VERSION 5.7 ;
  NOWIREEXTENSIONATPIN ON ;
  DIVIDERCHAR "/" ;
  BUSBITCHARS "[]" ;
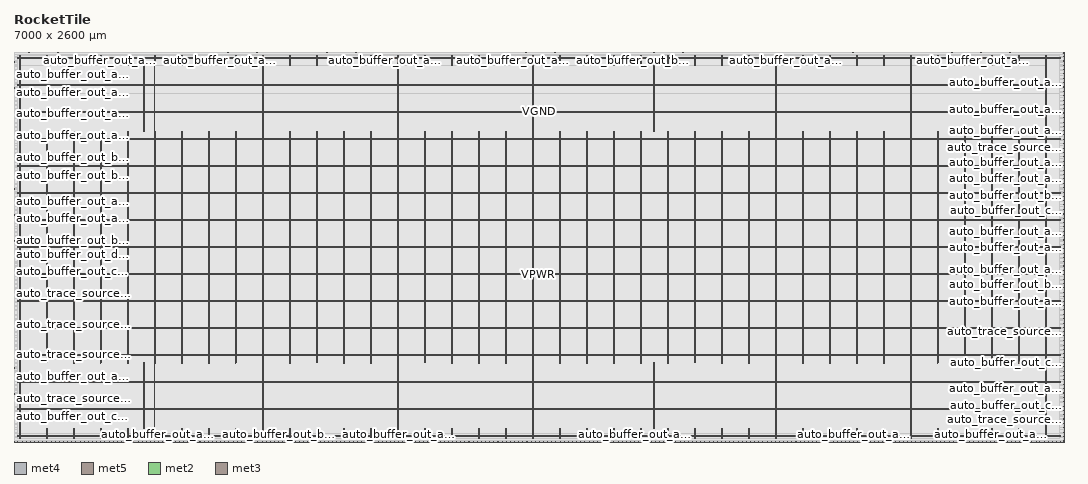
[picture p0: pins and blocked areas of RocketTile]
MACRO RocketTile
  CLASS BLOCK ;
  FOREIGN RocketTile ;
  ORIGIN 0.000 0.000 ;
  SIZE 7000.000 BY 2600.000 ;
  PIN VGND
    DIRECTION INOUT ;
    USE GROUND ;
    PORT
      LAYER met4 ;
        RECT 39.060 21.520 40.660 2578.800 ;
    END
    PORT
      LAYER met4 ;
        RECT 219.060 21.520 220.660 90.020 ;
    END
    PORT
      LAYER met4 ;
        RECT 219.060 527.140 220.660 2072.400 ;
    END
    PORT
      LAYER met4 ;
        RECT 219.060 2509.520 220.660 2578.800 ;
    END
    PORT
      LAYER met4 ;
        RECT 399.060 21.520 400.660 90.020 ;
    END
    PORT
      LAYER met4 ;
        RECT 399.060 526.520 400.660 2073.020 ;
    END
    PORT
      LAYER met4 ;
        RECT 399.060 2509.520 400.660 2578.800 ;
    END
    PORT
      LAYER met4 ;
        RECT 579.060 21.520 580.660 89.400 ;
    END
    PORT
      LAYER met4 ;
        RECT 579.060 527.140 580.660 2072.400 ;
    END
    PORT
      LAYER met4 ;
        RECT 579.060 2510.140 580.660 2578.800 ;
    END
    PORT
      LAYER met4 ;
        RECT 759.060 21.520 760.660 90.020 ;
    END
    PORT
      LAYER met4 ;
        RECT 759.060 526.520 760.660 2073.020 ;
    END
    PORT
      LAYER met4 ;
        RECT 759.060 2509.520 760.660 2578.800 ;
    END
    PORT
      LAYER met4 ;
        RECT 939.060 21.520 940.660 90.020 ;
    END
    PORT
      LAYER met4 ;
        RECT 939.060 526.520 940.660 2073.020 ;
    END
    PORT
      LAYER met4 ;
        RECT 939.060 2509.520 940.660 2578.800 ;
    END
    PORT
      LAYER met4 ;
        RECT 1119.060 21.520 1120.660 90.020 ;
    END
    PORT
      LAYER met4 ;
        RECT 1119.060 526.520 1120.660 2073.020 ;
    END
    PORT
      LAYER met4 ;
        RECT 1119.060 2509.520 1120.660 2578.800 ;
    END
    PORT
      LAYER met4 ;
        RECT 1299.060 21.520 1300.660 90.020 ;
    END
    PORT
      LAYER met4 ;
        RECT 1299.060 526.520 1300.660 2073.020 ;
    END
    PORT
      LAYER met4 ;
        RECT 1299.060 2509.520 1300.660 2578.800 ;
    END
    PORT
      LAYER met4 ;
        RECT 1479.060 21.520 1480.660 89.400 ;
    END
    PORT
      LAYER met4 ;
        RECT 1479.060 527.140 1480.660 2072.400 ;
    END
    PORT
      LAYER met4 ;
        RECT 1479.060 2510.140 1480.660 2578.800 ;
    END
    PORT
      LAYER met4 ;
        RECT 1659.060 21.520 1660.660 2578.800 ;
    END
    PORT
      LAYER met4 ;
        RECT 1839.060 21.520 1840.660 90.020 ;
    END
    PORT
      LAYER met4 ;
        RECT 1839.060 526.520 1840.660 2073.020 ;
    END
    PORT
      LAYER met4 ;
        RECT 1839.060 2509.520 1840.660 2578.800 ;
    END
    PORT
      LAYER met4 ;
        RECT 2019.060 21.520 2020.660 90.020 ;
    END
    PORT
      LAYER met4 ;
        RECT 2019.060 527.140 2020.660 2072.400 ;
    END
    PORT
      LAYER met4 ;
        RECT 2019.060 2509.520 2020.660 2578.800 ;
    END
    PORT
      LAYER met4 ;
        RECT 2199.060 21.520 2200.660 90.020 ;
    END
    PORT
      LAYER met4 ;
        RECT 2199.060 526.520 2200.660 2073.020 ;
    END
    PORT
      LAYER met4 ;
        RECT 2199.060 2509.520 2200.660 2578.800 ;
    END
    PORT
      LAYER met4 ;
        RECT 2379.060 21.520 2380.660 90.020 ;
    END
    PORT
      LAYER met4 ;
        RECT 2379.060 526.520 2380.660 2073.020 ;
    END
    PORT
      LAYER met4 ;
        RECT 2379.060 2509.520 2380.660 2578.800 ;
    END
    PORT
      LAYER met4 ;
        RECT 2559.060 21.520 2560.660 2578.800 ;
    END
    PORT
      LAYER met4 ;
        RECT 2739.060 21.520 2740.660 90.020 ;
    END
    PORT
      LAYER met4 ;
        RECT 2739.060 527.140 2740.660 2072.400 ;
    END
    PORT
      LAYER met4 ;
        RECT 2739.060 2509.520 2740.660 2578.800 ;
    END
    PORT
      LAYER met4 ;
        RECT 2919.060 21.520 2920.660 90.020 ;
    END
    PORT
      LAYER met4 ;
        RECT 2919.060 526.520 2920.660 2073.020 ;
    END
    PORT
      LAYER met4 ;
        RECT 2919.060 2509.520 2920.660 2578.800 ;
    END
    PORT
      LAYER met4 ;
        RECT 3099.060 21.520 3100.660 90.020 ;
    END
    PORT
      LAYER met4 ;
        RECT 3099.060 526.520 3100.660 2073.020 ;
    END
    PORT
      LAYER met4 ;
        RECT 3099.060 2509.520 3100.660 2578.800 ;
    END
    PORT
      LAYER met4 ;
        RECT 3279.060 21.520 3280.660 90.020 ;
    END
    PORT
      LAYER met4 ;
        RECT 3279.060 526.520 3280.660 2073.020 ;
    END
    PORT
      LAYER met4 ;
        RECT 3279.060 2509.520 3280.660 2578.800 ;
    END
    PORT
      LAYER met4 ;
        RECT 3459.060 21.520 3460.660 2578.800 ;
    END
    PORT
      LAYER met4 ;
        RECT 3639.060 21.520 3640.660 90.020 ;
    END
    PORT
      LAYER met4 ;
        RECT 3639.060 526.520 3640.660 2073.020 ;
    END
    PORT
      LAYER met4 ;
        RECT 3639.060 2509.520 3640.660 2578.800 ;
    END
    PORT
      LAYER met4 ;
        RECT 3819.060 21.520 3820.660 89.400 ;
    END
    PORT
      LAYER met4 ;
        RECT 3819.060 526.520 3820.660 2073.020 ;
    END
    PORT
      LAYER met4 ;
        RECT 3819.060 2510.140 3820.660 2578.800 ;
    END
    PORT
      LAYER met4 ;
        RECT 3999.060 21.520 4000.660 90.020 ;
    END
    PORT
      LAYER met4 ;
        RECT 3999.060 526.520 4000.660 2073.020 ;
    END
    PORT
      LAYER met4 ;
        RECT 3999.060 2509.520 4000.660 2578.800 ;
    END
    PORT
      LAYER met4 ;
        RECT 4179.060 21.520 4180.660 90.020 ;
    END
    PORT
      LAYER met4 ;
        RECT 4179.060 526.520 4180.660 2073.020 ;
    END
    PORT
      LAYER met4 ;
        RECT 4179.060 2509.520 4180.660 2578.800 ;
    END
    PORT
      LAYER met4 ;
        RECT 4359.060 21.520 4360.660 90.020 ;
    END
    PORT
      LAYER met4 ;
        RECT 4359.060 526.520 4360.660 2073.020 ;
    END
    PORT
      LAYER met4 ;
        RECT 4359.060 2509.520 4360.660 2578.800 ;
    END
    PORT
      LAYER met4 ;
        RECT 4539.060 21.520 4540.660 90.020 ;
    END
    PORT
      LAYER met4 ;
        RECT 4539.060 527.140 4540.660 2072.400 ;
    END
    PORT
      LAYER met4 ;
        RECT 4539.060 2509.520 4540.660 2578.800 ;
    END
    PORT
      LAYER met4 ;
        RECT 4719.060 21.520 4720.660 90.020 ;
    END
    PORT
      LAYER met4 ;
        RECT 4719.060 526.520 4720.660 2073.020 ;
    END
    PORT
      LAYER met4 ;
        RECT 4719.060 2509.520 4720.660 2578.800 ;
    END
    PORT
      LAYER met4 ;
        RECT 4899.060 21.520 4900.660 90.020 ;
    END
    PORT
      LAYER met4 ;
        RECT 4899.060 526.520 4900.660 2073.020 ;
    END
    PORT
      LAYER met4 ;
        RECT 4899.060 2509.520 4900.660 2578.800 ;
    END
    PORT
      LAYER met4 ;
        RECT 5079.060 21.520 5080.660 2578.800 ;
    END
    PORT
      LAYER met4 ;
        RECT 5259.060 21.520 5260.660 90.020 ;
    END
    PORT
      LAYER met4 ;
        RECT 5259.060 526.520 5260.660 2073.020 ;
    END
    PORT
      LAYER met4 ;
        RECT 5259.060 2509.520 5260.660 2578.800 ;
    END
    PORT
      LAYER met4 ;
        RECT 5439.060 21.520 5440.660 90.020 ;
    END
    PORT
      LAYER met4 ;
        RECT 5439.060 526.520 5440.660 2073.020 ;
    END
    PORT
      LAYER met4 ;
        RECT 5439.060 2509.520 5440.660 2578.800 ;
    END
    PORT
      LAYER met4 ;
        RECT 5619.060 21.520 5620.660 90.020 ;
    END
    PORT
      LAYER met4 ;
        RECT 5619.060 526.520 5620.660 2073.020 ;
    END
    PORT
      LAYER met4 ;
        RECT 5619.060 2509.520 5620.660 2578.800 ;
    END
    PORT
      LAYER met4 ;
        RECT 5799.060 21.520 5800.660 89.400 ;
    END
    PORT
      LAYER met4 ;
        RECT 5799.060 526.520 5800.660 2073.020 ;
    END
    PORT
      LAYER met4 ;
        RECT 5799.060 2510.140 5800.660 2578.800 ;
    END
    PORT
      LAYER met4 ;
        RECT 5979.060 21.520 5980.660 2578.800 ;
    END
    PORT
      LAYER met4 ;
        RECT 6159.060 21.520 6160.660 90.020 ;
    END
    PORT
      LAYER met4 ;
        RECT 6159.060 527.140 6160.660 2072.400 ;
    END
    PORT
      LAYER met4 ;
        RECT 6159.060 2509.520 6160.660 2578.800 ;
    END
    PORT
      LAYER met4 ;
        RECT 6339.060 21.520 6340.660 90.020 ;
    END
    PORT
      LAYER met4 ;
        RECT 6339.060 527.140 6340.660 2072.400 ;
    END
    PORT
      LAYER met4 ;
        RECT 6339.060 2509.520 6340.660 2578.800 ;
    END
    PORT
      LAYER met4 ;
        RECT 6519.060 21.520 6520.660 90.020 ;
    END
    PORT
      LAYER met4 ;
        RECT 6519.060 526.520 6520.660 2073.020 ;
    END
    PORT
      LAYER met4 ;
        RECT 6519.060 2509.520 6520.660 2578.800 ;
    END
    PORT
      LAYER met4 ;
        RECT 6699.060 21.520 6700.660 90.020 ;
    END
    PORT
      LAYER met4 ;
        RECT 6699.060 526.520 6700.660 2073.020 ;
    END
    PORT
      LAYER met4 ;
        RECT 6699.060 2509.520 6700.660 2578.800 ;
    END
    PORT
      LAYER met4 ;
        RECT 6879.060 21.520 6880.660 2578.800 ;
    END
    PORT
      LAYER met5 ;
        RECT 20.000 40.910 6979.820 42.510 ;
    END
    PORT
      LAYER met5 ;
        RECT 20.000 220.910 6979.820 222.510 ;
    END
    PORT
      LAYER met5 ;
        RECT 20.000 400.910 6979.820 402.510 ;
    END
    PORT
      LAYER met5 ;
        RECT 20.000 580.910 6979.820 582.510 ;
    END
    PORT
      LAYER met5 ;
        RECT 20.000 760.910 6979.820 762.510 ;
    END
    PORT
      LAYER met5 ;
        RECT 20.000 940.910 6979.820 942.510 ;
    END
    PORT
      LAYER met5 ;
        RECT 20.000 1120.910 6979.820 1122.510 ;
    END
    PORT
      LAYER met5 ;
        RECT 20.000 1300.910 6979.820 1302.510 ;
    END
    PORT
      LAYER met5 ;
        RECT 20.000 1480.910 6979.820 1482.510 ;
    END
    PORT
      LAYER met5 ;
        RECT 20.000 1660.910 6979.820 1662.510 ;
    END
    PORT
      LAYER met5 ;
        RECT 20.000 1840.910 6979.820 1842.510 ;
    END
    PORT
      LAYER met5 ;
        RECT 20.000 2020.910 6979.820 2022.510 ;
    END
    PORT
      LAYER met5 ;
        RECT 20.000 2200.910 6979.820 2202.510 ;
    END
    PORT
      LAYER met5 ;
        RECT 20.000 2380.910 6979.820 2382.510 ;
    END
    PORT
      LAYER met5 ;
        RECT 20.000 2560.910 6979.820 2562.510 ;
    END
    PORT
      LAYER met4 ;
        RECT 865.380 86.800 866.980 527.920 ;
    END
    PORT
      LAYER met4 ;
        RECT 4267.540 2069.680 4269.140 2513.520 ;
    END
    PORT
      LAYER met4 ;
        RECT 865.380 2072.400 866.980 2513.520 ;
    END
    PORT
      LAYER met4 ;
        RECT 4267.540 86.800 4269.140 530.640 ;
    END
  END VGND
  PIN VPWR
    DIRECTION INOUT ;
    USE POWER ;
    PORT
      LAYER met4 ;
        RECT 35.760 21.520 37.360 2578.800 ;
    END
    PORT
      LAYER met4 ;
        RECT 215.760 21.520 217.360 90.020 ;
    END
    PORT
      LAYER met4 ;
        RECT 215.760 527.140 217.360 2072.400 ;
    END
    PORT
      LAYER met4 ;
        RECT 215.760 2509.520 217.360 2578.800 ;
    END
    PORT
      LAYER met4 ;
        RECT 395.760 21.520 397.360 90.020 ;
    END
    PORT
      LAYER met4 ;
        RECT 395.760 527.140 397.360 2072.400 ;
    END
    PORT
      LAYER met4 ;
        RECT 395.760 2509.520 397.360 2578.800 ;
    END
    PORT
      LAYER met4 ;
        RECT 575.760 21.520 577.360 90.020 ;
    END
    PORT
      LAYER met4 ;
        RECT 575.760 526.520 577.360 2073.020 ;
    END
    PORT
      LAYER met4 ;
        RECT 575.760 2509.520 577.360 2578.800 ;
    END
    PORT
      LAYER met4 ;
        RECT 755.760 21.520 757.360 90.020 ;
    END
    PORT
      LAYER met4 ;
        RECT 755.760 526.520 757.360 2073.020 ;
    END
    PORT
      LAYER met4 ;
        RECT 755.760 2509.520 757.360 2578.800 ;
    END
    PORT
      LAYER met4 ;
        RECT 935.760 21.520 937.360 2578.800 ;
    END
    PORT
      LAYER met4 ;
        RECT 1115.760 21.520 1117.360 89.400 ;
    END
    PORT
      LAYER met4 ;
        RECT 1115.760 527.140 1117.360 2072.400 ;
    END
    PORT
      LAYER met4 ;
        RECT 1115.760 2510.140 1117.360 2578.800 ;
    END
    PORT
      LAYER met4 ;
        RECT 1295.760 21.520 1297.360 90.020 ;
    END
    PORT
      LAYER met4 ;
        RECT 1295.760 526.520 1297.360 2073.020 ;
    END
    PORT
      LAYER met4 ;
        RECT 1295.760 2509.520 1297.360 2578.800 ;
    END
    PORT
      LAYER met4 ;
        RECT 1475.760 21.520 1477.360 90.020 ;
    END
    PORT
      LAYER met4 ;
        RECT 1475.760 526.520 1477.360 2073.020 ;
    END
    PORT
      LAYER met4 ;
        RECT 1475.760 2509.520 1477.360 2578.800 ;
    END
    PORT
      LAYER met4 ;
        RECT 1655.760 21.520 1657.360 2578.800 ;
    END
    PORT
      LAYER met4 ;
        RECT 1835.760 21.520 1837.360 90.020 ;
    END
    PORT
      LAYER met4 ;
        RECT 1835.760 526.520 1837.360 2073.020 ;
    END
    PORT
      LAYER met4 ;
        RECT 1835.760 2509.520 1837.360 2578.800 ;
    END
    PORT
      LAYER met4 ;
        RECT 2015.760 21.520 2017.360 89.400 ;
    END
    PORT
      LAYER met4 ;
        RECT 2015.760 527.140 2017.360 2072.400 ;
    END
    PORT
      LAYER met4 ;
        RECT 2015.760 2510.140 2017.360 2578.800 ;
    END
    PORT
      LAYER met4 ;
        RECT 2195.760 21.520 2197.360 90.020 ;
    END
    PORT
      LAYER met4 ;
        RECT 2195.760 526.520 2197.360 2073.020 ;
    END
    PORT
      LAYER met4 ;
        RECT 2195.760 2509.520 2197.360 2578.800 ;
    END
    PORT
      LAYER met4 ;
        RECT 2375.760 21.520 2377.360 90.020 ;
    END
    PORT
      LAYER met4 ;
        RECT 2375.760 526.520 2377.360 2073.020 ;
    END
    PORT
      LAYER met4 ;
        RECT 2375.760 2509.520 2377.360 2578.800 ;
    END
    PORT
      LAYER met4 ;
        RECT 2555.760 21.520 2557.360 2578.800 ;
    END
    PORT
      LAYER met4 ;
        RECT 2735.760 21.520 2737.360 90.020 ;
    END
    PORT
      LAYER met4 ;
        RECT 2735.760 527.140 2737.360 2072.400 ;
    END
    PORT
      LAYER met4 ;
        RECT 2735.760 2509.520 2737.360 2578.800 ;
    END
    PORT
      LAYER met4 ;
        RECT 2915.760 21.520 2917.360 89.400 ;
    END
    PORT
      LAYER met4 ;
        RECT 2915.760 527.140 2917.360 2072.400 ;
    END
    PORT
      LAYER met4 ;
        RECT 2915.760 2510.140 2917.360 2578.800 ;
    END
    PORT
      LAYER met4 ;
        RECT 3095.760 21.520 3097.360 90.020 ;
    END
    PORT
      LAYER met4 ;
        RECT 3095.760 526.520 3097.360 2073.020 ;
    END
    PORT
      LAYER met4 ;
        RECT 3095.760 2509.520 3097.360 2578.800 ;
    END
    PORT
      LAYER met4 ;
        RECT 3275.760 21.520 3277.360 90.020 ;
    END
    PORT
      LAYER met4 ;
        RECT 3275.760 526.520 3277.360 2073.020 ;
    END
    PORT
      LAYER met4 ;
        RECT 3275.760 2509.520 3277.360 2578.800 ;
    END
    PORT
      LAYER met4 ;
        RECT 3455.760 21.520 3457.360 2578.800 ;
    END
    PORT
      LAYER met4 ;
        RECT 3635.760 21.520 3637.360 90.020 ;
    END
    PORT
      LAYER met4 ;
        RECT 3635.760 526.520 3637.360 2073.020 ;
    END
    PORT
      LAYER met4 ;
        RECT 3635.760 2509.520 3637.360 2578.800 ;
    END
    PORT
      LAYER met4 ;
        RECT 3815.760 21.520 3817.360 90.020 ;
    END
    PORT
      LAYER met4 ;
        RECT 3815.760 527.140 3817.360 2072.400 ;
    END
    PORT
      LAYER met4 ;
        RECT 3815.760 2509.520 3817.360 2578.800 ;
    END
    PORT
      LAYER met4 ;
        RECT 3995.760 21.520 3997.360 90.020 ;
    END
    PORT
      LAYER met4 ;
        RECT 3995.760 526.520 3997.360 2073.020 ;
    END
    PORT
      LAYER met4 ;
        RECT 3995.760 2509.520 3997.360 2578.800 ;
    END
    PORT
      LAYER met4 ;
        RECT 4175.760 21.520 4177.360 90.020 ;
    END
    PORT
      LAYER met4 ;
        RECT 4175.760 526.520 4177.360 2073.020 ;
    END
    PORT
      LAYER met4 ;
        RECT 4175.760 2509.520 4177.360 2578.800 ;
    END
    PORT
      LAYER met4 ;
        RECT 4355.760 21.520 4357.360 90.020 ;
    END
    PORT
      LAYER met4 ;
        RECT 4355.760 526.520 4357.360 2073.020 ;
    END
    PORT
      LAYER met4 ;
        RECT 4355.760 2509.520 4357.360 2578.800 ;
    END
    PORT
      LAYER met4 ;
        RECT 4535.760 21.520 4537.360 90.020 ;
    END
    PORT
      LAYER met4 ;
        RECT 4535.760 527.140 4537.360 2072.400 ;
    END
    PORT
      LAYER met4 ;
        RECT 4535.760 2509.520 4537.360 2578.800 ;
    END
    PORT
      LAYER met4 ;
        RECT 4715.760 21.520 4717.360 89.400 ;
    END
    PORT
      LAYER met4 ;
        RECT 4715.760 527.140 4717.360 2072.400 ;
    END
    PORT
      LAYER met4 ;
        RECT 4715.760 2510.140 4717.360 2578.800 ;
    END
    PORT
      LAYER met4 ;
        RECT 4895.760 21.520 4897.360 90.020 ;
    END
    PORT
      LAYER met4 ;
        RECT 4895.760 526.520 4897.360 2073.020 ;
    END
    PORT
      LAYER met4 ;
        RECT 4895.760 2509.520 4897.360 2578.800 ;
    END
    PORT
      LAYER met4 ;
        RECT 5075.760 21.520 5077.360 2578.800 ;
    END
    PORT
      LAYER met4 ;
        RECT 5255.760 21.520 5257.360 90.020 ;
    END
    PORT
      LAYER met4 ;
        RECT 5255.760 526.520 5257.360 2073.020 ;
    END
    PORT
      LAYER met4 ;
        RECT 5255.760 2509.520 5257.360 2578.800 ;
    END
    PORT
      LAYER met4 ;
        RECT 5435.760 21.520 5437.360 90.020 ;
    END
    PORT
      LAYER met4 ;
        RECT 5435.760 526.520 5437.360 2073.020 ;
    END
    PORT
      LAYER met4 ;
        RECT 5435.760 2509.520 5437.360 2578.800 ;
    END
    PORT
      LAYER met4 ;
        RECT 5615.760 21.520 5617.360 89.400 ;
    END
    PORT
      LAYER met4 ;
        RECT 5615.760 527.140 5617.360 2072.400 ;
    END
    PORT
      LAYER met4 ;
        RECT 5615.760 2510.140 5617.360 2578.800 ;
    END
    PORT
      LAYER met4 ;
        RECT 5795.760 21.520 5797.360 90.020 ;
    END
    PORT
      LAYER met4 ;
        RECT 5795.760 526.520 5797.360 2073.020 ;
    END
    PORT
      LAYER met4 ;
        RECT 5795.760 2509.520 5797.360 2578.800 ;
    END
    PORT
      LAYER met4 ;
        RECT 5975.760 21.520 5977.360 2578.800 ;
    END
    PORT
      LAYER met4 ;
        RECT 6155.760 21.520 6157.360 90.020 ;
    END
    PORT
      LAYER met4 ;
        RECT 6155.760 526.520 6157.360 2073.020 ;
    END
    PORT
      LAYER met4 ;
        RECT 6155.760 2509.520 6157.360 2578.800 ;
    END
    PORT
      LAYER met4 ;
        RECT 6335.760 21.520 6337.360 90.020 ;
    END
    PORT
      LAYER met4 ;
        RECT 6335.760 527.140 6337.360 2072.400 ;
    END
    PORT
      LAYER met4 ;
        RECT 6335.760 2509.520 6337.360 2578.800 ;
    END
    PORT
      LAYER met4 ;
        RECT 6515.760 21.520 6517.360 89.400 ;
    END
    PORT
      LAYER met4 ;
        RECT 6515.760 527.140 6517.360 2072.400 ;
    END
    PORT
      LAYER met4 ;
        RECT 6515.760 2510.140 6517.360 2578.800 ;
    END
    PORT
      LAYER met4 ;
        RECT 6695.760 21.520 6697.360 90.020 ;
    END
    PORT
      LAYER met4 ;
        RECT 6695.760 526.520 6697.360 2073.020 ;
    END
    PORT
      LAYER met4 ;
        RECT 6695.760 2509.520 6697.360 2578.800 ;
    END
    PORT
      LAYER met4 ;
        RECT 6875.760 21.520 6877.360 2578.800 ;
    END
    PORT
      LAYER met5 ;
        RECT 20.000 37.610 6979.820 39.210 ;
    END
    PORT
      LAYER met5 ;
        RECT 20.000 217.610 6979.820 219.210 ;
    END
    PORT
      LAYER met5 ;
        RECT 20.000 397.610 6979.820 399.210 ;
    END
    PORT
      LAYER met5 ;
        RECT 20.000 577.610 6979.820 579.210 ;
    END
    PORT
      LAYER met5 ;
        RECT 20.000 757.610 6979.820 759.210 ;
    END
    PORT
      LAYER met5 ;
        RECT 20.000 937.610 6979.820 939.210 ;
    END
    PORT
      LAYER met5 ;
        RECT 20.000 1117.610 6979.820 1119.210 ;
    END
    PORT
      LAYER met5 ;
        RECT 20.000 1297.610 6979.820 1299.210 ;
    END
    PORT
      LAYER met5 ;
        RECT 20.000 1477.610 6979.820 1479.210 ;
    END
    PORT
      LAYER met5 ;
        RECT 20.000 1657.610 6979.820 1659.210 ;
    END
    PORT
      LAYER met5 ;
        RECT 20.000 1837.610 6979.820 1839.210 ;
    END
    PORT
      LAYER met5 ;
        RECT 20.000 2017.610 6979.820 2019.210 ;
    END
    PORT
      LAYER met5 ;
        RECT 20.000 2197.610 6979.820 2199.210 ;
    END
    PORT
      LAYER met5 ;
        RECT 20.000 2377.610 6979.820 2379.210 ;
    END
    PORT
      LAYER met5 ;
        RECT 20.000 2557.610 6979.820 2559.210 ;
    END
    PORT
      LAYER met4 ;
        RECT 4263.860 2069.680 4265.460 2513.520 ;
    END
    PORT
      LAYER met4 ;
        RECT 4263.860 86.800 4265.460 530.640 ;
    END
  END VPWR
  PIN auto_buffer_out_a_bits_address[0]
    DIRECTION OUTPUT TRISTATE ;
    USE SIGNAL ;
    ANTENNADIFFAREA 0.340600 ;
    PORT
      LAYER met2 ;
        RECT 570.030 2596.000 570.310 2600.000 ;
    END
  END auto_buffer_out_a_bits_address[0]
  PIN auto_buffer_out_a_bits_address[10]
    DIRECTION OUTPUT TRISTATE ;
    USE SIGNAL ;
    ANTENNADIFFAREA 0.340600 ;
    PORT
      LAYER met3 ;
        RECT 0.000 1601.440 4.000 1602.040 ;
    END
  END auto_buffer_out_a_bits_address[10]
  PIN auto_buffer_out_a_bits_address[11]
    DIRECTION OUTPUT TRISTATE ;
    USE SIGNAL ;
    ANTENNADIFFAREA 0.340600 ;
    PORT
      LAYER met2 ;
        RECT 2473.050 2596.000 2473.330 2600.000 ;
    END
  END auto_buffer_out_a_bits_address[11]
  PIN auto_buffer_out_a_bits_address[12]
    DIRECTION OUTPUT TRISTATE ;
    USE SIGNAL ;
    ANTENNADIFFAREA 0.340600 ;
    PORT
      LAYER met3 ;
        RECT 6996.000 414.840 7000.000 415.440 ;
    END
  END auto_buffer_out_a_bits_address[12]
  PIN auto_buffer_out_a_bits_address[13]
    DIRECTION OUTPUT TRISTATE ;
    USE SIGNAL ;
    ANTENNADIFFAREA 0.340600 ;
    PORT
      LAYER met2 ;
        RECT 5847.610 0.000 5847.890 4.000 ;
    END
  END auto_buffer_out_a_bits_address[13]
  PIN auto_buffer_out_a_bits_address[14]
    DIRECTION OUTPUT TRISTATE ;
    USE SIGNAL ;
    ANTENNADIFFAREA 0.340600 ;
    PORT
      LAYER met2 ;
        RECT 2086.650 2596.000 2086.930 2600.000 ;
    END
  END auto_buffer_out_a_bits_address[14]
  PIN auto_buffer_out_a_bits_address[15]
    DIRECTION OUTPUT TRISTATE ;
    USE SIGNAL ;
    ANTENNADIFFAREA 0.340600 ;
    PORT
      LAYER met2 ;
        RECT 4137.790 0.000 4138.070 4.000 ;
    END
  END auto_buffer_out_a_bits_address[15]
  PIN auto_buffer_out_a_bits_address[16]
    DIRECTION OUTPUT TRISTATE ;
    USE SIGNAL ;
    ANTENNADIFFAREA 0.340600 ;
    PORT
      LAYER met3 ;
        RECT 0.000 608.640 4.000 609.240 ;
    END
  END auto_buffer_out_a_bits_address[16]
  PIN auto_buffer_out_a_bits_address[17]
    DIRECTION OUTPUT TRISTATE ;
    USE SIGNAL ;
    ANTENNADIFFAREA 0.340600 ;
    PORT
      LAYER met2 ;
        RECT 962.870 0.000 963.150 4.000 ;
    END
  END auto_buffer_out_a_bits_address[17]
  PIN auto_buffer_out_a_bits_address[18]
    DIRECTION OUTPUT TRISTATE ;
    USE SIGNAL ;
    ANTENNADIFFAREA 0.340600 ;
    PORT
      LAYER met3 ;
        RECT 6996.000 2397.040 7000.000 2397.640 ;
    END
  END auto_buffer_out_a_bits_address[18]
  PIN auto_buffer_out_a_bits_address[19]
    DIRECTION OUTPUT TRISTATE ;
    USE SIGNAL ;
    ANTENNADIFFAREA 0.340600 ;
    PORT
      LAYER met2 ;
        RECT 6391.790 2596.000 6392.070 2600.000 ;
    END
  END auto_buffer_out_a_bits_address[19]
  PIN auto_buffer_out_a_bits_address[1]
    DIRECTION OUTPUT TRISTATE ;
    USE SIGNAL ;
    ANTENNADIFFAREA 0.340600 ;
    PORT
      LAYER met2 ;
        RECT 1342.830 2596.000 1343.110 2600.000 ;
    END
  END auto_buffer_out_a_bits_address[1]
  PIN auto_buffer_out_a_bits_address[20]
    DIRECTION OUTPUT TRISTATE ;
    USE SIGNAL ;
    ANTENNADIFFAREA 0.340600 ;
    PORT
      LAYER met2 ;
        RECT 3329.570 2596.000 3329.850 2600.000 ;
    END
  END auto_buffer_out_a_bits_address[20]
  PIN auto_buffer_out_a_bits_address[21]
    DIRECTION OUTPUT TRISTATE ;
    USE SIGNAL ;
    ANTENNADIFFAREA 0.340600 ;
    PORT
      LAYER met2 ;
        RECT 1812.950 2596.000 1813.230 2600.000 ;
    END
  END auto_buffer_out_a_bits_address[21]
  PIN auto_buffer_out_a_bits_address[22]
    DIRECTION OUTPUT TRISTATE ;
    USE SIGNAL ;
    ANTENNADIFFAREA 0.340600 ;
    PORT
      LAYER met3 ;
        RECT 6996.000 357.040 7000.000 357.640 ;
    END
  END auto_buffer_out_a_bits_address[22]
  PIN auto_buffer_out_a_bits_address[23]
    DIRECTION OUTPUT TRISTATE ;
    USE SIGNAL ;
    ANTENNADIFFAREA 0.340600 ;
    PORT
      LAYER met3 ;
        RECT 6996.000 938.440 7000.000 939.040 ;
    END
  END auto_buffer_out_a_bits_address[23]
  PIN auto_buffer_out_a_bits_address[24]
    DIRECTION OUTPUT TRISTATE ;
    USE SIGNAL ;
    ANTENNADIFFAREA 0.340600 ;
    PORT
      LAYER met2 ;
        RECT 1957.850 0.000 1958.130 4.000 ;
    END
  END auto_buffer_out_a_bits_address[24]
  PIN auto_buffer_out_a_bits_address[25]
    DIRECTION OUTPUT TRISTATE ;
    USE SIGNAL ;
    ANTENNADIFFAREA 0.340600 ;
    PORT
      LAYER met2 ;
        RECT 6510.930 0.000 6511.210 4.000 ;
    END
  END auto_buffer_out_a_bits_address[25]
  PIN auto_buffer_out_a_bits_address[26]
    DIRECTION OUTPUT TRISTATE ;
    USE SIGNAL ;
    ANTENNADIFFAREA 0.340600 ;
    PORT
      LAYER met2 ;
        RECT 4855.850 0.000 4856.130 4.000 ;
    END
  END auto_buffer_out_a_bits_address[26]
  PIN auto_buffer_out_a_bits_address[27]
    DIRECTION OUTPUT TRISTATE ;
    USE SIGNAL ;
    ANTENNADIFFAREA 0.340600 ;
    PORT
      LAYER met2 ;
        RECT 2756.410 0.000 2756.690 4.000 ;
    END
  END auto_buffer_out_a_bits_address[27]
  PIN auto_buffer_out_a_bits_address[28]
    DIRECTION OUTPUT TRISTATE ;
    USE SIGNAL ;
    ANTENNADIFFAREA 0.340600 ;
    PORT
      LAYER met2 ;
        RECT 5986.070 0.000 5986.350 4.000 ;
    END
  END auto_buffer_out_a_bits_address[28]
  PIN auto_buffer_out_a_bits_address[29]
    DIRECTION OUTPUT TRISTATE ;
    USE SIGNAL ;
    ANTENNADIFFAREA 0.340600 ;
    PORT
      LAYER met2 ;
        RECT 3751.390 0.000 3751.670 4.000 ;
    END
  END auto_buffer_out_a_bits_address[29]
  PIN auto_buffer_out_a_bits_address[2]
    DIRECTION OUTPUT TRISTATE ;
    USE SIGNAL ;
    ANTENNADIFFAREA 0.340600 ;
    PORT
      LAYER met2 ;
        RECT 1065.910 2596.000 1066.190 2600.000 ;
    END
  END auto_buffer_out_a_bits_address[2]
  PIN auto_buffer_out_a_bits_address[30]
    DIRECTION OUTPUT TRISTATE ;
    USE SIGNAL ;
    ANTENNADIFFAREA 0.340600 ;
    PORT
      LAYER met2 ;
        RECT 2141.390 2596.000 2141.670 2600.000 ;
    END
  END auto_buffer_out_a_bits_address[30]
  PIN auto_buffer_out_a_bits_address[31]
    DIRECTION OUTPUT TRISTATE ;
    USE SIGNAL ;
    ANTENNADIFFAREA 0.340600 ;
    PORT
      LAYER met2 ;
        RECT 5841.170 2596.000 5841.450 2600.000 ;
    END
  END auto_buffer_out_a_bits_address[31]
  PIN auto_buffer_out_a_bits_address[3]
    DIRECTION OUTPUT TRISTATE ;
    USE SIGNAL ;
    ANTENNADIFFAREA 0.340600 ;
    PORT
      LAYER met3 ;
        RECT 6996.000 1870.040 7000.000 1870.640 ;
    END
  END auto_buffer_out_a_bits_address[3]
  PIN auto_buffer_out_a_bits_address[4]
    DIRECTION OUTPUT TRISTATE ;
    USE SIGNAL ;
    ANTENNADIFFAREA 0.340600 ;
    PORT
      LAYER met2 ;
        RECT 1709.910 0.000 1710.190 4.000 ;
    END
  END auto_buffer_out_a_bits_address[4]
  PIN auto_buffer_out_a_bits_address[5]
    DIRECTION OUTPUT TRISTATE ;
    USE SIGNAL ;
    ANTENNADIFFAREA 0.340600 ;
    PORT
      LAYER met3 ;
        RECT 0.000 1543.640 4.000 1544.240 ;
    END
  END auto_buffer_out_a_bits_address[5]
  PIN auto_buffer_out_a_bits_address[6]
    DIRECTION OUTPUT TRISTATE ;
    USE SIGNAL ;
    ANTENNADIFFAREA 0.340600 ;
    PORT
      LAYER met2 ;
        RECT 1922.430 2596.000 1922.710 2600.000 ;
    END
  END auto_buffer_out_a_bits_address[6]
  PIN auto_buffer_out_a_bits_address[7]
    DIRECTION OUTPUT TRISTATE ;
    USE SIGNAL ;
    ANTENNADIFFAREA 0.340600 ;
    PORT
      LAYER met2 ;
        RECT 1294.530 0.000 1294.810 4.000 ;
    END
  END auto_buffer_out_a_bits_address[7]
  PIN auto_buffer_out_a_bits_address[8]
    DIRECTION OUTPUT TRISTATE ;
    USE SIGNAL ;
    ANTENNADIFFAREA 0.340600 ;
    PORT
      LAYER met3 ;
        RECT 0.000 958.840 4.000 959.440 ;
    END
  END auto_buffer_out_a_bits_address[8]
  PIN auto_buffer_out_a_bits_address[9]
    DIRECTION OUTPUT TRISTATE ;
    USE SIGNAL ;
    ANTENNADIFFAREA 0.340600 ;
    PORT
      LAYER met2 ;
        RECT 3606.490 2596.000 3606.770 2600.000 ;
    END
  END auto_buffer_out_a_bits_address[9]
  PIN auto_buffer_out_a_bits_data[0]
    DIRECTION OUTPUT TRISTATE ;
    USE SIGNAL ;
    ANTENNADIFFAREA 0.340600 ;
    PORT
      LAYER met3 ;
        RECT 6996.000 707.240 7000.000 707.840 ;
    END
  END auto_buffer_out_a_bits_data[0]
  PIN auto_buffer_out_a_bits_data[10]
    DIRECTION OUTPUT TRISTATE ;
    USE SIGNAL ;
    ANTENNADIFFAREA 0.340600 ;
    PORT
      LAYER met2 ;
        RECT 1783.970 2596.000 1784.250 2600.000 ;
    END
  END auto_buffer_out_a_bits_data[10]
  PIN auto_buffer_out_a_bits_data[11]
    DIRECTION OUTPUT TRISTATE ;
    USE SIGNAL ;
    ANTENNADIFFAREA 0.340600 ;
    PORT
      LAYER met2 ;
        RECT 6234.010 0.000 6234.290 4.000 ;
    END
  END auto_buffer_out_a_bits_data[11]
  PIN auto_buffer_out_a_bits_data[12]
    DIRECTION OUTPUT TRISTATE ;
    USE SIGNAL ;
    ANTENNADIFFAREA 0.340600 ;
    PORT
      LAYER met3 ;
        RECT 0.000 2502.440 4.000 2503.040 ;
    END
  END auto_buffer_out_a_bits_data[12]
  PIN auto_buffer_out_a_bits_data[13]
    DIRECTION OUTPUT TRISTATE ;
    USE SIGNAL ;
    ANTENNADIFFAREA 0.340600 ;
    PORT
      LAYER met2 ;
        RECT 3419.730 0.000 3420.010 4.000 ;
    END
  END auto_buffer_out_a_bits_data[13]
  PIN auto_buffer_out_a_bits_data[14]
    DIRECTION OUTPUT TRISTATE ;
    USE SIGNAL ;
    ANTENNADIFFAREA 0.340600 ;
    PORT
      LAYER met3 ;
        RECT 0.000 931.640 4.000 932.240 ;
    END
  END auto_buffer_out_a_bits_data[14]
  PIN auto_buffer_out_a_bits_data[15]
    DIRECTION OUTPUT TRISTATE ;
    USE SIGNAL ;
    ANTENNADIFFAREA 0.340600 ;
    PORT
      LAYER met3 ;
        RECT 0.000 1162.840 4.000 1163.440 ;
    END
  END auto_buffer_out_a_bits_data[15]
  PIN auto_buffer_out_a_bits_data[16]
    DIRECTION OUTPUT TRISTATE ;
    USE SIGNAL ;
    ANTENNADIFFAREA 0.340600 ;
    PORT
      LAYER met2 ;
        RECT 2176.810 0.000 2177.090 4.000 ;
    END
  END auto_buffer_out_a_bits_data[16]
  PIN auto_buffer_out_a_bits_data[17]
    DIRECTION OUTPUT TRISTATE ;
    USE SIGNAL ;
    ANTENNADIFFAREA 0.340600 ;
    PORT
      LAYER met2 ;
        RECT 4797.890 0.000 4798.170 4.000 ;
    END
  END auto_buffer_out_a_bits_data[17]
  PIN auto_buffer_out_a_bits_data[18]
    DIRECTION OUTPUT TRISTATE ;
    USE SIGNAL ;
    ANTENNADIFFAREA 0.340600 ;
    PORT
      LAYER met3 ;
        RECT 0.000 435.240 4.000 435.840 ;
    END
  END auto_buffer_out_a_bits_data[18]
  PIN auto_buffer_out_a_bits_data[19]
    DIRECTION OUTPUT TRISTATE ;
    USE SIGNAL ;
    ANTENNADIFFAREA 0.340600 ;
    PORT
      LAYER met2 ;
        RECT 5957.090 0.000 5957.370 4.000 ;
    END
  END auto_buffer_out_a_bits_data[19]
  PIN auto_buffer_out_a_bits_data[1]
    DIRECTION OUTPUT TRISTATE ;
    USE SIGNAL ;
    ANTENNADIFFAREA 0.340600 ;
    PORT
      LAYER met3 ;
        RECT 6996.000 1404.240 7000.000 1404.840 ;
    END
  END auto_buffer_out_a_bits_data[1]
  PIN auto_buffer_out_a_bits_data[20]
    DIRECTION OUTPUT TRISTATE ;
    USE SIGNAL ;
    ANTENNADIFFAREA 0.340600 ;
    PORT
      LAYER met2 ;
        RECT 1233.350 2596.000 1233.630 2600.000 ;
    END
  END auto_buffer_out_a_bits_data[20]
  PIN auto_buffer_out_a_bits_data[21]
    DIRECTION OUTPUT TRISTATE ;
    USE SIGNAL ;
    ANTENNADIFFAREA 0.340600 ;
    PORT
      LAYER met2 ;
        RECT 5812.190 2596.000 5812.470 2600.000 ;
    END
  END auto_buffer_out_a_bits_data[21]
  PIN auto_buffer_out_a_bits_data[22]
    DIRECTION OUTPUT TRISTATE ;
    USE SIGNAL ;
    ANTENNADIFFAREA 0.340600 ;
    PORT
      LAYER met3 ;
        RECT 6996.000 2074.040 7000.000 2074.640 ;
    END
  END auto_buffer_out_a_bits_data[22]
  PIN auto_buffer_out_a_bits_data[23]
    DIRECTION OUTPUT TRISTATE ;
    USE SIGNAL ;
    ANTENNADIFFAREA 0.340600 ;
    PORT
      LAYER met3 ;
        RECT 6996.000 2539.840 7000.000 2540.440 ;
    END
  END auto_buffer_out_a_bits_data[23]
  PIN auto_buffer_out_a_bits_data[24]
    DIRECTION OUTPUT TRISTATE ;
    USE SIGNAL ;
    ANTENNADIFFAREA 0.340600 ;
    PORT
      LAYER met2 ;
        RECT 576.470 0.000 576.750 4.000 ;
    END
  END auto_buffer_out_a_bits_data[24]
  PIN auto_buffer_out_a_bits_data[25]
    DIRECTION OUTPUT TRISTATE ;
    USE SIGNAL ;
    ANTENNADIFFAREA 0.340600 ;
    PORT
      LAYER met3 ;
        RECT 0.000 2329.040 4.000 2329.640 ;
    END
  END auto_buffer_out_a_bits_data[25]
  PIN auto_buffer_out_a_bits_data[26]
    DIRECTION OUTPUT TRISTATE ;
    USE SIGNAL ;
    ANTENNADIFFAREA 0.340600 ;
    PORT
      LAYER met2 ;
        RECT 4356.750 0.000 4357.030 4.000 ;
    END
  END auto_buffer_out_a_bits_data[26]
  PIN auto_buffer_out_a_bits_data[27]
    DIRECTION OUTPUT TRISTATE ;
    USE SIGNAL ;
    ANTENNADIFFAREA 0.340600 ;
    PORT
      LAYER met2 ;
        RECT 3583.950 0.000 3584.230 4.000 ;
    END
  END auto_buffer_out_a_bits_data[27]
  PIN auto_buffer_out_a_bits_data[28]
    DIRECTION OUTPUT TRISTATE ;
    USE SIGNAL ;
    ANTENNADIFFAREA 0.340600 ;
    PORT
      LAYER met2 ;
        RECT 5148.870 2596.000 5149.150 2600.000 ;
    END
  END auto_buffer_out_a_bits_data[28]
  PIN auto_buffer_out_a_bits_data[29]
    DIRECTION OUTPUT TRISTATE ;
    USE SIGNAL ;
    ANTENNADIFFAREA 0.340600 ;
    PORT
      LAYER met2 ;
        RECT 6758.870 0.000 6759.150 4.000 ;
    END
  END auto_buffer_out_a_bits_data[29]
  PIN auto_buffer_out_a_bits_data[2]
    DIRECTION OUTPUT TRISTATE ;
    USE SIGNAL ;
    ANTENNADIFFAREA 0.340600 ;
    PORT
      LAYER met2 ;
        RECT 3142.810 0.000 3143.090 4.000 ;
    END
  END auto_buffer_out_a_bits_data[2]
  PIN auto_buffer_out_a_bits_data[30]
    DIRECTION OUTPUT TRISTATE ;
    USE SIGNAL ;
    ANTENNADIFFAREA 0.340600 ;
    PORT
      LAYER met2 ;
        RECT 4295.570 2596.000 4295.850 2600.000 ;
    END
  END auto_buffer_out_a_bits_data[30]
  PIN auto_buffer_out_a_bits_data[31]
    DIRECTION OUTPUT TRISTATE ;
    USE SIGNAL ;
    ANTENNADIFFAREA 0.340600 ;
    PORT
      LAYER met2 ;
        RECT 660.190 0.000 660.470 4.000 ;
    END
  END auto_buffer_out_a_bits_data[31]
  PIN auto_buffer_out_a_bits_data[32]
    DIRECTION OUTPUT TRISTATE ;
    USE SIGNAL ;
    ANTENNADIFFAREA 0.340600 ;
    PORT
      LAYER met2 ;
        RECT 5599.670 0.000 5599.950 4.000 ;
    END
  END auto_buffer_out_a_bits_data[32]
  PIN auto_buffer_out_a_bits_data[33]
    DIRECTION OUTPUT TRISTATE ;
    USE SIGNAL ;
    ANTENNADIFFAREA 0.340600 ;
    PORT
      LAYER met2 ;
        RECT 5377.490 0.000 5377.770 4.000 ;
    END
  END auto_buffer_out_a_bits_data[33]
  PIN auto_buffer_out_a_bits_data[34]
    DIRECTION OUTPUT TRISTATE ;
    USE SIGNAL ;
    ANTENNADIFFAREA 0.340600 ;
    PORT
      LAYER met2 ;
        RECT 6205.030 0.000 6205.310 4.000 ;
    END
  END auto_buffer_out_a_bits_data[34]
  PIN auto_buffer_out_a_bits_data[35]
    DIRECTION OUTPUT TRISTATE ;
    USE SIGNAL ;
    ANTENNADIFFAREA 0.340600 ;
    PORT
      LAYER met3 ;
        RECT 6996.000 2220.240 7000.000 2220.840 ;
    END
  END auto_buffer_out_a_bits_data[35]
  PIN auto_buffer_out_a_bits_data[36]
    DIRECTION OUTPUT TRISTATE ;
    USE SIGNAL ;
    ANTENNADIFFAREA 0.340600 ;
    PORT
      LAYER met3 ;
        RECT 6996.000 442.040 7000.000 442.640 ;
    END
  END auto_buffer_out_a_bits_data[36]
  PIN auto_buffer_out_a_bits_data[37]
    DIRECTION OUTPUT TRISTATE ;
    USE SIGNAL ;
    ANTENNADIFFAREA 0.340600 ;
    PORT
      LAYER met2 ;
        RECT 3081.630 2596.000 3081.910 2600.000 ;
    END
  END auto_buffer_out_a_bits_data[37]
  PIN auto_buffer_out_a_bits_data[38]
    DIRECTION OUTPUT TRISTATE ;
    USE SIGNAL ;
    ANTENNADIFFAREA 0.340600 ;
    PORT
      LAYER met2 ;
        RECT 5818.630 0.000 5818.910 4.000 ;
    END
  END auto_buffer_out_a_bits_data[38]
  PIN auto_buffer_out_a_bits_data[39]
    DIRECTION OUTPUT TRISTATE ;
    USE SIGNAL ;
    ANTENNADIFFAREA 0.340600 ;
    PORT
      LAYER met2 ;
        RECT 1149.630 2596.000 1149.910 2600.000 ;
    END
  END auto_buffer_out_a_bits_data[39]
  PIN auto_buffer_out_a_bits_data[3]
    DIRECTION OUTPUT TRISTATE ;
    USE SIGNAL ;
    ANTENNADIFFAREA 0.340600 ;
    PORT
      LAYER met3 ;
        RECT 6996.000 1519.840 7000.000 1520.440 ;
    END
  END auto_buffer_out_a_bits_data[3]
  PIN auto_buffer_out_a_bits_data[40]
    DIRECTION OUTPUT TRISTATE ;
    USE SIGNAL ;
    ANTENNADIFFAREA 0.340600 ;
    PORT
      LAYER met3 ;
        RECT 0.000 1717.040 4.000 1717.640 ;
    END
  END auto_buffer_out_a_bits_data[40]
  PIN auto_buffer_out_a_bits_data[41]
    DIRECTION OUTPUT TRISTATE ;
    USE SIGNAL ;
    ANTENNADIFFAREA 0.340600 ;
    PORT
      LAYER met2 ;
        RECT 293.110 2596.000 293.390 2600.000 ;
    END
  END auto_buffer_out_a_bits_data[41]
  PIN auto_buffer_out_a_bits_data[42]
    DIRECTION OUTPUT TRISTATE ;
    USE SIGNAL ;
    ANTENNADIFFAREA 0.340600 ;
    PORT
      LAYER met3 ;
        RECT 6996.000 561.040 7000.000 561.640 ;
    END
  END auto_buffer_out_a_bits_data[42]
  PIN auto_buffer_out_a_bits_data[43]
    DIRECTION OUTPUT TRISTATE ;
    USE SIGNAL ;
    ANTENNADIFFAREA 0.340600 ;
    PORT
      LAYER met3 ;
        RECT 6996.000 1754.440 7000.000 1755.040 ;
    END
  END auto_buffer_out_a_bits_data[43]
  PIN auto_buffer_out_a_bits_data[44]
    DIRECTION OUTPUT TRISTATE ;
    USE SIGNAL ;
    ANTENNADIFFAREA 0.340600 ;
    PORT
      LAYER met3 ;
        RECT 6996.000 2162.440 7000.000 2163.040 ;
    END
  END auto_buffer_out_a_bits_data[44]
  PIN auto_buffer_out_a_bits_data[45]
    DIRECTION OUTPUT TRISTATE ;
    USE SIGNAL ;
    ANTENNADIFFAREA 0.340600 ;
    PORT
      LAYER met2 ;
        RECT 4569.270 2596.000 4569.550 2600.000 ;
    END
  END auto_buffer_out_a_bits_data[45]
  PIN auto_buffer_out_a_bits_data[46]
    DIRECTION OUTPUT TRISTATE ;
    USE SIGNAL ;
    ANTENNADIFFAREA 0.340600 ;
    PORT
      LAYER met3 ;
        RECT 6996.000 1346.440 7000.000 1347.040 ;
    END
  END auto_buffer_out_a_bits_data[46]
  PIN auto_buffer_out_a_bits_data[47]
    DIRECTION OUTPUT TRISTATE ;
    USE SIGNAL ;
    ANTENNADIFFAREA 0.340600 ;
    PORT
      LAYER met2 ;
        RECT 1046.590 0.000 1046.870 4.000 ;
    END
  END auto_buffer_out_a_bits_data[47]
  PIN auto_buffer_out_a_bits_data[48]
    DIRECTION OUTPUT TRISTATE ;
    USE SIGNAL ;
    ANTENNADIFFAREA 0.340600 ;
    PORT
      LAYER met2 ;
        RECT 2563.210 0.000 2563.490 4.000 ;
    END
  END auto_buffer_out_a_bits_data[48]
  PIN auto_buffer_out_a_bits_data[49]
    DIRECTION OUTPUT TRISTATE ;
    USE SIGNAL ;
    ANTENNADIFFAREA 0.340600 ;
    PORT
      LAYER met2 ;
        RECT 74.150 2596.000 74.430 2600.000 ;
    END
  END auto_buffer_out_a_bits_data[49]
  PIN auto_buffer_out_a_bits_data[4]
    DIRECTION OUTPUT TRISTATE ;
    USE SIGNAL ;
    ANTENNADIFFAREA 0.340600 ;
    PORT
      LAYER met2 ;
        RECT 4791.450 2596.000 4791.730 2600.000 ;
    END
  END auto_buffer_out_a_bits_data[4]
  PIN auto_buffer_out_a_bits_data[50]
    DIRECTION OUTPUT TRISTATE ;
    USE SIGNAL ;
    ANTENNADIFFAREA 0.340600 ;
    PORT
      LAYER met2 ;
        RECT 3136.370 2596.000 3136.650 2600.000 ;
    END
  END auto_buffer_out_a_bits_data[50]
  PIN auto_buffer_out_a_bits_data[51]
    DIRECTION OUTPUT TRISTATE ;
    USE SIGNAL ;
    ANTENNADIFFAREA 0.340600 ;
    PORT
      LAYER met2 ;
        RECT 273.790 0.000 274.070 4.000 ;
    END
  END auto_buffer_out_a_bits_data[51]
  PIN auto_buffer_out_a_bits_data[52]
    DIRECTION OUTPUT TRISTATE ;
    USE SIGNAL ;
    ANTENNADIFFAREA 0.340600 ;
    PORT
      LAYER met2 ;
        RECT 3493.790 2596.000 3494.070 2600.000 ;
    END
  END auto_buffer_out_a_bits_data[52]
  PIN auto_buffer_out_a_bits_data[53]
    DIRECTION OUTPUT TRISTATE ;
    USE SIGNAL ;
    ANTENNADIFFAREA 0.340600 ;
    PORT
      LAYER met2 ;
        RECT 6308.070 2596.000 6308.350 2600.000 ;
    END
  END auto_buffer_out_a_bits_data[53]
  PIN auto_buffer_out_a_bits_data[54]
    DIRECTION OUTPUT TRISTATE ;
    USE SIGNAL ;
    ANTENNADIFFAREA 0.340600 ;
    PORT
      LAYER met2 ;
        RECT 3835.110 0.000 3835.390 4.000 ;
    END
  END auto_buffer_out_a_bits_data[54]
  PIN auto_buffer_out_a_bits_data[55]
    DIRECTION OUTPUT TRISTATE ;
    USE SIGNAL ;
    ANTENNADIFFAREA 0.340600 ;
    PORT
      LAYER met2 ;
        RECT 4578.930 0.000 4579.210 4.000 ;
    END
  END auto_buffer_out_a_bits_data[55]
  PIN auto_buffer_out_a_bits_data[56]
    DIRECTION OUTPUT TRISTATE ;
    USE SIGNAL ;
    ANTENNADIFFAREA 0.340600 ;
    PORT
      LAYER met2 ;
        RECT 1214.030 0.000 1214.310 4.000 ;
    END
  END auto_buffer_out_a_bits_data[56]
  PIN auto_buffer_out_a_bits_data[57]
    DIRECTION OUTPUT TRISTATE ;
    USE SIGNAL ;
    ANTENNADIFFAREA 0.340600 ;
    PORT
      LAYER met2 ;
        RECT 2254.090 2596.000 2254.370 2600.000 ;
    END
  END auto_buffer_out_a_bits_data[57]
  PIN auto_buffer_out_a_bits_data[58]
    DIRECTION OUTPUT TRISTATE ;
    USE SIGNAL ;
    ANTENNADIFFAREA 0.340600 ;
    PORT
      LAYER met2 ;
        RECT 4276.250 0.000 4276.530 4.000 ;
    END
  END auto_buffer_out_a_bits_data[58]
  PIN auto_buffer_out_a_bits_data[59]
    DIRECTION OUTPUT TRISTATE ;
    USE SIGNAL ;
    ANTENNADIFFAREA 0.340600 ;
    PORT
      LAYER met3 ;
        RECT 0.000 2359.640 4.000 2360.240 ;
    END
  END auto_buffer_out_a_bits_data[59]
  PIN auto_buffer_out_a_bits_data[5]
    DIRECTION OUTPUT TRISTATE ;
    USE SIGNAL ;
    ANTENNADIFFAREA 0.340600 ;
    PORT
      LAYER met2 ;
        RECT 1371.810 2596.000 1372.090 2600.000 ;
    END
  END auto_buffer_out_a_bits_data[5]
  PIN auto_buffer_out_a_bits_data[60]
    DIRECTION OUTPUT TRISTATE ;
    USE SIGNAL ;
    ANTENNADIFFAREA 0.340600 ;
    PORT
      LAYER met2 ;
        RECT 5406.470 0.000 5406.750 4.000 ;
    END
  END auto_buffer_out_a_bits_data[60]
  PIN auto_buffer_out_a_bits_data[61]
    DIRECTION OUTPUT TRISTATE ;
    USE SIGNAL ;
    ANTENNADIFFAREA 0.340600 ;
    PORT
      LAYER met2 ;
        RECT 5544.930 0.000 5545.210 4.000 ;
    END
  END auto_buffer_out_a_bits_data[61]
  PIN auto_buffer_out_a_bits_data[62]
    DIRECTION OUTPUT TRISTATE ;
    USE SIGNAL ;
    ANTENNADIFFAREA 0.340600 ;
    PORT
      LAYER met3 ;
        RECT 0.000 2386.840 4.000 2387.440 ;
    END
  END auto_buffer_out_a_bits_data[62]
  PIN auto_buffer_out_a_bits_data[63]
    DIRECTION OUTPUT TRISTATE ;
    USE SIGNAL ;
    ANTENNADIFFAREA 0.340600 ;
    PORT
      LAYER met2 ;
        RECT 521.730 0.000 522.010 4.000 ;
    END
  END auto_buffer_out_a_bits_data[63]
  PIN auto_buffer_out_a_bits_data[6]
    DIRECTION OUTPUT TRISTATE ;
    USE SIGNAL ;
    ANTENNADIFFAREA 0.340600 ;
    PORT
      LAYER met3 ;
        RECT 6996.000 2278.040 7000.000 2278.640 ;
    END
  END auto_buffer_out_a_bits_data[6]
  PIN auto_buffer_out_a_bits_data[7]
    DIRECTION OUTPUT TRISTATE ;
    USE SIGNAL ;
    ANTENNADIFFAREA 0.340600 ;
    PORT
      LAYER met3 ;
        RECT 6996.000 1812.240 7000.000 1812.840 ;
    END
  END auto_buffer_out_a_bits_data[7]
  PIN auto_buffer_out_a_bits_data[8]
    DIRECTION OUTPUT TRISTATE ;
    USE SIGNAL ;
    ANTENNADIFFAREA 0.340600 ;
    PORT
      LAYER met2 ;
        RECT 6143.850 2596.000 6144.130 2600.000 ;
    END
  END auto_buffer_out_a_bits_data[8]
  PIN auto_buffer_out_a_bits_data[9]
    DIRECTION OUTPUT TRISTATE ;
    USE SIGNAL ;
    ANTENNADIFFAREA 0.340600 ;
    PORT
      LAYER met2 ;
        RECT 1452.310 2596.000 1452.590 2600.000 ;
    END
  END auto_buffer_out_a_bits_data[9]
  PIN auto_buffer_out_a_bits_mask[0]
    DIRECTION OUTPUT TRISTATE ;
    USE SIGNAL ;
    ANTENNADIFFAREA 0.340600 ;
    PORT
      LAYER met2 ;
        RECT 5242.250 0.000 5242.530 4.000 ;
    END
  END auto_buffer_out_a_bits_mask[0]
  PIN auto_buffer_out_a_bits_mask[1]
    DIRECTION OUTPUT TRISTATE ;
    USE SIGNAL ;
    ANTENNADIFFAREA 0.340600 ;
    PORT
      LAYER met2 ;
        RECT 5757.450 2596.000 5757.730 2600.000 ;
    END
  END auto_buffer_out_a_bits_mask[1]
  PIN auto_buffer_out_a_bits_mask[2]
    DIRECTION OUTPUT TRISTATE ;
    USE SIGNAL ;
    ANTENNADIFFAREA 0.340600 ;
    PORT
      LAYER met2 ;
        RECT 6916.650 2596.000 6916.930 2600.000 ;
    END
  END auto_buffer_out_a_bits_mask[2]
  PIN auto_buffer_out_a_bits_mask[3]
    DIRECTION OUTPUT TRISTATE ;
    USE SIGNAL ;
    ANTENNADIFFAREA 0.340600 ;
    PORT
      LAYER met2 ;
        RECT 3915.610 0.000 3915.890 4.000 ;
    END
  END auto_buffer_out_a_bits_mask[3]
  PIN auto_buffer_out_a_bits_mask[4]
    DIRECTION OUTPUT TRISTATE ;
    USE SIGNAL ;
    ANTENNADIFFAREA 0.340600 ;
    PORT
      LAYER met2 ;
        RECT 5515.950 0.000 5516.230 4.000 ;
    END
  END auto_buffer_out_a_bits_mask[4]
  PIN auto_buffer_out_a_bits_mask[5]
    DIRECTION OUTPUT TRISTATE ;
    USE SIGNAL ;
    ANTENNADIFFAREA 0.340600 ;
    PORT
      LAYER met3 ;
        RECT 6996.000 1462.040 7000.000 1462.640 ;
    END
  END auto_buffer_out_a_bits_mask[5]
  PIN auto_buffer_out_a_bits_mask[6]
    DIRECTION OUTPUT TRISTATE ;
    USE SIGNAL ;
    ANTENNADIFFAREA 0.340600 ;
    PORT
      LAYER met3 ;
        RECT 6996.000 1200.240 7000.000 1200.840 ;
    END
  END auto_buffer_out_a_bits_mask[6]
  PIN auto_buffer_out_a_bits_mask[7]
    DIRECTION OUTPUT TRISTATE ;
    USE SIGNAL ;
    ANTENNADIFFAREA 0.340600 ;
    PORT
      LAYER met3 ;
        RECT 0.000 2240.640 4.000 2241.240 ;
    END
  END auto_buffer_out_a_bits_mask[7]
  PIN auto_buffer_out_a_bits_opcode[0]
    DIRECTION OUTPUT TRISTATE ;
    USE SIGNAL ;
    ANTENNADIFFAREA 0.340600 ;
    PORT
      LAYER met2 ;
        RECT 5206.830 2596.000 5207.110 2600.000 ;
    END
  END auto_buffer_out_a_bits_opcode[0]
  PIN auto_buffer_out_a_bits_opcode[1]
    DIRECTION OUTPUT TRISTATE ;
    USE SIGNAL ;
    ANTENNADIFFAREA 0.340600 ;
    PORT
      LAYER met2 ;
        RECT 5618.990 2596.000 5619.270 2600.000 ;
    END
  END auto_buffer_out_a_bits_opcode[1]
  PIN auto_buffer_out_a_bits_opcode[2]
    DIRECTION OUTPUT TRISTATE ;
    USE SIGNAL ;
    ANTENNADIFFAREA 0.340600 ;
    PORT
      LAYER met2 ;
        RECT 2537.450 0.000 2537.730 4.000 ;
    END
  END auto_buffer_out_a_bits_opcode[2]
  PIN auto_buffer_out_a_bits_param[0]
    DIRECTION OUTPUT TRISTATE ;
    USE SIGNAL ;
    ANTENNADIFFAREA 0.340600 ;
    PORT
      LAYER met3 ;
        RECT 0.000 2094.440 4.000 2095.040 ;
    END
  END auto_buffer_out_a_bits_param[0]
  PIN auto_buffer_out_a_bits_param[1]
    DIRECTION OUTPUT TRISTATE ;
    USE SIGNAL ;
    ANTENNADIFFAREA 0.340600 ;
    PORT
      LAYER met2 ;
        RECT 3558.190 0.000 3558.470 4.000 ;
    END
  END auto_buffer_out_a_bits_param[1]
  PIN auto_buffer_out_a_bits_param[2]
    DIRECTION OUTPUT TRISTATE ;
    USE SIGNAL ;
    ANTENNADIFFAREA 0.340600 ;
    PORT
      LAYER met2 ;
        RECT 853.390 0.000 853.670 4.000 ;
    END
  END auto_buffer_out_a_bits_param[2]
  PIN auto_buffer_out_a_bits_size[0]
    DIRECTION OUTPUT TRISTATE ;
    USE SIGNAL ;
    ANTENNADIFFAREA 0.340600 ;
    PORT
      LAYER met2 ;
        RECT 872.710 2596.000 872.990 2600.000 ;
    END
  END auto_buffer_out_a_bits_size[0]
  PIN auto_buffer_out_a_bits_size[1]
    DIRECTION OUTPUT TRISTATE ;
    USE SIGNAL ;
    ANTENNADIFFAREA 0.340600 ;
    PORT
      LAYER met2 ;
        RECT 2006.150 2596.000 2006.430 2600.000 ;
    END
  END auto_buffer_out_a_bits_size[1]
  PIN auto_buffer_out_a_bits_size[2]
    DIRECTION OUTPUT TRISTATE ;
    USE SIGNAL ;
    ANTENNADIFFAREA 0.340600 ;
    PORT
      LAYER met2 ;
        RECT 466.990 0.000 467.270 4.000 ;
    END
  END auto_buffer_out_a_bits_size[2]
  PIN auto_buffer_out_a_bits_size[3]
    DIRECTION OUTPUT TRISTATE ;
    USE SIGNAL ;
    PORT
      LAYER met2 ;
        RECT 5177.850 2596.000 5178.130 2600.000 ;
    END
  END auto_buffer_out_a_bits_size[3]
  PIN auto_buffer_out_a_bits_source[0]
    DIRECTION OUTPUT TRISTATE ;
    USE SIGNAL ;
    ANTENNADIFFAREA 0.340600 ;
    PORT
      LAYER met3 ;
        RECT 0.000 639.240 4.000 639.840 ;
    END
  END auto_buffer_out_a_bits_source[0]
  PIN auto_buffer_out_a_bits_source[1]
    DIRECTION OUTPUT TRISTATE ;
    USE SIGNAL ;
    ANTENNADIFFAREA 0.340600 ;
    PORT
      LAYER met2 ;
        RECT 2334.590 2596.000 2334.870 2600.000 ;
    END
  END auto_buffer_out_a_bits_source[1]
  PIN auto_buffer_out_a_ready
    DIRECTION INPUT ;
    USE SIGNAL ;
    ANTENNAGATEAREA 0.990000 ;
    PORT
      LAYER met2 ;
        RECT 3770.710 2596.000 3770.990 2600.000 ;
    END
  END auto_buffer_out_a_ready
  PIN auto_buffer_out_a_valid
    DIRECTION OUTPUT TRISTATE ;
    USE SIGNAL ;
    ANTENNADIFFAREA 0.340600 ;
    PORT
      LAYER met2 ;
        RECT 5763.890 0.000 5764.170 4.000 ;
    END
  END auto_buffer_out_a_valid
  PIN auto_buffer_out_b_bits_address[0]
    DIRECTION INPUT ;
    USE SIGNAL ;
    ANTENNAGATEAREA 0.990000 ;
    PORT
      LAYER met2 ;
        RECT 3026.890 2596.000 3027.170 2600.000 ;
    END
  END auto_buffer_out_b_bits_address[0]
  PIN auto_buffer_out_b_bits_address[10]
    DIRECTION INPUT ;
    USE SIGNAL ;
    ANTENNAGATEAREA 0.990000 ;
    PORT
      LAYER met2 ;
        RECT 3548.530 2596.000 3548.810 2600.000 ;
    END
  END auto_buffer_out_b_bits_address[10]
  PIN auto_buffer_out_b_bits_address[11]
    DIRECTION INPUT ;
    USE SIGNAL ;
    ANTENNAGATEAREA 0.990000 ;
    PORT
      LAYER met2 ;
        RECT 6253.330 2596.000 6253.610 2600.000 ;
    END
  END auto_buffer_out_b_bits_address[11]
  PIN auto_buffer_out_b_bits_address[12]
    DIRECTION INPUT ;
    USE SIGNAL ;
    ANTENNAGATEAREA 0.990000 ;
    PORT
      LAYER met2 ;
        RECT 128.890 2596.000 129.170 2600.000 ;
    END
  END auto_buffer_out_b_bits_address[12]
  PIN auto_buffer_out_b_bits_address[13]
    DIRECTION INPUT ;
    USE SIGNAL ;
    ANTENNAGATEAREA 0.990000 ;
    PORT
      LAYER met2 ;
        RECT 5673.730 2596.000 5674.010 2600.000 ;
    END
  END auto_buffer_out_b_bits_address[13]
  PIN auto_buffer_out_b_bits_address[14]
    DIRECTION INPUT ;
    USE SIGNAL ;
    ANTENNAGATEAREA 0.990000 ;
    PORT
      LAYER met2 ;
        RECT 1313.850 2596.000 1314.130 2600.000 ;
    END
  END auto_buffer_out_b_bits_address[14]
  PIN auto_buffer_out_b_bits_address[15]
    DIRECTION INPUT ;
    USE SIGNAL ;
    ANTENNAGATEAREA 0.990000 ;
    PORT
      LAYER met2 ;
        RECT 1011.170 2596.000 1011.450 2600.000 ;
    END
  END auto_buffer_out_b_bits_address[15]
  PIN auto_buffer_out_b_bits_address[16]
    DIRECTION INPUT ;
    USE SIGNAL ;
    ANTENNAGATEAREA 0.990000 ;
    PORT
      LAYER met3 ;
        RECT 0.000 465.840 4.000 466.440 ;
    END
  END auto_buffer_out_b_bits_address[16]
  PIN auto_buffer_out_b_bits_address[17]
    DIRECTION INPUT ;
    USE SIGNAL ;
    ANTENNAGATEAREA 0.990000 ;
    PORT
      LAYER met2 ;
        RECT 164.310 0.000 164.590 4.000 ;
    END
  END auto_buffer_out_b_bits_address[17]
  PIN auto_buffer_out_b_bits_address[18]
    DIRECTION INPUT ;
    USE SIGNAL ;
    ANTENNAGATEAREA 0.990000 ;
    PORT
      LAYER met3 ;
        RECT 6996.000 1958.440 7000.000 1959.040 ;
    END
  END auto_buffer_out_b_bits_address[18]
  PIN auto_buffer_out_b_bits_address[19]
    DIRECTION INPUT ;
    USE SIGNAL ;
    ANTENNAGATEAREA 0.990000 ;
    PORT
      LAYER met2 ;
        RECT 1404.010 0.000 1404.290 4.000 ;
    END
  END auto_buffer_out_b_bits_address[19]
  PIN auto_buffer_out_b_bits_address[1]
    DIRECTION INPUT ;
    USE SIGNAL ;
    ANTENNAGATEAREA 0.990000 ;
    PORT
      LAYER met2 ;
        RECT 322.090 2596.000 322.370 2600.000 ;
    END
  END auto_buffer_out_b_bits_address[1]
  PIN auto_buffer_out_b_bits_address[20]
    DIRECTION INPUT ;
    USE SIGNAL ;
    ANTENNAGATEAREA 0.990000 ;
    PORT
      LAYER met3 ;
        RECT 0.000 1951.640 4.000 1952.240 ;
    END
  END auto_buffer_out_b_bits_address[20]
  PIN auto_buffer_out_b_bits_address[21]
    DIRECTION INPUT ;
    USE SIGNAL ;
    ANTENNAGATEAREA 0.990000 ;
    PORT
      LAYER met2 ;
        RECT 2344.250 0.000 2344.530 4.000 ;
    END
  END auto_buffer_out_b_bits_address[21]
  PIN auto_buffer_out_b_bits_address[22]
    DIRECTION INPUT ;
    USE SIGNAL ;
    ANTENNAGATEAREA 0.990000 ;
    PORT
      LAYER met2 ;
        RECT 763.230 2596.000 763.510 2600.000 ;
    END
  END auto_buffer_out_b_bits_address[22]
  PIN auto_buffer_out_b_bits_address[23]
    DIRECTION INPUT ;
    USE SIGNAL ;
    ANTENNAGATEAREA 0.990000 ;
    PORT
      LAYER met2 ;
        RECT 3191.110 2596.000 3191.390 2600.000 ;
    END
  END auto_buffer_out_b_bits_address[23]
  PIN auto_buffer_out_b_bits_address[24]
    DIRECTION INPUT ;
    USE SIGNAL ;
    ANTENNAGATEAREA 0.990000 ;
    PORT
      LAYER met2 ;
        RECT 4018.650 2596.000 4018.930 2600.000 ;
    END
  END auto_buffer_out_b_bits_address[24]
  PIN auto_buffer_out_b_bits_address[25]
    DIRECTION INPUT ;
    USE SIGNAL ;
    ANTENNAGATEAREA 0.990000 ;
    PORT
      LAYER met2 ;
        RECT 1874.130 0.000 1874.410 4.000 ;
    END
  END auto_buffer_out_b_bits_address[25]
  PIN auto_buffer_out_b_bits_address[26]
    DIRECTION INPUT ;
    USE SIGNAL ;
    ANTENNAGATEAREA 0.990000 ;
    PORT
      LAYER met2 ;
        RECT 3107.390 2596.000 3107.670 2600.000 ;
    END
  END auto_buffer_out_b_bits_address[26]
  PIN auto_buffer_out_b_bits_address[27]
    DIRECTION INPUT ;
    USE SIGNAL ;
    ANTENNAGATEAREA 0.990000 ;
    PORT
      LAYER met3 ;
        RECT 6996.000 2424.240 7000.000 2424.840 ;
    END
  END auto_buffer_out_b_bits_address[27]
  PIN auto_buffer_out_b_bits_address[28]
    DIRECTION INPUT ;
    USE SIGNAL ;
    ANTENNAGATEAREA 0.990000 ;
    PORT
      LAYER met3 ;
        RECT 6996.000 676.640 7000.000 677.240 ;
    END
  END auto_buffer_out_b_bits_address[28]
  PIN auto_buffer_out_b_bits_address[29]
    DIRECTION INPUT ;
    USE SIGNAL ;
    ANTENNAGATEAREA 0.990000 ;
    PORT
      LAYER met2 ;
        RECT 2778.950 2596.000 2779.230 2600.000 ;
    END
  END auto_buffer_out_b_bits_address[29]
  PIN auto_buffer_out_b_bits_address[2]
    DIRECTION INPUT ;
    USE SIGNAL ;
    ANTENNAGATEAREA 0.426000 ;
    PORT
      LAYER met2 ;
        RECT 6784.630 0.000 6784.910 4.000 ;
    END
  END auto_buffer_out_b_bits_address[2]
  PIN auto_buffer_out_b_bits_address[30]
    DIRECTION INPUT ;
    USE SIGNAL ;
    ANTENNAGATEAREA 0.990000 ;
    PORT
      LAYER met2 ;
        RECT 3390.750 0.000 3391.030 4.000 ;
    END
  END auto_buffer_out_b_bits_address[30]
  PIN auto_buffer_out_b_bits_address[31]
    DIRECTION INPUT ;
    USE SIGNAL ;
    ANTENNAGATEAREA 0.990000 ;
    PORT
      LAYER met2 ;
        RECT 6398.230 0.000 6398.510 4.000 ;
    END
  END auto_buffer_out_b_bits_address[31]
  PIN auto_buffer_out_b_bits_address[3]
    DIRECTION INPUT ;
    USE SIGNAL ;
    ANTENNAGATEAREA 0.990000 ;
    PORT
      LAYER met3 ;
        RECT 6996.000 996.240 7000.000 996.840 ;
    END
  END auto_buffer_out_b_bits_address[3]
  PIN auto_buffer_out_b_bits_address[4]
    DIRECTION INPUT ;
    USE SIGNAL ;
    ANTENNAGATEAREA 0.990000 ;
    PORT
      LAYER met2 ;
        RECT 6584.990 2596.000 6585.270 2600.000 ;
    END
  END auto_buffer_out_b_bits_address[4]
  PIN auto_buffer_out_b_bits_address[5]
    DIRECTION INPUT ;
    USE SIGNAL ;
    ANTENNAGATEAREA 0.990000 ;
    PORT
      LAYER met2 ;
        RECT 1120.650 2596.000 1120.930 2600.000 ;
    END
  END auto_buffer_out_b_bits_address[5]
  PIN auto_buffer_out_b_bits_address[6]
    DIRECTION INPUT ;
    USE SIGNAL ;
    ANTENNAGATEAREA 0.990000 ;
    PORT
      LAYER met3 ;
        RECT 6996.000 1900.640 7000.000 1901.240 ;
    END
  END auto_buffer_out_b_bits_address[6]
  PIN auto_buffer_out_b_bits_address[7]
    DIRECTION INPUT ;
    USE SIGNAL ;
    ANTENNAGATEAREA 0.990000 ;
    PORT
      LAYER met2 ;
        RECT 6337.050 2596.000 6337.330 2600.000 ;
    END
  END auto_buffer_out_b_bits_address[7]
  PIN auto_buffer_out_b_bits_address[8]
    DIRECTION INPUT ;
    USE SIGNAL ;
    ANTENNAGATEAREA 0.990000 ;
    PORT
      LAYER met3 ;
        RECT 6996.000 1084.640 7000.000 1085.240 ;
    END
  END auto_buffer_out_b_bits_address[8]
  PIN auto_buffer_out_b_bits_address[9]
    DIRECTION INPUT ;
    USE SIGNAL ;
    ANTENNAGATEAREA 0.990000 ;
    PORT
      LAYER met2 ;
        RECT 6694.470 2596.000 6694.750 2600.000 ;
    END
  END auto_buffer_out_b_bits_address[9]
  PIN auto_buffer_out_b_bits_corrupt
    DIRECTION INPUT ;
    USE SIGNAL ;
    PORT
      LAYER met2 ;
        RECT 1178.610 2596.000 1178.890 2600.000 ;
    END
  END auto_buffer_out_b_bits_corrupt
  PIN auto_buffer_out_b_bits_data[0]
    DIRECTION INPUT ;
    USE SIGNAL ;
    PORT
      LAYER met2 ;
        RECT 2585.750 2596.000 2586.030 2600.000 ;
    END
  END auto_buffer_out_b_bits_data[0]
  PIN auto_buffer_out_b_bits_data[10]
    DIRECTION INPUT ;
    USE SIGNAL ;
    PORT
      LAYER met2 ;
        RECT 5728.470 2596.000 5728.750 2600.000 ;
    END
  END auto_buffer_out_b_bits_data[10]
  PIN auto_buffer_out_b_bits_data[11]
    DIRECTION INPUT ;
    USE SIGNAL ;
    PORT
      LAYER met2 ;
        RECT 5068.370 2596.000 5068.650 2600.000 ;
    END
  END auto_buffer_out_b_bits_data[11]
  PIN auto_buffer_out_b_bits_data[12]
    DIRECTION INPUT ;
    USE SIGNAL ;
    PORT
      LAYER met3 ;
        RECT 6996.000 880.640 7000.000 881.240 ;
    END
  END auto_buffer_out_b_bits_data[12]
  PIN auto_buffer_out_b_bits_data[13]
    DIRECTION INPUT ;
    USE SIGNAL ;
    PORT
      LAYER met2 ;
        RECT 3171.790 0.000 3172.070 4.000 ;
    END
  END auto_buffer_out_b_bits_data[13]
  PIN auto_buffer_out_b_bits_data[14]
    DIRECTION INPUT ;
    USE SIGNAL ;
    PORT
      LAYER met3 ;
        RECT 0.000 2533.040 4.000 2533.640 ;
    END
  END auto_buffer_out_b_bits_data[14]
  PIN auto_buffer_out_b_bits_data[15]
    DIRECTION INPUT ;
    USE SIGNAL ;
    PORT
      LAYER met2 ;
        RECT 2225.110 2596.000 2225.390 2600.000 ;
    END
  END auto_buffer_out_b_bits_data[15]
  PIN auto_buffer_out_b_bits_data[16]
    DIRECTION INPUT ;
    USE SIGNAL ;
    PORT
      LAYER met2 ;
        RECT 1268.770 0.000 1269.050 4.000 ;
    END
  END auto_buffer_out_b_bits_data[16]
  PIN auto_buffer_out_b_bits_data[17]
    DIRECTION INPUT ;
    USE SIGNAL ;
    PORT
      LAYER met2 ;
        RECT 6977.830 0.000 6978.110 4.000 ;
    END
  END auto_buffer_out_b_bits_data[17]
  PIN auto_buffer_out_b_bits_data[18]
    DIRECTION INPUT ;
    USE SIGNAL ;
    PORT
      LAYER met3 ;
        RECT 0.000 1890.440 4.000 1891.040 ;
    END
  END auto_buffer_out_b_bits_data[18]
  PIN auto_buffer_out_b_bits_data[19]
    DIRECTION INPUT ;
    USE SIGNAL ;
    PORT
      LAYER met2 ;
        RECT 4128.130 2596.000 4128.410 2600.000 ;
    END
  END auto_buffer_out_b_bits_data[19]
  PIN auto_buffer_out_b_bits_data[1]
    DIRECTION INPUT ;
    USE SIGNAL ;
    PORT
      LAYER met2 ;
        RECT 5921.670 2596.000 5921.950 2600.000 ;
    END
  END auto_buffer_out_b_bits_data[1]
  PIN auto_buffer_out_b_bits_data[20]
    DIRECTION INPUT ;
    USE SIGNAL ;
    PORT
      LAYER met3 ;
        RECT 6996.000 1666.040 7000.000 1666.640 ;
    END
  END auto_buffer_out_b_bits_data[20]
  PIN auto_buffer_out_b_bits_data[21]
    DIRECTION INPUT ;
    USE SIGNAL ;
    PORT
      LAYER met2 ;
        RECT 3033.330 0.000 3033.610 4.000 ;
    END
  END auto_buffer_out_b_bits_data[21]
  PIN auto_buffer_out_b_bits_data[22]
    DIRECTION INPUT ;
    USE SIGNAL ;
    PORT
      LAYER met3 ;
        RECT 6996.000 588.240 7000.000 588.840 ;
    END
  END auto_buffer_out_b_bits_data[22]
  PIN auto_buffer_out_b_bits_data[23]
    DIRECTION INPUT ;
    USE SIGNAL ;
    PORT
      LAYER met2 ;
        RECT 3220.090 2596.000 3220.370 2600.000 ;
    END
  END auto_buffer_out_b_bits_data[23]
  PIN auto_buffer_out_b_bits_data[24]
    DIRECTION INPUT ;
    USE SIGNAL ;
    PORT
      LAYER met2 ;
        RECT 441.230 0.000 441.510 4.000 ;
    END
  END auto_buffer_out_b_bits_data[24]
  PIN auto_buffer_out_b_bits_data[25]
    DIRECTION INPUT ;
    USE SIGNAL ;
    PORT
      LAYER met2 ;
        RECT 302.770 0.000 303.050 4.000 ;
    END
  END auto_buffer_out_b_bits_data[25]
  PIN auto_buffer_out_b_bits_data[26]
    DIRECTION INPUT ;
    USE SIGNAL ;
    PORT
      LAYER met2 ;
        RECT 5625.430 0.000 5625.710 4.000 ;
    END
  END auto_buffer_out_b_bits_data[26]
  PIN auto_buffer_out_b_bits_data[27]
    DIRECTION INPUT ;
    USE SIGNAL ;
    PORT
      LAYER met2 ;
        RECT 1507.050 2596.000 1507.330 2600.000 ;
    END
  END auto_buffer_out_b_bits_data[27]
  PIN auto_buffer_out_b_bits_data[28]
    DIRECTION INPUT ;
    USE SIGNAL ;
    PORT
      LAYER met2 ;
        RECT 4376.070 2596.000 4376.350 2600.000 ;
    END
  END auto_buffer_out_b_bits_data[28]
  PIN auto_buffer_out_b_bits_data[29]
    DIRECTION INPUT ;
    USE SIGNAL ;
    PORT
      LAYER met3 ;
        RECT 0.000 2271.240 4.000 2271.840 ;
    END
  END auto_buffer_out_b_bits_data[29]
  PIN auto_buffer_out_b_bits_data[2]
    DIRECTION INPUT ;
    USE SIGNAL ;
    PORT
      LAYER met2 ;
        RECT 6813.610 0.000 6813.890 4.000 ;
    END
  END auto_buffer_out_b_bits_data[2]
  PIN auto_buffer_out_b_bits_data[30]
    DIRECTION INPUT ;
    USE SIGNAL ;
    PORT
      LAYER met2 ;
        RECT 1903.110 0.000 1903.390 4.000 ;
    END
  END auto_buffer_out_b_bits_data[30]
  PIN auto_buffer_out_b_bits_data[31]
    DIRECTION INPUT ;
    USE SIGNAL ;
    PORT
      LAYER met2 ;
        RECT 2675.910 0.000 2676.190 4.000 ;
    END
  END auto_buffer_out_b_bits_data[31]
  PIN auto_buffer_out_b_bits_data[32]
    DIRECTION INPUT ;
    USE SIGNAL ;
    PORT
      LAYER met2 ;
        RECT 6778.190 2596.000 6778.470 2600.000 ;
    END
  END auto_buffer_out_b_bits_data[32]
  PIN auto_buffer_out_b_bits_data[33]
    DIRECTION INPUT ;
    USE SIGNAL ;
    PORT
      LAYER met2 ;
        RECT 6060.130 2596.000 6060.410 2600.000 ;
    END
  END auto_buffer_out_b_bits_data[33]
  PIN auto_buffer_out_b_bits_data[34]
    DIRECTION INPUT ;
    USE SIGNAL ;
    PORT
      LAYER met2 ;
        RECT 2370.010 0.000 2370.290 4.000 ;
    END
  END auto_buffer_out_b_bits_data[34]
  PIN auto_buffer_out_b_bits_data[35]
    DIRECTION INPUT ;
    USE SIGNAL ;
    PORT
      LAYER met2 ;
        RECT 2060.890 2596.000 2061.170 2600.000 ;
    END
  END auto_buffer_out_b_bits_data[35]
  PIN auto_buffer_out_b_bits_data[36]
    DIRECTION INPUT ;
    USE SIGNAL ;
    PORT
      LAYER met2 ;
        RECT 4350.310 2596.000 4350.590 2600.000 ;
    END
  END auto_buffer_out_b_bits_data[36]
  PIN auto_buffer_out_b_bits_data[37]
    DIRECTION INPUT ;
    USE SIGNAL ;
    PORT
      LAYER met3 ;
        RECT 0.000 2590.840 4.000 2591.440 ;
    END
  END auto_buffer_out_b_bits_data[37]
  PIN auto_buffer_out_b_bits_data[38]
    DIRECTION INPUT ;
    USE SIGNAL ;
    PORT
      LAYER met2 ;
        RECT 937.110 0.000 937.390 4.000 ;
    END
  END auto_buffer_out_b_bits_data[38]
  PIN auto_buffer_out_b_bits_data[39]
    DIRECTION INPUT ;
    USE SIGNAL ;
    PORT
      LAYER met2 ;
        RECT 4984.650 2596.000 4984.930 2600.000 ;
    END
  END auto_buffer_out_b_bits_data[39]
  PIN auto_buffer_out_b_bits_data[3]
    DIRECTION INPUT ;
    USE SIGNAL ;
    PORT
      LAYER met2 ;
        RECT 1645.510 2596.000 1645.790 2600.000 ;
    END
  END auto_buffer_out_b_bits_data[3]
  PIN auto_buffer_out_b_bits_data[40]
    DIRECTION INPUT ;
    USE SIGNAL ;
    PORT
      LAYER met2 ;
        RECT 4211.850 2596.000 4212.130 2600.000 ;
    END
  END auto_buffer_out_b_bits_data[40]
  PIN auto_buffer_out_b_bits_data[41]
    DIRECTION INPUT ;
    USE SIGNAL ;
    PORT
      LAYER met2 ;
        RECT 6832.930 2596.000 6833.210 2600.000 ;
    END
  END auto_buffer_out_b_bits_data[41]
  PIN auto_buffer_out_b_bits_data[42]
    DIRECTION INPUT ;
    USE SIGNAL ;
    PORT
      LAYER met3 ;
        RECT 6996.000 2512.640 7000.000 2513.240 ;
    END
  END auto_buffer_out_b_bits_data[42]
  PIN auto_buffer_out_b_bits_data[43]
    DIRECTION INPUT ;
    USE SIGNAL ;
    PORT
      LAYER met2 ;
        RECT 5268.010 0.000 5268.290 4.000 ;
    END
  END auto_buffer_out_b_bits_data[43]
  PIN auto_buffer_out_b_bits_data[44]
    DIRECTION INPUT ;
    USE SIGNAL ;
    PORT
      LAYER met2 ;
        RECT 1754.990 2596.000 1755.270 2600.000 ;
    END
  END auto_buffer_out_b_bits_data[44]
  PIN auto_buffer_out_b_bits_data[45]
    DIRECTION INPUT ;
    USE SIGNAL ;
    PORT
      LAYER met2 ;
        RECT 3004.350 0.000 3004.630 4.000 ;
    END
  END auto_buffer_out_b_bits_data[45]
  PIN auto_buffer_out_b_bits_data[46]
    DIRECTION INPUT ;
    USE SIGNAL ;
    PORT
      LAYER met2 ;
        RECT 1729.230 2596.000 1729.510 2600.000 ;
    END
  END auto_buffer_out_b_bits_data[46]
  PIN auto_buffer_out_b_bits_data[47]
    DIRECTION INPUT ;
    USE SIGNAL ;
    PORT
      LAYER met3 ;
        RECT 0.000 1832.640 4.000 1833.240 ;
    END
  END auto_buffer_out_b_bits_data[47]
  PIN auto_buffer_out_b_bits_data[48]
    DIRECTION INPUT ;
    USE SIGNAL ;
    PORT
      LAYER met2 ;
        RECT 2289.510 0.000 2289.790 4.000 ;
    END
  END auto_buffer_out_b_bits_data[48]
  PIN auto_buffer_out_b_bits_data[49]
    DIRECTION INPUT ;
    USE SIGNAL ;
    PORT
      LAYER met2 ;
        RECT 1764.650 0.000 1764.930 4.000 ;
    END
  END auto_buffer_out_b_bits_data[49]
  PIN auto_buffer_out_b_bits_data[4]
    DIRECTION INPUT ;
    USE SIGNAL ;
    PORT
      LAYER met2 ;
        RECT 4991.090 0.000 4991.370 4.000 ;
    END
  END auto_buffer_out_b_bits_data[4]
  PIN auto_buffer_out_b_bits_data[50]
    DIRECTION INPUT ;
    USE SIGNAL ;
    PORT
      LAYER met2 ;
        RECT 4047.630 2596.000 4047.910 2600.000 ;
    END
  END auto_buffer_out_b_bits_data[50]
  PIN auto_buffer_out_b_bits_data[51]
    DIRECTION INPUT ;
    USE SIGNAL ;
    PORT
      LAYER met2 ;
        RECT 80.590 0.000 80.870 4.000 ;
    END
  END auto_buffer_out_b_bits_data[51]
  PIN auto_buffer_out_b_bits_data[52]
    DIRECTION INPUT ;
    USE SIGNAL ;
    PORT
      LAYER met3 ;
        RECT 0.000 1397.440 4.000 1398.040 ;
    END
  END auto_buffer_out_b_bits_data[52]
  PIN auto_buffer_out_b_bits_data[53]
    DIRECTION INPUT ;
    USE SIGNAL ;
    PORT
      LAYER met3 ;
        RECT 6996.000 1696.640 7000.000 1697.240 ;
    END
  END auto_buffer_out_b_bits_data[53]
  PIN auto_buffer_out_b_bits_data[54]
    DIRECTION INPUT ;
    USE SIGNAL ;
    PORT
      LAYER met3 ;
        RECT 0.000 1339.640 4.000 1340.240 ;
    END
  END auto_buffer_out_b_bits_data[54]
  PIN auto_buffer_out_b_bits_data[55]
    DIRECTION INPUT ;
    USE SIGNAL ;
    PORT
      LAYER met2 ;
        RECT 817.970 2596.000 818.250 2600.000 ;
    END
  END auto_buffer_out_b_bits_data[55]
  PIN auto_buffer_out_b_bits_data[56]
    DIRECTION INPUT ;
    USE SIGNAL ;
    PORT
      LAYER met3 ;
        RECT 6996.000 1288.640 7000.000 1289.240 ;
    END
  END auto_buffer_out_b_bits_data[56]
  PIN auto_buffer_out_b_bits_data[57]
    DIRECTION INPUT ;
    USE SIGNAL ;
    PORT
      LAYER met2 ;
        RECT 3413.290 2596.000 3413.570 2600.000 ;
    END
  END auto_buffer_out_b_bits_data[57]
  PIN auto_buffer_out_b_bits_data[58]
    DIRECTION INPUT ;
    USE SIGNAL ;
    PORT
      LAYER met2 ;
        RECT 2646.930 0.000 2647.210 4.000 ;
    END
  END auto_buffer_out_b_bits_data[58]
  PIN auto_buffer_out_b_bits_data[59]
    DIRECTION INPUT ;
    USE SIGNAL ;
    PORT
      LAYER met2 ;
        RECT 5322.750 0.000 5323.030 4.000 ;
    END
  END auto_buffer_out_b_bits_data[59]
  PIN auto_buffer_out_b_bits_data[5]
    DIRECTION INPUT ;
    USE SIGNAL ;
    PORT
      LAYER met2 ;
        RECT 2666.250 2596.000 2666.530 2600.000 ;
    END
  END auto_buffer_out_b_bits_data[5]
  PIN auto_buffer_out_b_bits_data[60]
    DIRECTION INPUT ;
    USE SIGNAL ;
    PORT
      LAYER met2 ;
        RECT 3661.230 2596.000 3661.510 2600.000 ;
    END
  END auto_buffer_out_b_bits_data[60]
  PIN auto_buffer_out_b_bits_data[61]
    DIRECTION INPUT ;
    USE SIGNAL ;
    PORT
      LAYER met3 ;
        RECT 0.000 2155.640 4.000 2156.240 ;
    END
  END auto_buffer_out_b_bits_data[61]
  PIN auto_buffer_out_b_bits_data[62]
    DIRECTION INPUT ;
    USE SIGNAL ;
    PORT
      LAYER met2 ;
        RECT 3825.450 2596.000 3825.730 2600.000 ;
    END
  END auto_buffer_out_b_bits_data[62]
  PIN auto_buffer_out_b_bits_data[63]
    DIRECTION INPUT ;
    USE SIGNAL ;
    PORT
      LAYER met2 ;
        RECT 3854.430 2596.000 3854.710 2600.000 ;
    END
  END auto_buffer_out_b_bits_data[63]
  PIN auto_buffer_out_b_bits_data[6]
    DIRECTION INPUT ;
    USE SIGNAL ;
    PORT
      LAYER met2 ;
        RECT 6997.150 2596.000 6997.430 2600.000 ;
    END
  END auto_buffer_out_b_bits_data[6]
  PIN auto_buffer_out_b_bits_data[7]
    DIRECTION INPUT ;
    USE SIGNAL ;
    PORT
      LAYER met2 ;
        RECT 3336.010 0.000 3336.290 4.000 ;
    END
  END auto_buffer_out_b_bits_data[7]
  PIN auto_buffer_out_b_bits_data[8]
    DIRECTION INPUT ;
    USE SIGNAL ;
    PORT
      LAYER met3 ;
        RECT 0.000 550.840 4.000 551.440 ;
    END
  END auto_buffer_out_b_bits_data[8]
  PIN auto_buffer_out_b_bits_data[9]
    DIRECTION INPUT ;
    USE SIGNAL ;
    PORT
      LAYER met2 ;
        RECT 3522.770 2596.000 3523.050 2600.000 ;
    END
  END auto_buffer_out_b_bits_data[9]
  PIN auto_buffer_out_b_bits_mask[0]
    DIRECTION INPUT ;
    USE SIGNAL ;
    PORT
      LAYER met2 ;
        RECT 1094.890 2596.000 1095.170 2600.000 ;
    END
  END auto_buffer_out_b_bits_mask[0]
  PIN auto_buffer_out_b_bits_mask[1]
    DIRECTION INPUT ;
    USE SIGNAL ;
    PORT
      LAYER met2 ;
        RECT 2115.630 2596.000 2115.910 2600.000 ;
    END
  END auto_buffer_out_b_bits_mask[1]
  PIN auto_buffer_out_b_bits_mask[2]
    DIRECTION INPUT ;
    USE SIGNAL ;
    PORT
      LAYER met2 ;
        RECT 1156.070 0.000 1156.350 4.000 ;
    END
  END auto_buffer_out_b_bits_mask[2]
  PIN auto_buffer_out_b_bits_mask[3]
    DIRECTION INPUT ;
    USE SIGNAL ;
    PORT
      LAYER met2 ;
        RECT 6861.910 2596.000 6862.190 2600.000 ;
    END
  END auto_buffer_out_b_bits_mask[3]
  PIN auto_buffer_out_b_bits_mask[4]
    DIRECTION INPUT ;
    USE SIGNAL ;
    PORT
      LAYER met2 ;
        RECT 5783.210 2596.000 5783.490 2600.000 ;
    END
  END auto_buffer_out_b_bits_mask[4]
  PIN auto_buffer_out_b_bits_mask[5]
    DIRECTION INPUT ;
    USE SIGNAL ;
    PORT
      LAYER met2 ;
        RECT 4054.070 0.000 4054.350 4.000 ;
    END
  END auto_buffer_out_b_bits_mask[5]
  PIN auto_buffer_out_b_bits_mask[6]
    DIRECTION INPUT ;
    USE SIGNAL ;
    PORT
      LAYER met3 ;
        RECT 6996.000 822.840 7000.000 823.440 ;
    END
  END auto_buffer_out_b_bits_mask[6]
  PIN auto_buffer_out_b_bits_mask[7]
    DIRECTION INPUT ;
    USE SIGNAL ;
    PORT
      LAYER met2 ;
        RECT 6427.210 0.000 6427.490 4.000 ;
    END
  END auto_buffer_out_b_bits_mask[7]
  PIN auto_buffer_out_b_bits_opcode[0]
    DIRECTION INPUT ;
    USE SIGNAL ;
    PORT
      LAYER met2 ;
        RECT 846.950 2596.000 847.230 2600.000 ;
    END
  END auto_buffer_out_b_bits_opcode[0]
  PIN auto_buffer_out_b_bits_opcode[1]
    DIRECTION INPUT ;
    USE SIGNAL ;
    PORT
      LAYER met2 ;
        RECT 1204.370 2596.000 1204.650 2600.000 ;
    END
  END auto_buffer_out_b_bits_opcode[1]
  PIN auto_buffer_out_b_bits_opcode[2]
    DIRECTION INPUT ;
    USE SIGNAL ;
    PORT
      LAYER met2 ;
        RECT 6749.210 2596.000 6749.490 2600.000 ;
    END
  END auto_buffer_out_b_bits_opcode[2]
  PIN auto_buffer_out_b_bits_param[0]
    DIRECTION INPUT ;
    USE SIGNAL ;
    ANTENNAGATEAREA 0.196500 ;
    PORT
      LAYER met2 ;
        RECT 2418.310 2596.000 2418.590 2600.000 ;
    END
  END auto_buffer_out_b_bits_param[0]
  PIN auto_buffer_out_b_bits_param[1]
    DIRECTION INPUT ;
    USE SIGNAL ;
    ANTENNAGATEAREA 0.990000 ;
    PORT
      LAYER met2 ;
        RECT 4186.090 2596.000 4186.370 2600.000 ;
    END
  END auto_buffer_out_b_bits_param[1]
  PIN auto_buffer_out_b_bits_size[0]
    DIRECTION INPUT ;
    USE SIGNAL ;
    ANTENNAGATEAREA 0.990000 ;
    PORT
      LAYER met2 ;
        RECT 3934.930 2596.000 3935.210 2600.000 ;
    END
  END auto_buffer_out_b_bits_size[0]
  PIN auto_buffer_out_b_bits_size[1]
    DIRECTION INPUT ;
    USE SIGNAL ;
    ANTENNAGATEAREA 0.990000 ;
    PORT
      LAYER met3 ;
        RECT 0.000 2036.640 4.000 2037.240 ;
    END
  END auto_buffer_out_b_bits_size[1]
  PIN auto_buffer_out_b_bits_size[2]
    DIRECTION INPUT ;
    USE SIGNAL ;
    ANTENNAGATEAREA 0.990000 ;
    PORT
      LAYER met2 ;
        RECT 708.490 2596.000 708.770 2600.000 ;
    END
  END auto_buffer_out_b_bits_size[2]
  PIN auto_buffer_out_b_bits_size[3]
    DIRECTION INPUT ;
    USE SIGNAL ;
    ANTENNAGATEAREA 0.990000 ;
    PORT
      LAYER met2 ;
        RECT 6897.330 0.000 6897.610 4.000 ;
    END
  END auto_buffer_out_b_bits_size[3]
  PIN auto_buffer_out_b_bits_source[0]
    DIRECTION INPUT ;
    USE SIGNAL ;
    ANTENNAGATEAREA 0.990000 ;
    PORT
      LAYER met2 ;
        RECT 4707.730 2596.000 4708.010 2600.000 ;
    END
  END auto_buffer_out_b_bits_source[0]
  PIN auto_buffer_out_b_bits_source[1]
    DIRECTION INPUT ;
    USE SIGNAL ;
    ANTENNAGATEAREA 0.990000 ;
    PORT
      LAYER met2 ;
        RECT 6262.990 0.000 6263.270 4.000 ;
    END
  END auto_buffer_out_b_bits_source[1]
  PIN auto_buffer_out_b_ready
    DIRECTION OUTPUT TRISTATE ;
    USE SIGNAL ;
    ANTENNADIFFAREA 0.340600 ;
    PORT
      LAYER met2 ;
        RECT 2279.850 2596.000 2280.130 2600.000 ;
    END
  END auto_buffer_out_b_ready
  PIN auto_buffer_out_b_valid
    DIRECTION INPUT ;
    USE SIGNAL ;
    ANTENNAGATEAREA 0.990000 ;
    PORT
      LAYER met3 ;
        RECT 0.000 1455.240 4.000 1455.840 ;
    END
  END auto_buffer_out_b_valid
  PIN auto_buffer_out_c_bits_address[0]
    DIRECTION OUTPUT TRISTATE ;
    USE SIGNAL ;
    ANTENNADIFFAREA 0.340600 ;
    PORT
      LAYER met2 ;
        RECT 5480.530 2596.000 5480.810 2600.000 ;
    END
  END auto_buffer_out_c_bits_address[0]
  PIN auto_buffer_out_c_bits_address[10]
    DIRECTION OUTPUT TRISTATE ;
    USE SIGNAL ;
    ANTENNADIFFAREA 0.340600 ;
    PORT
      LAYER met2 ;
        RECT 1735.670 0.000 1735.950 4.000 ;
    END
  END auto_buffer_out_c_bits_address[10]
  PIN auto_buffer_out_c_bits_address[11]
    DIRECTION OUTPUT TRISTATE ;
    USE SIGNAL ;
    ANTENNADIFFAREA 0.340600 ;
    PORT
      LAYER met2 ;
        RECT 4543.510 2596.000 4543.790 2600.000 ;
    END
  END auto_buffer_out_c_bits_address[11]
  PIN auto_buffer_out_c_bits_address[12]
    DIRECTION OUTPUT TRISTATE ;
    USE SIGNAL ;
    ANTENNADIFFAREA 0.340600 ;
    PORT
      LAYER met2 ;
        RECT 2427.970 0.000 2428.250 4.000 ;
    END
  END auto_buffer_out_c_bits_address[12]
  PIN auto_buffer_out_c_bits_address[13]
    DIRECTION OUTPUT TRISTATE ;
    USE SIGNAL ;
    ANTENNADIFFAREA 0.340600 ;
    PORT
      LAYER met2 ;
        RECT 183.630 2596.000 183.910 2600.000 ;
    END
  END auto_buffer_out_c_bits_address[13]
  PIN auto_buffer_out_c_bits_address[14]
    DIRECTION OUTPUT TRISTATE ;
    USE SIGNAL ;
    ANTENNADIFFAREA 0.340600 ;
    PORT
      LAYER met2 ;
        RECT 605.450 0.000 605.730 4.000 ;
    END
  END auto_buffer_out_c_bits_address[14]
  PIN auto_buffer_out_c_bits_address[15]
    DIRECTION OUTPUT TRISTATE ;
    USE SIGNAL ;
    ANTENNADIFFAREA 0.340600 ;
    PORT
      LAYER met2 ;
        RECT 4598.250 2596.000 4598.530 2600.000 ;
    END
  END auto_buffer_out_c_bits_address[15]
  PIN auto_buffer_out_c_bits_address[16]
    DIRECTION OUTPUT TRISTATE ;
    USE SIGNAL ;
    ANTENNADIFFAREA 0.340600 ;
    PORT
      LAYER met2 ;
        RECT 3806.130 0.000 3806.410 4.000 ;
    END
  END auto_buffer_out_c_bits_address[16]
  PIN auto_buffer_out_c_bits_address[17]
    DIRECTION OUTPUT TRISTATE ;
    USE SIGNAL ;
    ANTENNADIFFAREA 0.340600 ;
    PORT
      LAYER met2 ;
        RECT 1893.450 2596.000 1893.730 2600.000 ;
    END
  END auto_buffer_out_c_bits_address[17]
  PIN auto_buffer_out_c_bits_address[18]
    DIRECTION OUTPUT TRISTATE ;
    USE SIGNAL ;
    ANTENNADIFFAREA 0.340600 ;
    PORT
      LAYER met2 ;
        RECT 2199.350 2596.000 2199.630 2600.000 ;
    END
  END auto_buffer_out_c_bits_address[18]
  PIN auto_buffer_out_c_bits_address[19]
    DIRECTION OUTPUT TRISTATE ;
    USE SIGNAL ;
    ANTENNADIFFAREA 0.340600 ;
    PORT
      LAYER met2 ;
        RECT 4910.590 0.000 4910.870 4.000 ;
    END
  END auto_buffer_out_c_bits_address[19]
  PIN auto_buffer_out_c_bits_address[1]
    DIRECTION OUTPUT TRISTATE ;
    USE SIGNAL ;
    ANTENNADIFFAREA 0.340600 ;
    PORT
      LAYER met2 ;
        RECT 599.010 2596.000 599.290 2600.000 ;
    END
  END auto_buffer_out_c_bits_address[1]
  PIN auto_buffer_out_c_bits_address[20]
    DIRECTION OUTPUT TRISTATE ;
    USE SIGNAL ;
    ANTENNADIFFAREA 0.340600 ;
    PORT
      LAYER met2 ;
        RECT 6005.390 2596.000 6005.670 2600.000 ;
    END
  END auto_buffer_out_c_bits_address[20]
  PIN auto_buffer_out_c_bits_address[21]
    DIRECTION OUTPUT TRISTATE ;
    USE SIGNAL ;
    ANTENNADIFFAREA 0.340600 ;
    PORT
      LAYER met2 ;
        RECT 4469.450 0.000 4469.730 4.000 ;
    END
  END auto_buffer_out_c_bits_address[21]
  PIN auto_buffer_out_c_bits_address[22]
    DIRECTION OUTPUT TRISTATE ;
    USE SIGNAL ;
    ANTENNADIFFAREA 0.340600 ;
    PORT
      LAYER met2 ;
        RECT 2308.830 2596.000 2309.110 2600.000 ;
    END
  END auto_buffer_out_c_bits_address[22]
  PIN auto_buffer_out_c_bits_address[23]
    DIRECTION OUTPUT TRISTATE ;
    USE SIGNAL ;
    ANTENNADIFFAREA 0.340600 ;
    PORT
      LAYER met3 ;
        RECT 0.000 1135.640 4.000 1136.240 ;
    END
  END auto_buffer_out_c_bits_address[23]
  PIN auto_buffer_out_c_bits_address[24]
    DIRECTION OUTPUT TRISTATE ;
    USE SIGNAL ;
    ANTENNADIFFAREA 0.340600 ;
    PORT
      LAYER met2 ;
        RECT 2859.450 2596.000 2859.730 2600.000 ;
    END
  END auto_buffer_out_c_bits_address[24]
  PIN auto_buffer_out_c_bits_address[25]
    DIRECTION OUTPUT TRISTATE ;
    USE SIGNAL ;
    ANTENNADIFFAREA 0.340600 ;
    PORT
      LAYER met3 ;
        RECT 6996.000 1230.840 7000.000 1231.440 ;
    END
  END auto_buffer_out_c_bits_address[25]
  PIN auto_buffer_out_c_bits_address[26]
    DIRECTION OUTPUT TRISTATE ;
    USE SIGNAL ;
    ANTENNADIFFAREA 0.340600 ;
    PORT
      LAYER met3 ;
        RECT 0.000 115.640 4.000 116.240 ;
    END
  END auto_buffer_out_c_bits_address[26]
  PIN auto_buffer_out_c_bits_address[27]
    DIRECTION OUTPUT TRISTATE ;
    USE SIGNAL ;
    ANTENNADIFFAREA 0.340600 ;
    PORT
      LAYER met2 ;
        RECT 2527.790 2596.000 2528.070 2600.000 ;
    END
  END auto_buffer_out_c_bits_address[27]
  PIN auto_buffer_out_c_bits_address[28]
    DIRECTION OUTPUT TRISTATE ;
    USE SIGNAL ;
    ANTENNADIFFAREA 0.340600 ;
    PORT
      LAYER met3 ;
        RECT 0.000 85.040 4.000 85.640 ;
    END
  END auto_buffer_out_c_bits_address[28]
  PIN auto_buffer_out_c_bits_address[29]
    DIRECTION OUTPUT TRISTATE ;
    USE SIGNAL ;
    ANTENNADIFFAREA 0.340600 ;
    PORT
      LAYER met2 ;
        RECT 6475.510 2596.000 6475.790 2600.000 ;
    END
  END auto_buffer_out_c_bits_address[29]
  PIN auto_buffer_out_c_bits_address[2]
    DIRECTION OUTPUT TRISTATE ;
    USE SIGNAL ;
    ANTENNADIFFAREA 0.340600 ;
    PORT
      LAYER met3 ;
        RECT 6996.000 792.240 7000.000 792.840 ;
    END
  END auto_buffer_out_c_bits_address[2]
  PIN auto_buffer_out_c_bits_address[30]
    DIRECTION OUTPUT TRISTATE ;
    USE SIGNAL ;
    ANTENNADIFFAREA 0.340600 ;
    PORT
      LAYER met3 ;
        RECT 6996.000 2366.440 7000.000 2367.040 ;
    END
  END auto_buffer_out_c_bits_address[30]
  PIN auto_buffer_out_c_bits_address[31]
    DIRECTION OUTPUT TRISTATE ;
    USE SIGNAL ;
    ANTENNADIFFAREA 0.340600 ;
    PORT
      LAYER met3 ;
        RECT 6996.000 153.040 7000.000 153.640 ;
    END
  END auto_buffer_out_c_bits_address[31]
  PIN auto_buffer_out_c_bits_address[3]
    DIRECTION OUTPUT TRISTATE ;
    USE SIGNAL ;
    ANTENNADIFFAREA 0.340600 ;
    PORT
      LAYER met2 ;
        RECT 4688.410 0.000 4688.690 4.000 ;
    END
  END auto_buffer_out_c_bits_address[3]
  PIN auto_buffer_out_c_bits_address[4]
    DIRECTION OUTPUT TRISTATE ;
    USE SIGNAL ;
    ANTENNADIFFAREA 0.340600 ;
    PORT
      LAYER met2 ;
        RECT 2720.990 2596.000 2721.270 2600.000 ;
    END
  END auto_buffer_out_c_bits_address[4]
  PIN auto_buffer_out_c_bits_address[5]
    DIRECTION OUTPUT TRISTATE ;
    USE SIGNAL ;
    ANTENNADIFFAREA 0.340600 ;
    PORT
      LAYER met2 ;
        RECT 5020.070 0.000 5020.350 4.000 ;
    END
  END auto_buffer_out_c_bits_address[5]
  PIN auto_buffer_out_c_bits_address[6]
    DIRECTION OUTPUT TRISTATE ;
    USE SIGNAL ;
    ANTENNADIFFAREA 0.340600 ;
    PORT
      LAYER met3 ;
        RECT 6996.000 2250.840 7000.000 2251.440 ;
    END
  END auto_buffer_out_c_bits_address[6]
  PIN auto_buffer_out_c_bits_address[7]
    DIRECTION OUTPUT TRISTATE ;
    USE SIGNAL ;
    ANTENNADIFFAREA 0.340600 ;
    PORT
      LAYER met2 ;
        RECT 3999.330 0.000 3999.610 4.000 ;
    END
  END auto_buffer_out_c_bits_address[7]
  PIN auto_buffer_out_c_bits_address[8]
    DIRECTION OUTPUT TRISTATE ;
    USE SIGNAL ;
    ANTENNADIFFAREA 0.340600 ;
    PORT
      LAYER met2 ;
        RECT 2234.770 0.000 2235.050 4.000 ;
    END
  END auto_buffer_out_c_bits_address[8]
  PIN auto_buffer_out_c_bits_address[9]
    DIRECTION OUTPUT TRISTATE ;
    USE SIGNAL ;
    ANTENNADIFFAREA 0.340600 ;
    PORT
      LAYER met2 ;
        RECT 1185.050 0.000 1185.330 4.000 ;
    END
  END auto_buffer_out_c_bits_address[9]
  PIN auto_buffer_out_c_bits_data[0]
    DIRECTION OUTPUT TRISTATE ;
    USE SIGNAL ;
    ANTENNADIFFAREA 0.340600 ;
    PORT
      LAYER met2 ;
        RECT 2096.310 0.000 2096.590 4.000 ;
    END
  END auto_buffer_out_c_bits_data[0]
  PIN auto_buffer_out_c_bits_data[10]
    DIRECTION OUTPUT TRISTATE ;
    USE SIGNAL ;
    ANTENNADIFFAREA 0.340600 ;
    PORT
      LAYER met2 ;
        RECT 25.850 0.000 26.130 4.000 ;
    END
  END auto_buffer_out_c_bits_data[10]
  PIN auto_buffer_out_c_bits_data[11]
    DIRECTION OUTPUT TRISTATE ;
    USE SIGNAL ;
    ANTENNADIFFAREA 0.340600 ;
    PORT
      LAYER met3 ;
        RECT 6996.000 268.640 7000.000 269.240 ;
    END
  END auto_buffer_out_c_bits_data[11]
  PIN auto_buffer_out_c_bits_data[12]
    DIRECTION OUTPUT TRISTATE ;
    USE SIGNAL ;
    ANTENNADIFFAREA 0.340600 ;
    PORT
      LAYER met2 ;
        RECT 4965.330 0.000 4965.610 4.000 ;
    END
  END auto_buffer_out_c_bits_data[12]
  PIN auto_buffer_out_c_bits_data[13]
    DIRECTION OUTPUT TRISTATE ;
    USE SIGNAL ;
    ANTENNADIFFAREA 0.340600 ;
    PORT
      LAYER met3 ;
        RECT 6996.000 1723.840 7000.000 1724.440 ;
    END
  END auto_buffer_out_c_bits_data[13]
  PIN auto_buffer_out_c_bits_data[14]
    DIRECTION OUTPUT TRISTATE ;
    USE SIGNAL ;
    ANTENNADIFFAREA 0.340600 ;
    PORT
      LAYER met2 ;
        RECT 743.910 0.000 744.190 4.000 ;
    END
  END auto_buffer_out_c_bits_data[14]
  PIN auto_buffer_out_c_bits_data[15]
    DIRECTION OUTPUT TRISTATE ;
    USE SIGNAL ;
    ANTENNADIFFAREA 0.340600 ;
    PORT
      LAYER met2 ;
        RECT 4929.910 2596.000 4930.190 2600.000 ;
    END
  END auto_buffer_out_c_bits_data[15]
  PIN auto_buffer_out_c_bits_data[16]
    DIRECTION OUTPUT TRISTATE ;
    USE SIGNAL ;
    ANTENNADIFFAREA 0.340600 ;
    PORT
      LAYER met2 ;
        RECT 3741.730 2596.000 3742.010 2600.000 ;
    END
  END auto_buffer_out_c_bits_data[16]
  PIN auto_buffer_out_c_bits_data[17]
    DIRECTION OUTPUT TRISTATE ;
    USE SIGNAL ;
    ANTENNADIFFAREA 0.340600 ;
    PORT
      LAYER met3 ;
        RECT 6996.000 1638.840 7000.000 1639.440 ;
    END
  END auto_buffer_out_c_bits_data[17]
  PIN auto_buffer_out_c_bits_data[18]
    DIRECTION OUTPUT TRISTATE ;
    USE SIGNAL ;
    ANTENNADIFFAREA 0.340600 ;
    PORT
      LAYER met2 ;
        RECT 4633.670 0.000 4633.950 4.000 ;
    END
  END auto_buffer_out_c_bits_data[18]
  PIN auto_buffer_out_c_bits_data[19]
    DIRECTION OUTPUT TRISTATE ;
    USE SIGNAL ;
    ANTENNADIFFAREA 0.340600 ;
    PORT
      LAYER met2 ;
        RECT 4459.790 2596.000 4460.070 2600.000 ;
    END
  END auto_buffer_out_c_bits_data[19]
  PIN auto_buffer_out_c_bits_data[1]
    DIRECTION OUTPUT TRISTATE ;
    USE SIGNAL ;
    ANTENNADIFFAREA 0.340600 ;
    PORT
      LAYER met3 ;
        RECT 0.000 1659.240 4.000 1659.840 ;
    END
  END auto_buffer_out_c_bits_data[1]
  PIN auto_buffer_out_c_bits_data[20]
    DIRECTION OUTPUT TRISTATE ;
    USE SIGNAL ;
    ANTENNADIFFAREA 0.340600 ;
    PORT
      LAYER met2 ;
        RECT 2363.570 2596.000 2363.850 2600.000 ;
    END
  END auto_buffer_out_c_bits_data[20]
  PIN auto_buffer_out_c_bits_data[21]
    DIRECTION OUTPUT TRISTATE ;
    USE SIGNAL ;
    ANTENNADIFFAREA 0.340600 ;
    PORT
      LAYER met3 ;
        RECT 6996.000 2131.840 7000.000 2132.440 ;
    END
  END auto_buffer_out_c_bits_data[21]
  PIN auto_buffer_out_c_bits_data[22]
    DIRECTION OUTPUT TRISTATE ;
    USE SIGNAL ;
    ANTENNADIFFAREA 0.340600 ;
    PORT
      LAYER met3 ;
        RECT 6996.000 299.240 7000.000 299.840 ;
    END
  END auto_buffer_out_c_bits_data[22]
  PIN auto_buffer_out_c_bits_data[23]
    DIRECTION OUTPUT TRISTATE ;
    USE SIGNAL ;
    ANTENNADIFFAREA 0.340600 ;
    PORT
      LAYER met2 ;
        RECT 634.430 0.000 634.710 4.000 ;
    END
  END auto_buffer_out_c_bits_data[23]
  PIN auto_buffer_out_c_bits_data[24]
    DIRECTION OUTPUT TRISTATE ;
    USE SIGNAL ;
    ANTENNADIFFAREA 0.340600 ;
    PORT
      LAYER met3 ;
        RECT 0.000 1570.840 4.000 1571.440 ;
    END
  END auto_buffer_out_c_bits_data[24]
  PIN auto_buffer_out_c_bits_data[25]
    DIRECTION OUTPUT TRISTATE ;
    USE SIGNAL ;
    ANTENNADIFFAREA 0.340600 ;
    PORT
      LAYER met2 ;
        RECT 5049.050 0.000 5049.330 4.000 ;
    END
  END auto_buffer_out_c_bits_data[25]
  PIN auto_buffer_out_c_bits_data[26]
    DIRECTION OUTPUT TRISTATE ;
    USE SIGNAL ;
    ANTENNADIFFAREA 0.340600 ;
    PORT
      LAYER met3 ;
        RECT 6996.000 6.840 7000.000 7.440 ;
    END
  END auto_buffer_out_c_bits_data[26]
  PIN auto_buffer_out_c_bits_data[27]
    DIRECTION OUTPUT TRISTATE ;
    USE SIGNAL ;
    ANTENNADIFFAREA 0.340600 ;
    PORT
      LAYER met2 ;
        RECT 6179.270 0.000 6179.550 4.000 ;
    END
  END auto_buffer_out_c_bits_data[27]
  PIN auto_buffer_out_c_bits_data[28]
    DIRECTION OUTPUT TRISTATE ;
    USE SIGNAL ;
    ANTENNADIFFAREA 0.340600 ;
    PORT
      LAYER met2 ;
        RECT 3197.550 0.000 3197.830 4.000 ;
    END
  END auto_buffer_out_c_bits_data[28]
  PIN auto_buffer_out_c_bits_data[29]
    DIRECTION OUTPUT TRISTATE ;
    USE SIGNAL ;
    ANTENNADIFFAREA 0.340600 ;
    PORT
      LAYER met3 ;
        RECT 0.000 669.840 4.000 670.440 ;
    END
  END auto_buffer_out_c_bits_data[29]
  PIN auto_buffer_out_c_bits_data[2]
    DIRECTION OUTPUT TRISTATE ;
    USE SIGNAL ;
    ANTENNADIFFAREA 0.340600 ;
    PORT
      LAYER met2 ;
        RECT 6868.350 0.000 6868.630 4.000 ;
    END
  END auto_buffer_out_c_bits_data[2]
  PIN auto_buffer_out_c_bits_data[30]
    DIRECTION OUTPUT TRISTATE ;
    USE SIGNAL ;
    ANTENNADIFFAREA 0.340600 ;
    PORT
      LAYER met3 ;
        RECT 6996.000 210.840 7000.000 211.440 ;
    END
  END auto_buffer_out_c_bits_data[30]
  PIN auto_buffer_out_c_bits_data[31]
    DIRECTION OUTPUT TRISTATE ;
    USE SIGNAL ;
    ANTENNADIFFAREA 0.340600 ;
    PORT
      LAYER met2 ;
        RECT 6839.370 0.000 6839.650 4.000 ;
    END
  END auto_buffer_out_c_bits_data[31]
  PIN auto_buffer_out_c_bits_data[32]
    DIRECTION OUTPUT TRISTATE ;
    USE SIGNAL ;
    ANTENNADIFFAREA 0.340600 ;
    PORT
      LAYER met2 ;
        RECT 5876.590 0.000 5876.870 4.000 ;
    END
  END auto_buffer_out_c_bits_data[32]
  PIN auto_buffer_out_c_bits_data[33]
    DIRECTION OUTPUT TRISTATE ;
    USE SIGNAL ;
    ANTENNADIFFAREA 0.340600 ;
    PORT
      LAYER met2 ;
        RECT 4762.470 2596.000 4762.750 2600.000 ;
    END
  END auto_buffer_out_c_bits_data[33]
  PIN auto_buffer_out_c_bits_data[34]
    DIRECTION OUTPUT TRISTATE ;
    USE SIGNAL ;
    ANTENNADIFFAREA 0.340600 ;
    PORT
      LAYER met2 ;
        RECT 5261.570 2596.000 5261.850 2600.000 ;
    END
  END auto_buffer_out_c_bits_data[34]
  PIN auto_buffer_out_c_bits_data[35]
    DIRECTION OUTPUT TRISTATE ;
    USE SIGNAL ;
    ANTENNADIFFAREA 0.340600 ;
    PORT
      LAYER met3 ;
        RECT 6996.000 1842.840 7000.000 1843.440 ;
    END
  END auto_buffer_out_c_bits_data[35]
  PIN auto_buffer_out_c_bits_data[36]
    DIRECTION OUTPUT TRISTATE ;
    USE SIGNAL ;
    ANTENNADIFFAREA 0.340600 ;
    PORT
      LAYER met2 ;
        RECT 5342.070 2596.000 5342.350 2600.000 ;
    END
  END auto_buffer_out_c_bits_data[36]
  PIN auto_buffer_out_c_bits_data[37]
    DIRECTION OUTPUT TRISTATE ;
    USE SIGNAL ;
    ANTENNADIFFAREA 0.340600 ;
    PORT
      LAYER met2 ;
        RECT 1542.470 0.000 1542.750 4.000 ;
    END
  END auto_buffer_out_c_bits_data[37]
  PIN auto_buffer_out_c_bits_data[38]
    DIRECTION OUTPUT TRISTATE ;
    USE SIGNAL ;
    ANTENNADIFFAREA 0.340600 ;
    PORT
      LAYER met2 ;
        RECT 1867.690 2596.000 1867.970 2600.000 ;
    END
  END auto_buffer_out_c_bits_data[38]
  PIN auto_buffer_out_c_bits_data[39]
    DIRECTION OUTPUT TRISTATE ;
    USE SIGNAL ;
    ANTENNADIFFAREA 0.340600 ;
    PORT
      LAYER met3 ;
        RECT 6996.000 326.440 7000.000 327.040 ;
    END
  END auto_buffer_out_c_bits_data[39]
  PIN auto_buffer_out_c_bits_data[3]
    DIRECTION OUTPUT TRISTATE ;
    USE SIGNAL ;
    ANTENNADIFFAREA 0.340600 ;
    PORT
      LAYER met3 ;
        RECT 6996.000 503.240 7000.000 503.840 ;
    END
  END auto_buffer_out_c_bits_data[3]
  PIN auto_buffer_out_c_bits_data[40]
    DIRECTION OUTPUT TRISTATE ;
    USE SIGNAL ;
    ANTENNADIFFAREA 0.340600 ;
    PORT
      LAYER met2 ;
        RECT 6034.370 2596.000 6034.650 2600.000 ;
    END
  END auto_buffer_out_c_bits_data[40]
  PIN auto_buffer_out_c_bits_data[41]
    DIRECTION OUTPUT TRISTATE ;
    USE SIGNAL ;
    ANTENNADIFFAREA 0.340600 ;
    PORT
      LAYER met3 ;
        RECT 6996.000 530.440 7000.000 531.040 ;
    END
  END auto_buffer_out_c_bits_data[41]
  PIN auto_buffer_out_c_bits_data[42]
    DIRECTION OUTPUT TRISTATE ;
    USE SIGNAL ;
    ANTENNADIFFAREA 0.340600 ;
    PORT
      LAYER met2 ;
        RECT 6362.810 2596.000 6363.090 2600.000 ;
    END
  END auto_buffer_out_c_bits_data[42]
  PIN auto_buffer_out_c_bits_data[43]
    DIRECTION OUTPUT TRISTATE ;
    USE SIGNAL ;
    ANTENNADIFFAREA 0.340600 ;
    PORT
      LAYER met2 ;
        RECT 769.670 0.000 769.950 4.000 ;
    END
  END auto_buffer_out_c_bits_data[43]
  PIN auto_buffer_out_c_bits_data[44]
    DIRECTION OUTPUT TRISTATE ;
    USE SIGNAL ;
    ANTENNADIFFAREA 0.340600 ;
    PORT
      LAYER met3 ;
        RECT 6996.000 1492.640 7000.000 1493.240 ;
    END
  END auto_buffer_out_c_bits_data[44]
  PIN auto_buffer_out_c_bits_data[45]
    DIRECTION OUTPUT TRISTATE ;
    USE SIGNAL ;
    ANTENNADIFFAREA 0.340600 ;
    PORT
      LAYER met2 ;
        RECT 3686.990 2596.000 3687.270 2600.000 ;
    END
  END auto_buffer_out_c_bits_data[45]
  PIN auto_buffer_out_c_bits_data[46]
    DIRECTION OUTPUT TRISTATE ;
    USE SIGNAL ;
    ANTENNADIFFAREA 0.340600 ;
    PORT
      LAYER met2 ;
        RECT 2205.790 0.000 2206.070 4.000 ;
    END
  END auto_buffer_out_c_bits_data[46]
  PIN auto_buffer_out_c_bits_data[47]
    DIRECTION OUTPUT TRISTATE ;
    USE SIGNAL ;
    ANTENNADIFFAREA 0.340600 ;
    PORT
      LAYER met2 ;
        RECT 4524.190 0.000 4524.470 4.000 ;
    END
  END auto_buffer_out_c_bits_data[47]
  PIN auto_buffer_out_c_bits_data[48]
    DIRECTION OUTPUT TRISTATE ;
    USE SIGNAL ;
    ANTENNADIFFAREA 0.340600 ;
    PORT
      LAYER met3 ;
        RECT 0.000 231.240 4.000 231.840 ;
    END
  END auto_buffer_out_c_bits_data[48]
  PIN auto_buffer_out_c_bits_data[49]
    DIRECTION OUTPUT TRISTATE ;
    USE SIGNAL ;
    ANTENNADIFFAREA 0.340600 ;
    PORT
      LAYER met3 ;
        RECT 6996.000 1927.840 7000.000 1928.440 ;
    END
  END auto_buffer_out_c_bits_data[49]
  PIN auto_buffer_out_c_bits_data[4]
    DIRECTION OUTPUT TRISTATE ;
    USE SIGNAL ;
    ANTENNADIFFAREA 0.340600 ;
    PORT
      LAYER met2 ;
        RECT 157.870 2596.000 158.150 2600.000 ;
    END
  END auto_buffer_out_c_bits_data[4]
  PIN auto_buffer_out_c_bits_data[50]
    DIRECTION OUTPUT TRISTATE ;
    USE SIGNAL ;
    ANTENNADIFFAREA 0.340600 ;
    PORT
      LAYER met3 ;
        RECT 0.000 27.240 4.000 27.840 ;
    END
  END auto_buffer_out_c_bits_data[50]
  PIN auto_buffer_out_c_bits_data[51]
    DIRECTION OUTPUT TRISTATE ;
    USE SIGNAL ;
    ANTENNADIFFAREA 0.340600 ;
    PORT
      LAYER met2 ;
        RECT 2640.490 2596.000 2640.770 2600.000 ;
    END
  END auto_buffer_out_c_bits_data[51]
  PIN auto_buffer_out_c_bits_data[52]
    DIRECTION OUTPUT TRISTATE ;
    USE SIGNAL ;
    ANTENNADIFFAREA 0.340600 ;
    PORT
      LAYER met2 ;
        RECT 6089.110 2596.000 6089.390 2600.000 ;
    END
  END auto_buffer_out_c_bits_data[52]
  PIN auto_buffer_out_c_bits_data[53]
    DIRECTION OUTPUT TRISTATE ;
    USE SIGNAL ;
    ANTENNADIFFAREA 0.340600 ;
    PORT
      LAYER met2 ;
        RECT 1983.610 0.000 1983.890 4.000 ;
    END
  END auto_buffer_out_c_bits_data[53]
  PIN auto_buffer_out_c_bits_data[54]
    DIRECTION OUTPUT TRISTATE ;
    USE SIGNAL ;
    ANTENNADIFFAREA 0.340600 ;
    PORT
      LAYER met2 ;
        RECT 2260.530 0.000 2260.810 4.000 ;
    END
  END auto_buffer_out_c_bits_data[54]
  PIN auto_buffer_out_c_bits_data[55]
    DIRECTION OUTPUT TRISTATE ;
    USE SIGNAL ;
    ANTENNADIFFAREA 0.340600 ;
    PORT
      LAYER met2 ;
        RECT 6095.550 0.000 6095.830 4.000 ;
    END
  END auto_buffer_out_c_bits_data[55]
  PIN auto_buffer_out_c_bits_data[56]
    DIRECTION OUTPUT TRISTATE ;
    USE SIGNAL ;
    ANTENNADIFFAREA 0.340600 ;
    PORT
      LAYER met3 ;
        RECT 0.000 493.040 4.000 493.640 ;
    END
  END auto_buffer_out_c_bits_data[56]
  PIN auto_buffer_out_c_bits_data[57]
    DIRECTION OUTPUT TRISTATE ;
    USE SIGNAL ;
    ANTENNADIFFAREA 0.340600 ;
    PORT
      LAYER met2 ;
        RECT 4772.130 0.000 4772.410 4.000 ;
    END
  END auto_buffer_out_c_bits_data[57]
  PIN auto_buffer_out_c_bits_data[58]
    DIRECTION OUTPUT TRISTATE ;
    USE SIGNAL ;
    ANTENNADIFFAREA 0.340600 ;
    PORT
      LAYER met2 ;
        RECT 3300.590 2596.000 3300.870 2600.000 ;
    END
  END auto_buffer_out_c_bits_data[58]
  PIN auto_buffer_out_c_bits_data[59]
    DIRECTION OUTPUT TRISTATE ;
    USE SIGNAL ;
    ANTENNADIFFAREA 0.340600 ;
    PORT
      LAYER met3 ;
        RECT 0.000 346.840 4.000 347.440 ;
    END
  END auto_buffer_out_c_bits_data[59]
  PIN auto_buffer_out_c_bits_data[5]
    DIRECTION OUTPUT TRISTATE ;
    USE SIGNAL ;
    ANTENNADIFFAREA 0.340600 ;
    PORT
      LAYER met2 ;
        RECT 3577.510 2596.000 3577.790 2600.000 ;
    END
  END auto_buffer_out_c_bits_data[5]
  PIN auto_buffer_out_c_bits_data[60]
    DIRECTION OUTPUT TRISTATE ;
    USE SIGNAL ;
    ANTENNADIFFAREA 0.340600 ;
    PORT
      LAYER met2 ;
        RECT 6565.670 0.000 6565.950 4.000 ;
    END
  END auto_buffer_out_c_bits_data[60]
  PIN auto_buffer_out_c_bits_data[61]
    DIRECTION OUTPUT TRISTATE ;
    USE SIGNAL ;
    ANTENNADIFFAREA 0.340600 ;
    PORT
      LAYER met2 ;
        RECT 3062.310 0.000 3062.590 4.000 ;
    END
  END auto_buffer_out_c_bits_data[61]
  PIN auto_buffer_out_c_bits_data[62]
    DIRECTION OUTPUT TRISTATE ;
    USE SIGNAL ;
    ANTENNADIFFAREA 0.340600 ;
    PORT
      LAYER met2 ;
        RECT 6069.790 0.000 6070.070 4.000 ;
    END
  END auto_buffer_out_c_bits_data[62]
  PIN auto_buffer_out_c_bits_data[63]
    DIRECTION OUTPUT TRISTATE ;
    USE SIGNAL ;
    ANTENNADIFFAREA 0.340600 ;
    PORT
      LAYER met2 ;
        RECT 1239.790 0.000 1240.070 4.000 ;
    END
  END auto_buffer_out_c_bits_data[63]
  PIN auto_buffer_out_c_bits_data[6]
    DIRECTION OUTPUT TRISTATE ;
    USE SIGNAL ;
    ANTENNADIFFAREA 0.340600 ;
    PORT
      LAYER met3 ;
        RECT 6996.000 618.840 7000.000 619.440 ;
    END
  END auto_buffer_out_c_bits_data[6]
  PIN auto_buffer_out_c_bits_data[7]
    DIRECTION OUTPUT TRISTATE ;
    USE SIGNAL ;
    ANTENNADIFFAREA 0.340600 ;
    PORT
      LAYER met3 ;
        RECT 0.000 404.640 4.000 405.240 ;
    END
  END auto_buffer_out_c_bits_data[7]
  PIN auto_buffer_out_c_bits_data[8]
    DIRECTION OUTPUT TRISTATE ;
    USE SIGNAL ;
    ANTENNADIFFAREA 0.340600 ;
    PORT
      LAYER met2 ;
        RECT 1977.170 2596.000 1977.450 2600.000 ;
    END
  END auto_buffer_out_c_bits_data[8]
  PIN auto_buffer_out_c_bits_data[9]
    DIRECTION OUTPUT TRISTATE ;
    USE SIGNAL ;
    ANTENNADIFFAREA 0.340600 ;
    PORT
      LAYER met2 ;
        RECT 3529.210 0.000 3529.490 4.000 ;
    END
  END auto_buffer_out_c_bits_data[9]
  PIN auto_buffer_out_c_bits_opcode[0]
    DIRECTION OUTPUT TRISTATE ;
    USE SIGNAL ;
    ANTENNADIFFAREA 0.340600 ;
    PORT
      LAYER met2 ;
        RECT 3641.910 0.000 3642.190 4.000 ;
    END
  END auto_buffer_out_c_bits_opcode[0]
  PIN auto_buffer_out_c_bits_opcode[1]
    DIRECTION OUTPUT TRISTATE ;
    USE SIGNAL ;
    ANTENNADIFFAREA 0.340600 ;
    PORT
      LAYER met2 ;
        RECT 6446.530 2596.000 6446.810 2600.000 ;
    END
  END auto_buffer_out_c_bits_opcode[1]
  PIN auto_buffer_out_c_bits_opcode[2]
    DIRECTION OUTPUT TRISTATE ;
    USE SIGNAL ;
    PORT
      LAYER met3 ;
        RECT 6996.000 1785.040 7000.000 1785.640 ;
    END
  END auto_buffer_out_c_bits_opcode[2]
  PIN auto_buffer_out_c_bits_param[0]
    DIRECTION OUTPUT TRISTATE ;
    USE SIGNAL ;
    ANTENNADIFFAREA 0.340600 ;
    PORT
      LAYER met2 ;
        RECT 1597.210 0.000 1597.490 4.000 ;
    END
  END auto_buffer_out_c_bits_param[0]
  PIN auto_buffer_out_c_bits_param[1]
    DIRECTION OUTPUT TRISTATE ;
    USE SIGNAL ;
    ANTENNADIFFAREA 0.340600 ;
    PORT
      LAYER met2 ;
        RECT 6613.970 2596.000 6614.250 2600.000 ;
    END
  END auto_buffer_out_c_bits_param[1]
  PIN auto_buffer_out_c_bits_param[2]
    DIRECTION OUTPUT TRISTATE ;
    USE SIGNAL ;
    ANTENNADIFFAREA 0.340600 ;
    PORT
      LAYER met3 ;
        RECT 0.000 2444.640 4.000 2445.240 ;
    END
  END auto_buffer_out_c_bits_param[2]
  PIN auto_buffer_out_c_bits_size[0]
    DIRECTION OUTPUT TRISTATE ;
    USE SIGNAL ;
    ANTENNADIFFAREA 0.340600 ;
    PORT
      LAYER met2 ;
        RECT 3355.330 2596.000 3355.610 2600.000 ;
    END
  END auto_buffer_out_c_bits_size[0]
  PIN auto_buffer_out_c_bits_size[1]
    DIRECTION OUTPUT TRISTATE ;
    USE SIGNAL ;
    ANTENNADIFFAREA 0.340600 ;
    PORT
      LAYER met2 ;
        RECT 2122.070 0.000 2122.350 4.000 ;
    END
  END auto_buffer_out_c_bits_size[1]
  PIN auto_buffer_out_c_bits_size[2]
    DIRECTION OUTPUT TRISTATE ;
    USE SIGNAL ;
    ANTENNADIFFAREA 0.340600 ;
    PORT
      LAYER met3 ;
        RECT 6996.000 646.040 7000.000 646.640 ;
    END
  END auto_buffer_out_c_bits_size[2]
  PIN auto_buffer_out_c_bits_size[3]
    DIRECTION OUTPUT TRISTATE ;
    USE SIGNAL ;
    ANTENNADIFFAREA 0.340600 ;
    PORT
      LAYER met2 ;
        RECT 4826.870 0.000 4827.150 4.000 ;
    END
  END auto_buffer_out_c_bits_size[3]
  PIN auto_buffer_out_c_bits_source[0]
    DIRECTION OUTPUT TRISTATE ;
    USE SIGNAL ;
    ANTENNADIFFAREA 0.340600 ;
    PORT
      LAYER met2 ;
        RECT 6704.130 0.000 6704.410 4.000 ;
    END
  END auto_buffer_out_c_bits_source[0]
  PIN auto_buffer_out_c_bits_source[1]
    DIRECTION OUTPUT TRISTATE ;
    USE SIGNAL ;
    PORT
      LAYER met2 ;
        RECT 135.330 0.000 135.610 4.000 ;
    END
  END auto_buffer_out_c_bits_source[1]
  PIN auto_buffer_out_c_ready
    DIRECTION INPUT ;
    USE SIGNAL ;
    ANTENNAGATEAREA 0.990000 ;
    PORT
      LAYER met2 ;
        RECT 2067.330 0.000 2067.610 4.000 ;
    END
  END auto_buffer_out_c_ready
  PIN auto_buffer_out_c_valid
    DIRECTION OUTPUT TRISTATE ;
    USE SIGNAL ;
    ANTENNADIFFAREA 0.340600 ;
    PORT
      LAYER met3 ;
        RECT 0.000 2563.640 4.000 2564.240 ;
    END
  END auto_buffer_out_c_valid
  PIN auto_buffer_out_d_bits_corrupt
    DIRECTION INPUT ;
    USE SIGNAL ;
    ANTENNAGATEAREA 0.990000 ;
    PORT
      LAYER met2 ;
        RECT 6723.450 2596.000 6723.730 2600.000 ;
    END
  END auto_buffer_out_d_bits_corrupt
  PIN auto_buffer_out_d_bits_data[0]
    DIRECTION INPUT ;
    USE SIGNAL ;
    ANTENNAGATEAREA 0.990000 ;
    PORT
      LAYER met2 ;
        RECT 5654.410 0.000 5654.690 4.000 ;
    END
  END auto_buffer_out_d_bits_data[0]
  PIN auto_buffer_out_d_bits_data[10]
    DIRECTION INPUT ;
    USE SIGNAL ;
    ANTENNAGATEAREA 0.990000 ;
    PORT
      LAYER met3 ;
        RECT 0.000 2417.440 4.000 2418.040 ;
    END
  END auto_buffer_out_d_bits_data[10]
  PIN auto_buffer_out_d_bits_data[11]
    DIRECTION INPUT ;
    USE SIGNAL ;
    ANTENNAGATEAREA 0.495000 ;
    PORT
      LAYER met3 ;
        RECT 0.000 1193.440 4.000 1194.040 ;
    END
  END auto_buffer_out_d_bits_data[11]
  PIN auto_buffer_out_d_bits_data[12]
    DIRECTION INPUT ;
    USE SIGNAL ;
    ANTENNAGATEAREA 0.495000 ;
    PORT
      LAYER met2 ;
        RECT 5866.930 2596.000 5867.210 2600.000 ;
    END
  END auto_buffer_out_d_bits_data[12]
  PIN auto_buffer_out_d_bits_data[13]
    DIRECTION INPUT ;
    USE SIGNAL ;
    ANTENNAGATEAREA 0.852000 ;
    PORT
      LAYER met2 ;
        RECT 1790.410 0.000 1790.690 4.000 ;
    END
  END auto_buffer_out_d_bits_data[13]
  PIN auto_buffer_out_d_bits_data[14]
    DIRECTION INPUT ;
    USE SIGNAL ;
    ANTENNAGATEAREA 0.990000 ;
    PORT
      LAYER met2 ;
        RECT 4936.350 0.000 4936.630 4.000 ;
    END
  END auto_buffer_out_d_bits_data[14]
  PIN auto_buffer_out_d_bits_data[15]
    DIRECTION INPUT ;
    USE SIGNAL ;
    ANTENNAGATEAREA 0.990000 ;
    PORT
      LAYER met2 ;
        RECT 4240.830 2596.000 4241.110 2600.000 ;
    END
  END auto_buffer_out_d_bits_data[15]
  PIN auto_buffer_out_d_bits_data[16]
    DIRECTION INPUT ;
    USE SIGNAL ;
    ANTENNAGATEAREA 0.852000 ;
    PORT
      LAYER met2 ;
        RECT 1461.970 0.000 1462.250 4.000 ;
    END
  END auto_buffer_out_d_bits_data[16]
  PIN auto_buffer_out_d_bits_data[17]
    DIRECTION INPUT ;
    USE SIGNAL ;
    ANTENNAGATEAREA 0.990000 ;
    PORT
      LAYER met2 ;
        RECT 734.250 2596.000 734.530 2600.000 ;
    END
  END auto_buffer_out_d_bits_data[17]
  PIN auto_buffer_out_d_bits_data[18]
    DIRECTION INPUT ;
    USE SIGNAL ;
    ANTENNAGATEAREA 0.990000 ;
    PORT
      LAYER met2 ;
        RECT 5425.790 2596.000 5426.070 2600.000 ;
    END
  END auto_buffer_out_d_bits_data[18]
  PIN auto_buffer_out_d_bits_data[19]
    DIRECTION INPUT ;
    USE SIGNAL ;
    ANTENNAGATEAREA 0.852000 ;
    PORT
      LAYER met2 ;
        RECT 882.370 0.000 882.650 4.000 ;
    END
  END auto_buffer_out_d_bits_data[19]
  PIN auto_buffer_out_d_bits_data[1]
    DIRECTION INPUT ;
    USE SIGNAL ;
    ANTENNAGATEAREA 0.990000 ;
    PORT
      LAYER met3 ;
        RECT 0.000 1686.440 4.000 1687.040 ;
    END
  END auto_buffer_out_d_bits_data[1]
  PIN auto_buffer_out_d_bits_data[20]
    DIRECTION INPUT ;
    USE SIGNAL ;
    ANTENNAGATEAREA 0.990000 ;
    PORT
      LAYER met2 ;
        RECT 486.310 2596.000 486.590 2600.000 ;
    END
  END auto_buffer_out_d_bits_data[20]
  PIN auto_buffer_out_d_bits_data[21]
    DIRECTION INPUT ;
    USE SIGNAL ;
    ANTENNAGATEAREA 0.742500 ;
    PORT
      LAYER met2 ;
        RECT 3944.590 0.000 3944.870 4.000 ;
    END
  END auto_buffer_out_d_bits_data[21]
  PIN auto_buffer_out_d_bits_data[22]
    DIRECTION INPUT ;
    USE SIGNAL ;
    ANTENNAGATEAREA 0.990000 ;
    PORT
      LAYER met2 ;
        RECT 1948.190 2596.000 1948.470 2600.000 ;
    END
  END auto_buffer_out_d_bits_data[22]
  PIN auto_buffer_out_d_bits_data[23]
    DIRECTION INPUT ;
    USE SIGNAL ;
    ANTENNAGATEAREA 0.852000 ;
    PORT
      LAYER met2 ;
        RECT 3468.030 2596.000 3468.310 2600.000 ;
    END
  END auto_buffer_out_d_bits_data[23]
  PIN auto_buffer_out_d_bits_data[24]
    DIRECTION INPUT ;
    USE SIGNAL ;
    ANTENNAGATEAREA 0.990000 ;
    PORT
      LAYER met2 ;
        RECT 5094.130 2596.000 5094.410 2600.000 ;
    END
  END auto_buffer_out_d_bits_data[24]
  PIN auto_buffer_out_d_bits_data[25]
    DIRECTION INPUT ;
    USE SIGNAL ;
    ANTENNAGATEAREA 0.990000 ;
    PORT
      LAYER met2 ;
        RECT 4717.390 0.000 4717.670 4.000 ;
    END
  END auto_buffer_out_d_bits_data[25]
  PIN auto_buffer_out_d_bits_data[26]
    DIRECTION INPUT ;
    USE SIGNAL ;
    ANTENNAGATEAREA 0.990000 ;
    PORT
      LAYER met2 ;
        RECT 5013.630 2596.000 5013.910 2600.000 ;
    END
  END auto_buffer_out_d_bits_data[26]
  PIN auto_buffer_out_d_bits_data[27]
    DIRECTION INPUT ;
    USE SIGNAL ;
    ANTENNAGATEAREA 0.426000 ;
    PORT
      LAYER met3 ;
        RECT 6996.000 1173.040 7000.000 1173.640 ;
    END
  END auto_buffer_out_d_bits_data[27]
  PIN auto_buffer_out_d_bits_data[28]
    DIRECTION INPUT ;
    USE SIGNAL ;
    ANTENNAGATEAREA 0.990000 ;
    PORT
      LAYER met3 ;
        RECT 0.000 2298.440 4.000 2299.040 ;
    END
  END auto_buffer_out_d_bits_data[28]
  PIN auto_buffer_out_d_bits_data[29]
    DIRECTION INPUT ;
    USE SIGNAL ;
    ANTENNAGATEAREA 0.495000 ;
    PORT
      LAYER met3 ;
        RECT 0.000 1251.240 4.000 1251.840 ;
    END
  END auto_buffer_out_d_bits_data[29]
  PIN auto_buffer_out_d_bits_data[2]
    DIRECTION INPUT ;
    USE SIGNAL ;
    ANTENNAGATEAREA 0.742500 ;
    PORT
      LAYER met2 ;
        RECT 2398.990 0.000 2399.270 4.000 ;
    END
  END auto_buffer_out_d_bits_data[2]
  PIN auto_buffer_out_d_bits_data[30]
    DIRECTION INPUT ;
    USE SIGNAL ;
    ANTENNAGATEAREA 0.495000 ;
    PORT
      LAYER met2 ;
        RECT 3777.150 0.000 3777.430 4.000 ;
    END
  END auto_buffer_out_d_bits_data[30]
  PIN auto_buffer_out_d_bits_data[31]
    DIRECTION INPUT ;
    USE SIGNAL ;
    ANTENNAGATEAREA 0.990000 ;
    PORT
      LAYER met2 ;
        RECT 4434.030 2596.000 4434.310 2600.000 ;
    END
  END auto_buffer_out_d_bits_data[31]
  PIN auto_buffer_out_d_bits_data[32]
    DIRECTION INPUT ;
    USE SIGNAL ;
    ANTENNAGATEAREA 0.495000 ;
    PORT
      LAYER met3 ;
        RECT 0.000 1281.840 4.000 1282.440 ;
    END
  END auto_buffer_out_d_bits_data[32]
  PIN auto_buffer_out_d_bits_data[33]
    DIRECTION INPUT ;
    USE SIGNAL ;
    ANTENNAGATEAREA 0.426000 ;
    PORT
      LAYER met2 ;
        RECT 6923.090 0.000 6923.370 4.000 ;
    END
  END auto_buffer_out_d_bits_data[33]
  PIN auto_buffer_out_d_bits_data[34]
    DIRECTION INPUT ;
    USE SIGNAL ;
    ANTENNAGATEAREA 0.990000 ;
    PORT
      LAYER met2 ;
        RECT 6124.530 0.000 6124.810 4.000 ;
    END
  END auto_buffer_out_d_bits_data[34]
  PIN auto_buffer_out_d_bits_data[35]
    DIRECTION INPUT ;
    USE SIGNAL ;
    ANTENNAGATEAREA 0.495000 ;
    PORT
      LAYER met3 ;
        RECT 0.000 1513.040 4.000 1513.640 ;
    END
  END auto_buffer_out_d_bits_data[35]
  PIN auto_buffer_out_d_bits_data[36]
    DIRECTION INPUT ;
    USE SIGNAL ;
    ANTENNAGATEAREA 0.852000 ;
    PORT
      LAYER met2 ;
        RECT 5738.130 0.000 5738.410 4.000 ;
    END
  END auto_buffer_out_d_bits_data[36]
  PIN auto_buffer_out_d_bits_data[37]
    DIRECTION INPUT ;
    USE SIGNAL ;
    ANTENNAGATEAREA 0.990000 ;
    PORT
      LAYER met2 ;
        RECT 6198.590 2596.000 6198.870 2600.000 ;
    END
  END auto_buffer_out_d_bits_data[37]
  PIN auto_buffer_out_d_bits_data[38]
    DIRECTION INPUT ;
    USE SIGNAL ;
    ANTENNAGATEAREA 0.852000 ;
    PORT
      LAYER met2 ;
        RECT 4662.650 0.000 4662.930 4.000 ;
    END
  END auto_buffer_out_d_bits_data[38]
  PIN auto_buffer_out_d_bits_data[39]
    DIRECTION INPUT ;
    USE SIGNAL ;
    ANTENNAGATEAREA 0.742500 ;
    PORT
      LAYER met2 ;
        RECT 99.910 2596.000 100.190 2600.000 ;
    END
  END auto_buffer_out_d_bits_data[39]
  PIN auto_buffer_out_d_bits_data[3]
    DIRECTION INPUT ;
    USE SIGNAL ;
    ANTENNAGATEAREA 0.990000 ;
    PORT
      LAYER met2 ;
        RECT 5570.690 0.000 5570.970 4.000 ;
    END
  END auto_buffer_out_d_bits_data[3]
  PIN auto_buffer_out_d_bits_data[40]
    DIRECTION INPUT ;
    USE SIGNAL ;
    ANTENNAGATEAREA 0.990000 ;
    PORT
      LAYER met2 ;
        RECT 1516.710 0.000 1516.990 4.000 ;
    END
  END auto_buffer_out_d_bits_data[40]
  PIN auto_buffer_out_d_bits_data[41]
    DIRECTION INPUT ;
    USE SIGNAL ;
    ANTENNAGATEAREA 0.495000 ;
    PORT
      LAYER met3 ;
        RECT 6996.000 180.240 7000.000 180.840 ;
    END
  END auto_buffer_out_d_bits_data[41]
  PIN auto_buffer_out_d_bits_data[42]
    DIRECTION INPUT ;
    USE SIGNAL ;
    ANTENNAGATEAREA 0.990000 ;
    PORT
      LAYER met2 ;
        RECT 1288.090 2596.000 1288.370 2600.000 ;
    END
  END auto_buffer_out_d_bits_data[42]
  PIN auto_buffer_out_d_bits_data[43]
    DIRECTION INPUT ;
    USE SIGNAL ;
    ANTENNAGATEAREA 0.852000 ;
    PORT
      LAYER met2 ;
        RECT 3245.850 2596.000 3246.130 2600.000 ;
    END
  END auto_buffer_out_d_bits_data[43]
  PIN auto_buffer_out_d_bits_data[44]
    DIRECTION INPUT ;
    USE SIGNAL ;
    ANTENNAGATEAREA 0.426000 ;
    PORT
      LAYER met2 ;
        RECT 347.850 2596.000 348.130 2600.000 ;
    END
  END auto_buffer_out_d_bits_data[44]
  PIN auto_buffer_out_d_bits_data[45]
    DIRECTION INPUT ;
    USE SIGNAL ;
    ANTENNAGATEAREA 0.196500 ;
    PORT
      LAYER met2 ;
        RECT 3667.670 0.000 3667.950 4.000 ;
    END
  END auto_buffer_out_d_bits_data[45]
  PIN auto_buffer_out_d_bits_data[46]
    DIRECTION INPUT ;
    USE SIGNAL ;
    ANTENNAGATEAREA 0.990000 ;
    PORT
      LAYER met2 ;
        RECT 1481.290 2596.000 1481.570 2600.000 ;
    END
  END auto_buffer_out_d_bits_data[46]
  PIN auto_buffer_out_d_bits_data[47]
    DIRECTION INPUT ;
    USE SIGNAL ;
    ANTENNAGATEAREA 0.852000 ;
    PORT
      LAYER met2 ;
        RECT 2968.930 2596.000 2969.210 2600.000 ;
    END
  END auto_buffer_out_d_bits_data[47]
  PIN auto_buffer_out_d_bits_data[48]
    DIRECTION INPUT ;
    USE SIGNAL ;
    ANTENNAGATEAREA 0.742500 ;
    PORT
      LAYER met2 ;
        RECT 2833.690 2596.000 2833.970 2600.000 ;
    END
  END auto_buffer_out_d_bits_data[48]
  PIN auto_buffer_out_d_bits_data[49]
    DIRECTION INPUT ;
    USE SIGNAL ;
    ANTENNAGATEAREA 0.852000 ;
    PORT
      LAYER met2 ;
        RECT 4411.490 0.000 4411.770 4.000 ;
    END
  END auto_buffer_out_d_bits_data[49]
  PIN auto_buffer_out_d_bits_data[4]
    DIRECTION INPUT ;
    USE SIGNAL ;
    ANTENNAGATEAREA 0.990000 ;
    PORT
      LAYER met2 ;
        RECT 5432.230 0.000 5432.510 4.000 ;
    END
  END auto_buffer_out_d_bits_data[4]
  PIN auto_buffer_out_d_bits_data[50]
    DIRECTION INPUT ;
    USE SIGNAL ;
    ANTENNAGATEAREA 0.495000 ;
    PORT
      LAYER met3 ;
        RECT 0.000 2067.240 4.000 2067.840 ;
    END
  END auto_buffer_out_d_bits_data[50]
  PIN auto_buffer_out_d_bits_data[51]
    DIRECTION INPUT ;
    USE SIGNAL ;
    ANTENNAGATEAREA 0.495000 ;
    PORT
      LAYER met2 ;
        RECT 6620.410 0.000 6620.690 4.000 ;
    END
  END auto_buffer_out_d_bits_data[51]
  PIN auto_buffer_out_d_bits_data[52]
    DIRECTION INPUT ;
    USE SIGNAL ;
    ANTENNAGATEAREA 0.495000 ;
    PORT
      LAYER met3 ;
        RECT 0.000 319.640 4.000 320.240 ;
    END
  END auto_buffer_out_d_bits_data[52]
  PIN auto_buffer_out_d_bits_data[53]
    DIRECTION INPUT ;
    USE SIGNAL ;
    ANTENNAGATEAREA 0.990000 ;
    PORT
      LAYER met3 ;
        RECT 0.000 1105.040 4.000 1105.640 ;
    END
  END auto_buffer_out_d_bits_data[53]
  PIN auto_buffer_out_d_bits_data[54]
    DIRECTION INPUT ;
    USE SIGNAL ;
    ANTENNAGATEAREA 0.852000 ;
    PORT
      LAYER met2 ;
        RECT 3715.970 2596.000 3716.250 2600.000 ;
    END
  END auto_buffer_out_d_bits_data[54]
  PIN auto_buffer_out_d_bits_data[55]
    DIRECTION INPUT ;
    USE SIGNAL ;
    ANTENNAGATEAREA 0.990000 ;
    PORT
      LAYER met2 ;
        RECT 4875.170 2596.000 4875.450 2600.000 ;
    END
  END auto_buffer_out_d_bits_data[55]
  PIN auto_buffer_out_d_bits_data[56]
    DIRECTION INPUT ;
    USE SIGNAL ;
    ANTENNAGATEAREA 0.426000 ;
    PORT
      LAYER met3 ;
        RECT 0.000 2182.840 4.000 2183.440 ;
    END
  END auto_buffer_out_d_bits_data[56]
  PIN auto_buffer_out_d_bits_data[57]
    DIRECTION INPUT ;
    USE SIGNAL ;
    ANTENNAGATEAREA 0.495000 ;
    PORT
      LAYER met3 ;
        RECT 0.000 901.040 4.000 901.640 ;
    END
  END auto_buffer_out_d_bits_data[57]
  PIN auto_buffer_out_d_bits_data[58]
    DIRECTION INPUT ;
    USE SIGNAL ;
    ANTENNAGATEAREA 0.990000 ;
    PORT
      LAYER met2 ;
        RECT 2447.290 2596.000 2447.570 2600.000 ;
    END
  END auto_buffer_out_d_bits_data[58]
  PIN auto_buffer_out_d_bits_data[59]
    DIRECTION INPUT ;
    USE SIGNAL ;
    ANTENNAGATEAREA 0.990000 ;
    PORT
      LAYER met2 ;
        RECT 1040.150 2596.000 1040.430 2600.000 ;
    END
  END auto_buffer_out_d_bits_data[59]
  PIN auto_buffer_out_d_bits_data[5]
    DIRECTION INPUT ;
    USE SIGNAL ;
    ANTENNAGATEAREA 0.990000 ;
    PORT
      LAYER met3 ;
        RECT 0.000 1482.440 4.000 1483.040 ;
    END
  END auto_buffer_out_d_bits_data[5]
  PIN auto_buffer_out_d_bits_data[60]
    DIRECTION INPUT ;
    USE SIGNAL ;
    ANTENNAGATEAREA 0.852000 ;
    PORT
      LAYER met2 ;
        RECT 2785.390 0.000 2785.670 4.000 ;
    END
  END auto_buffer_out_d_bits_data[60]
  PIN auto_buffer_out_d_bits_data[61]
    DIRECTION INPUT ;
    USE SIGNAL ;
    ANTENNAGATEAREA 0.852000 ;
    PORT
      LAYER met2 ;
        RECT 4405.050 2596.000 4405.330 2600.000 ;
    END
  END auto_buffer_out_d_bits_data[61]
  PIN auto_buffer_out_d_bits_data[62]
    DIRECTION INPUT ;
    USE SIGNAL ;
    ANTENNAGATEAREA 0.990000 ;
    PORT
      LAYER met2 ;
        RECT 1700.250 2596.000 1700.530 2600.000 ;
    END
  END auto_buffer_out_d_bits_data[62]
  PIN auto_buffer_out_d_bits_data[63]
    DIRECTION INPUT ;
    USE SIGNAL ;
    ANTENNAGATEAREA 0.742500 ;
    PORT
      LAYER met2 ;
        RECT 2840.130 0.000 2840.410 4.000 ;
    END
  END auto_buffer_out_d_bits_data[63]
  PIN auto_buffer_out_d_bits_data[6]
    DIRECTION INPUT ;
    USE SIGNAL ;
    ANTENNAGATEAREA 0.990000 ;
    PORT
      LAYER met2 ;
        RECT 4102.370 2596.000 4102.650 2600.000 ;
    END
  END auto_buffer_out_d_bits_data[6]
  PIN auto_buffer_out_d_bits_data[7]
    DIRECTION INPUT ;
    USE SIGNAL ;
    ANTENNAGATEAREA 0.852000 ;
    PORT
      LAYER met2 ;
        RECT 714.930 0.000 715.210 4.000 ;
    END
  END auto_buffer_out_d_bits_data[7]
  PIN auto_buffer_out_d_bits_data[8]
    DIRECTION INPUT ;
    USE SIGNAL ;
    ANTENNAGATEAREA 0.852000 ;
    PORT
      LAYER met2 ;
        RECT 4108.810 0.000 4109.090 4.000 ;
    END
  END auto_buffer_out_d_bits_data[8]
  PIN auto_buffer_out_d_bits_data[9]
    DIRECTION INPUT ;
    USE SIGNAL ;
    ANTENNAGATEAREA 0.990000 ;
    PORT
      LAYER met2 ;
        RECT 4549.950 0.000 4550.230 4.000 ;
    END
  END auto_buffer_out_d_bits_data[9]
  PIN auto_buffer_out_d_bits_denied
    DIRECTION INPUT ;
    USE SIGNAL ;
    ANTENNAGATEAREA 0.990000 ;
    PORT
      LAYER met3 ;
        RECT 6996.000 1026.840 7000.000 1027.440 ;
    END
  END auto_buffer_out_d_bits_denied
  PIN auto_buffer_out_d_bits_opcode[0]
    DIRECTION INPUT ;
    USE SIGNAL ;
    ANTENNAGATEAREA 0.990000 ;
    PORT
      LAYER met2 ;
        RECT 6343.490 0.000 6343.770 4.000 ;
    END
  END auto_buffer_out_d_bits_opcode[0]
  PIN auto_buffer_out_d_bits_opcode[1]
    DIRECTION INPUT ;
    USE SIGNAL ;
    ANTENNAGATEAREA 0.990000 ;
    PORT
      LAYER met2 ;
        RECT 2997.910 2596.000 2998.190 2600.000 ;
    END
  END auto_buffer_out_d_bits_opcode[1]
  PIN auto_buffer_out_d_bits_opcode[2]
    DIRECTION INPUT ;
    USE SIGNAL ;
    ANTENNAGATEAREA 0.852000 ;
    PORT
      LAYER met2 ;
        RECT 2482.710 0.000 2482.990 4.000 ;
    END
  END auto_buffer_out_d_bits_opcode[2]
  PIN auto_buffer_out_d_bits_param[0]
    DIRECTION INPUT ;
    USE SIGNAL ;
    ANTENNAGATEAREA 0.990000 ;
    PORT
      LAYER met2 ;
        RECT 3696.650 0.000 3696.930 4.000 ;
    END
  END auto_buffer_out_d_bits_param[0]
  PIN auto_buffer_out_d_bits_param[1]
    DIRECTION INPUT ;
    USE SIGNAL ;
    ANTENNAGATEAREA 0.990000 ;
    PORT
      LAYER met2 ;
        RECT 4652.990 2596.000 4653.270 2600.000 ;
    END
  END auto_buffer_out_d_bits_param[1]
  PIN auto_buffer_out_d_bits_sink[0]
    DIRECTION INPUT ;
    USE SIGNAL ;
    ANTENNAGATEAREA 0.990000 ;
    PORT
      LAYER met2 ;
        RECT 45.170 2596.000 45.450 2600.000 ;
    END
  END auto_buffer_out_d_bits_sink[0]
  PIN auto_buffer_out_d_bits_sink[1]
    DIRECTION INPUT ;
    USE SIGNAL ;
    ANTENNAGATEAREA 0.495000 ;
    PORT
      LAYER met2 ;
        RECT 2811.150 0.000 2811.430 4.000 ;
    END
  END auto_buffer_out_d_bits_sink[1]
  PIN auto_buffer_out_d_bits_size[0]
    DIRECTION INPUT ;
    USE SIGNAL ;
    ANTENNAGATEAREA 0.990000 ;
    PORT
      LAYER met3 ;
        RECT 0.000 2213.440 4.000 2214.040 ;
    END
  END auto_buffer_out_d_bits_size[0]
  PIN auto_buffer_out_d_bits_size[1]
    DIRECTION INPUT ;
    USE SIGNAL ;
    ANTENNAGATEAREA 0.990000 ;
    PORT
      LAYER met2 ;
        RECT 3117.050 0.000 3117.330 4.000 ;
    END
  END auto_buffer_out_d_bits_size[1]
  PIN auto_buffer_out_d_bits_size[2]
    DIRECTION INPUT ;
    USE SIGNAL ;
    ANTENNAGATEAREA 0.990000 ;
    PORT
      LAYER met2 ;
        RECT 653.750 2596.000 654.030 2600.000 ;
    END
  END auto_buffer_out_d_bits_size[2]
  PIN auto_buffer_out_d_bits_size[3]
    DIRECTION INPUT ;
    USE SIGNAL ;
    ANTENNAGATEAREA 0.990000 ;
    PORT
      LAYER met3 ;
        RECT 6996.000 1115.240 7000.000 1115.840 ;
    END
  END auto_buffer_out_d_bits_size[3]
  PIN auto_buffer_out_d_bits_source[0]
    DIRECTION INPUT ;
    USE SIGNAL ;
    ANTENNAGATEAREA 0.213000 ;
    PORT
      LAYER met2 ;
        RECT 2592.190 0.000 2592.470 4.000 ;
    END
  END auto_buffer_out_d_bits_source[0]
  PIN auto_buffer_out_d_bits_source[1]
    DIRECTION INPUT ;
    USE SIGNAL ;
    ANTENNAGATEAREA 0.990000 ;
    PORT
      LAYER met2 ;
        RECT 5683.390 0.000 5683.670 4.000 ;
    END
  END auto_buffer_out_d_bits_source[1]
  PIN auto_buffer_out_d_ready
    DIRECTION OUTPUT TRISTATE ;
    USE SIGNAL ;
    ANTENNADIFFAREA 0.340600 ;
    PORT
      LAYER met2 ;
        RECT 4881.610 0.000 4881.890 4.000 ;
    END
  END auto_buffer_out_d_ready
  PIN auto_buffer_out_d_valid
    DIRECTION INPUT ;
    USE SIGNAL ;
    ANTENNAGATEAREA 0.990000 ;
    PORT
      LAYER met2 ;
        RECT 6288.750 0.000 6289.030 4.000 ;
    END
  END auto_buffer_out_d_valid
  PIN auto_buffer_out_e_bits_sink[0]
    DIRECTION OUTPUT TRISTATE ;
    USE SIGNAL ;
    ANTENNADIFFAREA 0.340600 ;
    PORT
      LAYER met2 ;
        RECT 6011.830 0.000 6012.110 4.000 ;
    END
  END auto_buffer_out_e_bits_sink[0]
  PIN auto_buffer_out_e_bits_sink[1]
    DIRECTION OUTPUT TRISTATE ;
    USE SIGNAL ;
    ANTENNADIFFAREA 0.340600 ;
    PORT
      LAYER met2 ;
        RECT 1928.870 0.000 1929.150 4.000 ;
    END
  END auto_buffer_out_e_bits_sink[1]
  PIN auto_buffer_out_e_ready
    DIRECTION INPUT ;
    USE SIGNAL ;
    ANTENNAGATEAREA 0.990000 ;
    PORT
      LAYER met2 ;
        RECT 1536.030 2596.000 1536.310 2600.000 ;
    END
  END auto_buffer_out_e_ready
  PIN auto_buffer_out_e_valid
    DIRECTION OUTPUT TRISTATE ;
    USE SIGNAL ;
    ANTENNADIFFAREA 0.340600 ;
    PORT
      LAYER met2 ;
        RECT 3612.930 0.000 3613.210 4.000 ;
    END
  END auto_buffer_out_e_valid
  PIN auto_hartid_in
    DIRECTION INPUT ;
    USE SIGNAL ;
    ANTENNAGATEAREA 0.852000 ;
    PORT
      LAYER met2 ;
        RECT 3799.690 2596.000 3799.970 2600.000 ;
    END
  END auto_hartid_in
  PIN auto_int_local_in_0_0
    DIRECTION INPUT ;
    USE SIGNAL ;
    ANTENNAGATEAREA 0.990000 ;
    PORT
      LAYER met2 ;
        RECT 4192.530 0.000 4192.810 4.000 ;
    END
  END auto_int_local_in_0_0
  PIN auto_int_local_in_1_0
    DIRECTION INPUT ;
    USE SIGNAL ;
    ANTENNAGATEAREA 0.990000 ;
    PORT
      LAYER met2 ;
        RECT 6668.710 2596.000 6668.990 2600.000 ;
    END
  END auto_int_local_in_1_0
  PIN auto_int_local_in_1_1
    DIRECTION INPUT ;
    USE SIGNAL ;
    ANTENNAGATEAREA 0.990000 ;
    PORT
      LAYER met3 ;
        RECT 0.000 812.640 4.000 813.240 ;
    END
  END auto_int_local_in_1_1
  PIN auto_int_local_in_2_0
    DIRECTION INPUT ;
    USE SIGNAL ;
    ANTENNAGATEAREA 0.990000 ;
    PORT
      LAYER met2 ;
        RECT 5129.550 0.000 5129.830 4.000 ;
    END
  END auto_int_local_in_2_0
  PIN auto_int_local_in_3_0
    DIRECTION INPUT ;
    USE SIGNAL ;
    ANTENNAGATEAREA 0.852000 ;
    PORT
      LAYER met3 ;
        RECT 6996.000 850.040 7000.000 850.640 ;
    END
  END auto_int_local_in_3_0
  PIN auto_trace_source_out_insns_0_cause[0]
    DIRECTION OUTPUT TRISTATE ;
    USE SIGNAL ;
    ANTENNADIFFAREA 0.340600 ;
    PORT
      LAYER met2 ;
        RECT 2730.650 0.000 2730.930 4.000 ;
    END
  END auto_trace_source_out_insns_0_cause[0]
  PIN auto_trace_source_out_insns_0_cause[10]
    DIRECTION OUTPUT TRISTATE ;
    USE SIGNAL ;
    PORT
      LAYER met3 ;
        RECT 0.000 843.240 4.000 843.840 ;
    END
  END auto_trace_source_out_insns_0_cause[10]
  PIN auto_trace_source_out_insns_0_cause[11]
    DIRECTION OUTPUT TRISTATE ;
    USE SIGNAL ;
    PORT
      LAYER met2 ;
        RECT 3880.190 2596.000 3880.470 2600.000 ;
    END
  END auto_trace_source_out_insns_0_cause[11]
  PIN auto_trace_source_out_insns_0_cause[12]
    DIRECTION OUTPUT TRISTATE ;
    USE SIGNAL ;
    PORT
      LAYER met3 ;
        RECT 0.000 989.440 4.000 990.040 ;
    END
  END auto_trace_source_out_insns_0_cause[12]
  PIN auto_trace_source_out_insns_0_cause[13]
    DIRECTION OUTPUT TRISTATE ;
    USE SIGNAL ;
    PORT
      LAYER met2 ;
        RECT 2392.550 2596.000 2392.830 2600.000 ;
    END
  END auto_trace_source_out_insns_0_cause[13]
  PIN auto_trace_source_out_insns_0_cause[14]
    DIRECTION OUTPUT TRISTATE ;
    USE SIGNAL ;
    PORT
      LAYER met2 ;
        RECT 4330.990 0.000 4331.270 4.000 ;
    END
  END auto_trace_source_out_insns_0_cause[14]
  PIN auto_trace_source_out_insns_0_cause[15]
    DIRECTION OUTPUT TRISTATE ;
    USE SIGNAL ;
    PORT
      LAYER met2 ;
        RECT 3909.170 2596.000 3909.450 2600.000 ;
    END
  END auto_trace_source_out_insns_0_cause[15]
  PIN auto_trace_source_out_insns_0_cause[16]
    DIRECTION OUTPUT TRISTATE ;
    USE SIGNAL ;
    PORT
      LAYER met2 ;
        RECT 2556.770 2596.000 2557.050 2600.000 ;
    END
  END auto_trace_source_out_insns_0_cause[16]
  PIN auto_trace_source_out_insns_0_cause[17]
    DIRECTION OUTPUT TRISTATE ;
    USE SIGNAL ;
    PORT
      LAYER met2 ;
        RECT 6530.250 2596.000 6530.530 2600.000 ;
    END
  END auto_trace_source_out_insns_0_cause[17]
  PIN auto_trace_source_out_insns_0_cause[18]
    DIRECTION OUTPUT TRISTATE ;
    USE SIGNAL ;
    PORT
      LAYER met2 ;
        RECT 3970.350 0.000 3970.630 4.000 ;
    END
  END auto_trace_source_out_insns_0_cause[18]
  PIN auto_trace_source_out_insns_0_cause[19]
    DIRECTION OUTPUT TRISTATE ;
    USE SIGNAL ;
    PORT
      LAYER met2 ;
        RECT 6649.390 0.000 6649.670 4.000 ;
    END
  END auto_trace_source_out_insns_0_cause[19]
  PIN auto_trace_source_out_insns_0_cause[1]
    DIRECTION OUTPUT TRISTATE ;
    USE SIGNAL ;
    ANTENNADIFFAREA 0.340600 ;
    PORT
      LAYER met2 ;
        RECT 5535.270 2596.000 5535.550 2600.000 ;
    END
  END auto_trace_source_out_insns_0_cause[1]
  PIN auto_trace_source_out_insns_0_cause[20]
    DIRECTION OUTPUT TRISTATE ;
    USE SIGNAL ;
    PORT
      LAYER met2 ;
        RECT 5400.030 2596.000 5400.310 2600.000 ;
    END
  END auto_trace_source_out_insns_0_cause[20]
  PIN auto_trace_source_out_insns_0_cause[21]
    DIRECTION OUTPUT TRISTATE ;
    USE SIGNAL ;
    PORT
      LAYER met2 ;
        RECT 624.770 2596.000 625.050 2600.000 ;
    END
  END auto_trace_source_out_insns_0_cause[21]
  PIN auto_trace_source_out_insns_0_cause[22]
    DIRECTION OUTPUT TRISTATE ;
    USE SIGNAL ;
    PORT
      LAYER met2 ;
        RECT 2315.270 0.000 2315.550 4.000 ;
    END
  END auto_trace_source_out_insns_0_cause[22]
  PIN auto_trace_source_out_insns_0_cause[23]
    DIRECTION OUTPUT TRISTATE ;
    USE SIGNAL ;
    PORT
      LAYER met2 ;
        RECT 3052.650 2596.000 3052.930 2600.000 ;
    END
  END auto_trace_source_out_insns_0_cause[23]
  PIN auto_trace_source_out_insns_0_cause[24]
    DIRECTION OUTPUT TRISTATE ;
    USE SIGNAL ;
    PORT
      LAYER met2 ;
        RECT 6420.770 2596.000 6421.050 2600.000 ;
    END
  END auto_trace_source_out_insns_0_cause[24]
  PIN auto_trace_source_out_insns_0_cause[25]
    DIRECTION OUTPUT TRISTATE ;
    USE SIGNAL ;
    PORT
      LAYER met2 ;
        RECT 5709.150 0.000 5709.430 4.000 ;
    END
  END auto_trace_source_out_insns_0_cause[25]
  PIN auto_trace_source_out_insns_0_cause[26]
    DIRECTION OUTPUT TRISTATE ;
    USE SIGNAL ;
    PORT
      LAYER met2 ;
        RECT 5509.510 2596.000 5509.790 2600.000 ;
    END
  END auto_trace_source_out_insns_0_cause[26]
  PIN auto_trace_source_out_insns_0_cause[27]
    DIRECTION OUTPUT TRISTATE ;
    USE SIGNAL ;
    PORT
      LAYER met2 ;
        RECT 1323.510 0.000 1323.790 4.000 ;
    END
  END auto_trace_source_out_insns_0_cause[27]
  PIN auto_trace_source_out_insns_0_cause[28]
    DIRECTION OUTPUT TRISTATE ;
    USE SIGNAL ;
    PORT
      LAYER met3 ;
        RECT 0.000 1424.640 4.000 1425.240 ;
    END
  END auto_trace_source_out_insns_0_cause[28]
  PIN auto_trace_source_out_insns_0_cause[29]
    DIRECTION OUTPUT TRISTATE ;
    USE SIGNAL ;
    PORT
      LAYER met2 ;
        RECT 985.410 2596.000 985.690 2600.000 ;
    END
  END auto_trace_source_out_insns_0_cause[29]
  PIN auto_trace_source_out_insns_0_cause[2]
    DIRECTION OUTPUT TRISTATE ;
    USE SIGNAL ;
    ANTENNADIFFAREA 0.340600 ;
    PORT
      LAYER met2 ;
        RECT 6227.570 2596.000 6227.850 2600.000 ;
    END
  END auto_trace_source_out_insns_0_cause[2]
  PIN auto_trace_source_out_insns_0_cause[30]
    DIRECTION OUTPUT TRISTATE ;
    USE SIGNAL ;
    PORT
      LAYER met2 ;
        RECT 3384.310 2596.000 3384.590 2600.000 ;
    END
  END auto_trace_source_out_insns_0_cause[30]
  PIN auto_trace_source_out_insns_0_cause[31]
    DIRECTION OUTPUT TRISTATE ;
    USE SIGNAL ;
    PORT
      LAYER met2 ;
        RECT 4627.230 2596.000 4627.510 2600.000 ;
    END
  END auto_trace_source_out_insns_0_cause[31]
  PIN auto_trace_source_out_insns_0_cause[32]
    DIRECTION OUTPUT TRISTATE ;
    USE SIGNAL ;
    PORT
      LAYER met3 ;
        RECT 0.000 200.640 4.000 201.240 ;
    END
  END auto_trace_source_out_insns_0_cause[32]
  PIN auto_trace_source_out_insns_0_cause[33]
    DIRECTION OUTPUT TRISTATE ;
    USE SIGNAL ;
    PORT
      LAYER met2 ;
        RECT 2041.570 0.000 2041.850 4.000 ;
    END
  END auto_trace_source_out_insns_0_cause[33]
  PIN auto_trace_source_out_insns_0_cause[34]
    DIRECTION OUTPUT TRISTATE ;
    USE SIGNAL ;
    PORT
      LAYER met3 ;
        RECT 6996.000 2016.240 7000.000 2016.840 ;
    END
  END auto_trace_source_out_insns_0_cause[34]
  PIN auto_trace_source_out_insns_0_cause[35]
    DIRECTION OUTPUT TRISTATE ;
    USE SIGNAL ;
    PORT
      LAYER met2 ;
        RECT 3722.410 0.000 3722.690 4.000 ;
    END
  END auto_trace_source_out_insns_0_cause[35]
  PIN auto_trace_source_out_insns_0_cause[36]
    DIRECTION OUTPUT TRISTATE ;
    USE SIGNAL ;
    PORT
      LAYER met3 ;
        RECT 6996.000 734.440 7000.000 735.040 ;
    END
  END auto_trace_source_out_insns_0_cause[36]
  PIN auto_trace_source_out_insns_0_cause[37]
    DIRECTION OUTPUT TRISTATE ;
    USE SIGNAL ;
    PORT
      LAYER met2 ;
        RECT 991.850 0.000 992.130 4.000 ;
    END
  END auto_trace_source_out_insns_0_cause[37]
  PIN auto_trace_source_out_insns_0_cause[38]
    DIRECTION OUTPUT TRISTATE ;
    USE SIGNAL ;
    PORT
      LAYER met3 ;
        RECT 0.000 727.640 4.000 728.240 ;
    END
  END auto_trace_source_out_insns_0_cause[38]
  PIN auto_trace_source_out_insns_0_cause[39]
    DIRECTION OUTPUT TRISTATE ;
    USE SIGNAL ;
    PORT
      LAYER met2 ;
        RECT 1619.750 2596.000 1620.030 2600.000 ;
    END
  END auto_trace_source_out_insns_0_cause[39]
  PIN auto_trace_source_out_insns_0_cause[3]
    DIRECTION OUTPUT TRISTATE ;
    USE SIGNAL ;
    ANTENNADIFFAREA 0.340600 ;
    PORT
      LAYER met3 ;
        RECT 0.000 523.640 4.000 524.240 ;
    END
  END auto_trace_source_out_insns_0_cause[3]
  PIN auto_trace_source_out_insns_0_cause[40]
    DIRECTION OUTPUT TRISTATE ;
    USE SIGNAL ;
    PORT
      LAYER met2 ;
        RECT 6639.730 2596.000 6640.010 2600.000 ;
    END
  END auto_trace_source_out_insns_0_cause[40]
  PIN auto_trace_source_out_insns_0_cause[41]
    DIRECTION OUTPUT TRISTATE ;
    USE SIGNAL ;
    PORT
      LAYER met3 ;
        RECT 6996.000 34.040 7000.000 34.640 ;
    END
  END auto_trace_source_out_insns_0_cause[41]
  PIN auto_trace_source_out_insns_0_cause[42]
    DIRECTION OUTPUT TRISTATE ;
    USE SIGNAL ;
    PORT
      LAYER met2 ;
        RECT 2502.030 2596.000 2502.310 2600.000 ;
    END
  END auto_trace_source_out_insns_0_cause[42]
  PIN auto_trace_source_out_insns_0_cause[43]
    DIRECTION OUTPUT TRISTATE ;
    USE SIGNAL ;
    PORT
      LAYER met3 ;
        RECT 6996.000 969.040 7000.000 969.640 ;
    END
  END auto_trace_source_out_insns_0_cause[43]
  PIN auto_trace_source_out_insns_0_cause[44]
    DIRECTION OUTPUT TRISTATE ;
    USE SIGNAL ;
    PORT
      LAYER met2 ;
        RECT 3255.510 0.000 3255.790 4.000 ;
    END
  END auto_trace_source_out_insns_0_cause[44]
  PIN auto_trace_source_out_insns_0_cause[45]
    DIRECTION OUTPUT TRISTATE ;
    USE SIGNAL ;
    PORT
      LAYER met2 ;
        RECT 1819.390 0.000 1819.670 4.000 ;
    END
  END auto_trace_source_out_insns_0_cause[45]
  PIN auto_trace_source_out_insns_0_cause[46]
    DIRECTION OUTPUT TRISTATE ;
    USE SIGNAL ;
    PORT
      LAYER met2 ;
        RECT 4514.530 2596.000 4514.810 2600.000 ;
    END
  END auto_trace_source_out_insns_0_cause[46]
  PIN auto_trace_source_out_insns_0_cause[47]
    DIRECTION OUTPUT TRISTATE ;
    USE SIGNAL ;
    PORT
      LAYER met3 ;
        RECT 6996.000 2308.640 7000.000 2309.240 ;
    END
  END auto_trace_source_out_insns_0_cause[47]
  PIN auto_trace_source_out_insns_0_cause[48]
    DIRECTION OUTPUT TRISTATE ;
    USE SIGNAL ;
    PORT
      LAYER met2 ;
        RECT 2804.710 2596.000 2804.990 2600.000 ;
    END
  END auto_trace_source_out_insns_0_cause[48]
  PIN auto_trace_source_out_insns_0_cause[49]
    DIRECTION OUTPUT TRISTATE ;
    USE SIGNAL ;
    PORT
      LAYER met3 ;
        RECT 6996.000 472.640 7000.000 473.240 ;
    END
  END auto_trace_source_out_insns_0_cause[49]
  PIN auto_trace_source_out_insns_0_cause[4]
    DIRECTION OUTPUT TRISTATE ;
    USE SIGNAL ;
    ANTENNADIFFAREA 0.340600 ;
    PORT
      LAYER met2 ;
        RECT 4163.550 0.000 4163.830 4.000 ;
    END
  END auto_trace_source_out_insns_0_cause[4]
  PIN auto_trace_source_out_insns_0_cause[50]
    DIRECTION OUTPUT TRISTATE ;
    USE SIGNAL ;
    PORT
      LAYER met2 ;
        RECT 460.550 2596.000 460.830 2600.000 ;
    END
  END auto_trace_source_out_insns_0_cause[50]
  PIN auto_trace_source_out_insns_0_cause[51]
    DIRECTION OUTPUT TRISTATE ;
    USE SIGNAL ;
    PORT
      LAYER met3 ;
        RECT 6996.000 1581.040 7000.000 1581.640 ;
    END
  END auto_trace_source_out_insns_0_cause[51]
  PIN auto_trace_source_out_insns_0_cause[52]
    DIRECTION OUTPUT TRISTATE ;
    USE SIGNAL ;
    PORT
      LAYER met3 ;
        RECT 0.000 581.440 4.000 582.040 ;
    END
  END auto_trace_source_out_insns_0_cause[52]
  PIN auto_trace_source_out_insns_0_cause[53]
    DIRECTION OUTPUT TRISTATE ;
    USE SIGNAL ;
    PORT
      LAYER met2 ;
        RECT 412.250 0.000 412.530 4.000 ;
    END
  END auto_trace_source_out_insns_0_cause[53]
  PIN auto_trace_source_out_insns_0_cause[54]
    DIRECTION OUTPUT TRISTATE ;
    USE SIGNAL ;
    PORT
      LAYER met2 ;
        RECT 2701.670 0.000 2701.950 4.000 ;
    END
  END auto_trace_source_out_insns_0_cause[54]
  PIN auto_trace_source_out_insns_0_cause[55]
    DIRECTION OUTPUT TRISTATE ;
    USE SIGNAL ;
    PORT
      LAYER met2 ;
        RECT 1432.990 0.000 1433.270 4.000 ;
    END
  END auto_trace_source_out_insns_0_cause[55]
  PIN auto_trace_source_out_insns_0_cause[56]
    DIRECTION OUTPUT TRISTATE ;
    USE SIGNAL ;
    PORT
      LAYER met2 ;
        RECT 5902.350 0.000 5902.630 4.000 ;
    END
  END auto_trace_source_out_insns_0_cause[56]
  PIN auto_trace_source_out_insns_0_cause[57]
    DIRECTION OUTPUT TRISTATE ;
    USE SIGNAL ;
    PORT
      LAYER met2 ;
        RECT 328.530 0.000 328.810 4.000 ;
    END
  END auto_trace_source_out_insns_0_cause[57]
  PIN auto_trace_source_out_insns_0_cause[58]
    DIRECTION OUTPUT TRISTATE ;
    USE SIGNAL ;
    PORT
      LAYER met2 ;
        RECT 1487.730 0.000 1488.010 4.000 ;
    END
  END auto_trace_source_out_insns_0_cause[58]
  PIN auto_trace_source_out_insns_0_cause[59]
    DIRECTION OUTPUT TRISTATE ;
    USE SIGNAL ;
    PORT
      LAYER met2 ;
        RECT 5792.870 0.000 5793.150 4.000 ;
    END
  END auto_trace_source_out_insns_0_cause[59]
  PIN auto_trace_source_out_insns_0_cause[5]
    DIRECTION OUTPUT TRISTATE ;
    USE SIGNAL ;
    PORT
      LAYER met2 ;
        RECT 6807.170 2596.000 6807.450 2600.000 ;
    END
  END auto_trace_source_out_insns_0_cause[5]
  PIN auto_trace_source_out_insns_0_cause[60]
    DIRECTION OUTPUT TRISTATE ;
    USE SIGNAL ;
    PORT
      LAYER met3 ;
        RECT 6996.000 122.440 7000.000 123.040 ;
    END
  END auto_trace_source_out_insns_0_cause[60]
  PIN auto_trace_source_out_insns_0_cause[61]
    DIRECTION OUTPUT TRISTATE ;
    USE SIGNAL ;
    PORT
      LAYER met3 ;
        RECT 0.000 2475.240 4.000 2475.840 ;
    END
  END auto_trace_source_out_insns_0_cause[61]
  PIN auto_trace_source_out_insns_0_cause[62]
    DIRECTION OUTPUT TRISTATE ;
    USE SIGNAL ;
    PORT
      LAYER met2 ;
        RECT 6729.890 0.000 6730.170 4.000 ;
    END
  END auto_trace_source_out_insns_0_cause[62]
  PIN auto_trace_source_out_insns_0_cause[63]
    DIRECTION OUTPUT TRISTATE ;
    USE SIGNAL ;
    ANTENNADIFFAREA 0.340600 ;
    PORT
      LAYER met2 ;
        RECT 3503.450 0.000 3503.730 4.000 ;
    END
  END auto_trace_source_out_insns_0_cause[63]
  PIN auto_trace_source_out_insns_0_cause[6]
    DIRECTION OUTPUT TRISTATE ;
    USE SIGNAL ;
    PORT
      LAYER met2 ;
        RECT 5895.910 2596.000 5896.190 2600.000 ;
    END
  END auto_trace_source_out_insns_0_cause[6]
  PIN auto_trace_source_out_insns_0_cause[7]
    DIRECTION OUTPUT TRISTATE ;
    USE SIGNAL ;
    PORT
      LAYER met2 ;
        RECT 3226.530 0.000 3226.810 4.000 ;
    END
  END auto_trace_source_out_insns_0_cause[7]
  PIN auto_trace_source_out_insns_0_cause[8]
    DIRECTION OUTPUT TRISTATE ;
    USE SIGNAL ;
    PORT
      LAYER met3 ;
        RECT 0.000 1863.240 4.000 1863.840 ;
    END
  END auto_trace_source_out_insns_0_cause[8]
  PIN auto_trace_source_out_insns_0_cause[9]
    DIRECTION OUTPUT TRISTATE ;
    USE SIGNAL ;
    PORT
      LAYER met2 ;
        RECT 6501.270 2596.000 6501.550 2600.000 ;
    END
  END auto_trace_source_out_insns_0_cause[9]
  PIN auto_trace_source_out_insns_0_exception
    DIRECTION OUTPUT TRISTATE ;
    USE SIGNAL ;
    ANTENNADIFFAREA 0.340600 ;
    PORT
      LAYER met2 ;
        RECT 515.290 2596.000 515.570 2600.000 ;
    END
  END auto_trace_source_out_insns_0_exception
  PIN auto_trace_source_out_insns_0_iaddr[0]
    DIRECTION OUTPUT TRISTATE ;
    USE SIGNAL ;
    PORT
      LAYER met2 ;
        RECT 4681.970 2596.000 4682.250 2600.000 ;
    END
  END auto_trace_source_out_insns_0_iaddr[0]
  PIN auto_trace_source_out_insns_0_iaddr[10]
    DIRECTION OUTPUT TRISTATE ;
    USE SIGNAL ;
    ANTENNADIFFAREA 0.340600 ;
    PORT
      LAYER met2 ;
        RECT 6556.010 2596.000 6556.290 2600.000 ;
    END
  END auto_trace_source_out_insns_0_iaddr[10]
  PIN auto_trace_source_out_insns_0_iaddr[11]
    DIRECTION OUTPUT TRISTATE ;
    USE SIGNAL ;
    ANTENNADIFFAREA 0.340600 ;
    PORT
      LAYER met2 ;
        RECT 2943.170 2596.000 2943.450 2600.000 ;
    END
  END auto_trace_source_out_insns_0_iaddr[11]
  PIN auto_trace_source_out_insns_0_iaddr[12]
    DIRECTION OUTPUT TRISTATE ;
    USE SIGNAL ;
    ANTENNADIFFAREA 0.340600 ;
    PORT
      LAYER met2 ;
        RECT 1655.170 0.000 1655.450 4.000 ;
    END
  END auto_trace_source_out_insns_0_iaddr[12]
  PIN auto_trace_source_out_insns_0_iaddr[13]
    DIRECTION OUTPUT TRISTATE ;
    USE SIGNAL ;
    ANTENNADIFFAREA 0.340600 ;
    PORT
      LAYER met2 ;
        RECT 5351.730 0.000 5352.010 4.000 ;
    END
  END auto_trace_source_out_insns_0_iaddr[13]
  PIN auto_trace_source_out_insns_0_iaddr[14]
    DIRECTION OUTPUT TRISTATE ;
    USE SIGNAL ;
    ANTENNADIFFAREA 0.340600 ;
    PORT
      LAYER met2 ;
        RECT 6591.430 0.000 6591.710 4.000 ;
    END
  END auto_trace_source_out_insns_0_iaddr[14]
  PIN auto_trace_source_out_insns_0_iaddr[15]
    DIRECTION OUTPUT TRISTATE ;
    USE SIGNAL ;
    ANTENNADIFFAREA 0.340600 ;
    PORT
      LAYER met3 ;
        RECT 6996.000 911.240 7000.000 911.840 ;
    END
  END auto_trace_source_out_insns_0_iaddr[15]
  PIN auto_trace_source_out_insns_0_iaddr[16]
    DIRECTION OUTPUT TRISTATE ;
    USE SIGNAL ;
    ANTENNADIFFAREA 0.340600 ;
    PORT
      LAYER met3 ;
        RECT 0.000 1978.840 4.000 1979.440 ;
    END
  END auto_trace_source_out_insns_0_iaddr[16]
  PIN auto_trace_source_out_insns_0_iaddr[17]
    DIRECTION OUTPUT TRISTATE ;
    USE SIGNAL ;
    ANTENNADIFFAREA 0.340600 ;
    PORT
      LAYER met3 ;
        RECT 0.000 785.440 4.000 786.040 ;
    END
  END auto_trace_source_out_insns_0_iaddr[17]
  PIN auto_trace_source_out_insns_0_iaddr[18]
    DIRECTION OUTPUT TRISTATE ;
    USE SIGNAL ;
    ANTENNADIFFAREA 0.340600 ;
    PORT
      LAYER met2 ;
        RECT 2031.910 2596.000 2032.190 2600.000 ;
    END
  END auto_trace_source_out_insns_0_iaddr[18]
  PIN auto_trace_source_out_insns_0_iaddr[19]
    DIRECTION OUTPUT TRISTATE ;
    USE SIGNAL ;
    ANTENNADIFFAREA 0.340600 ;
    PORT
      LAYER met2 ;
        RECT 956.430 2596.000 956.710 2600.000 ;
    END
  END auto_trace_source_out_insns_0_iaddr[19]
  PIN auto_trace_source_out_insns_0_iaddr[1]
    DIRECTION OUTPUT TRISTATE ;
    USE SIGNAL ;
    ANTENNADIFFAREA 0.340600 ;
    PORT
      LAYER met2 ;
        RECT 6114.870 2596.000 6115.150 2600.000 ;
    END
  END auto_trace_source_out_insns_0_iaddr[1]
  PIN auto_trace_source_out_insns_0_iaddr[20]
    DIRECTION OUTPUT TRISTATE ;
    USE SIGNAL ;
    ANTENNADIFFAREA 0.340600 ;
    PORT
      LAYER met3 ;
        RECT 0.000 873.840 4.000 874.440 ;
    END
  END auto_trace_source_out_insns_0_iaddr[20]
  PIN auto_trace_source_out_insns_0_iaddr[21]
    DIRECTION OUTPUT TRISTATE ;
    USE SIGNAL ;
    ANTENNADIFFAREA 0.340600 ;
    PORT
      LAYER met2 ;
        RECT 4604.690 0.000 4604.970 4.000 ;
    END
  END auto_trace_source_out_insns_0_iaddr[21]
  PIN auto_trace_source_out_insns_0_iaddr[22]
    DIRECTION OUTPUT TRISTATE ;
    USE SIGNAL ;
    ANTENNADIFFAREA 0.340600 ;
    PORT
      LAYER met2 ;
        RECT 541.050 2596.000 541.330 2600.000 ;
    END
  END auto_trace_source_out_insns_0_iaddr[22]
  PIN auto_trace_source_out_insns_0_iaddr[23]
    DIRECTION OUTPUT TRISTATE ;
    USE SIGNAL ;
    ANTENNADIFFAREA 0.340600 ;
    PORT
      LAYER met2 ;
        RECT 4440.470 0.000 4440.750 4.000 ;
    END
  END auto_trace_source_out_insns_0_iaddr[23]
  PIN auto_trace_source_out_insns_0_iaddr[24]
    DIRECTION OUTPUT TRISTATE ;
    USE SIGNAL ;
    ANTENNADIFFAREA 0.340600 ;
    PORT
      LAYER met2 ;
        RECT 5296.990 0.000 5297.270 4.000 ;
    END
  END auto_trace_source_out_insns_0_iaddr[24]
  PIN auto_trace_source_out_insns_0_iaddr[25]
    DIRECTION OUTPUT TRISTATE ;
    USE SIGNAL ;
    ANTENNADIFFAREA 0.340600 ;
    PORT
      LAYER met2 ;
        RECT 908.130 0.000 908.410 4.000 ;
    END
  END auto_trace_source_out_insns_0_iaddr[25]
  PIN auto_trace_source_out_insns_0_iaddr[26]
    DIRECTION OUTPUT TRISTATE ;
    USE SIGNAL ;
    ANTENNADIFFAREA 0.340600 ;
    PORT
      LAYER met2 ;
        RECT 1349.270 0.000 1349.550 4.000 ;
    END
  END auto_trace_source_out_insns_0_iaddr[26]
  PIN auto_trace_source_out_insns_0_iaddr[27]
    DIRECTION OUTPUT TRISTATE ;
    USE SIGNAL ;
    ANTENNADIFFAREA 0.340600 ;
    PORT
      LAYER met2 ;
        RECT 4743.150 0.000 4743.430 4.000 ;
    END
  END auto_trace_source_out_insns_0_iaddr[27]
  PIN auto_trace_source_out_insns_0_iaddr[28]
    DIRECTION OUTPUT TRISTATE ;
    USE SIGNAL ;
    ANTENNADIFFAREA 0.340600 ;
    PORT
      LAYER met2 ;
        RECT 6481.950 0.000 6482.230 4.000 ;
    END
  END auto_trace_source_out_insns_0_iaddr[28]
  PIN auto_trace_source_out_insns_0_iaddr[29]
    DIRECTION OUTPUT TRISTATE ;
    USE SIGNAL ;
    ANTENNADIFFAREA 0.340600 ;
    PORT
      LAYER met2 ;
        RECT 679.510 2596.000 679.790 2600.000 ;
    END
  END auto_trace_source_out_insns_0_iaddr[29]
  PIN auto_trace_source_out_insns_0_iaddr[2]
    DIRECTION OUTPUT TRISTATE ;
    USE SIGNAL ;
    ANTENNADIFFAREA 0.340600 ;
    PORT
      LAYER met2 ;
        RECT 4157.110 2596.000 4157.390 2600.000 ;
    END
  END auto_trace_source_out_insns_0_iaddr[2]
  PIN auto_trace_source_out_insns_0_iaddr[30]
    DIRECTION OUTPUT TRISTATE ;
    USE SIGNAL ;
    ANTENNADIFFAREA 0.340600 ;
    PORT
      LAYER met2 ;
        RECT 3963.910 2596.000 3964.190 2600.000 ;
    END
  END auto_trace_source_out_insns_0_iaddr[30]
  PIN auto_trace_source_out_insns_0_iaddr[31]
    DIRECTION OUTPUT TRISTATE ;
    USE SIGNAL ;
    ANTENNADIFFAREA 0.340600 ;
    PORT
      LAYER met2 ;
        RECT 3162.130 2596.000 3162.410 2600.000 ;
    END
  END auto_trace_source_out_insns_0_iaddr[31]
  PIN auto_trace_source_out_insns_0_iaddr[32]
    DIRECTION OUTPUT TRISTATE ;
    USE SIGNAL ;
    ANTENNADIFFAREA 0.340600 ;
    PORT
      LAYER met2 ;
        RECT 1680.930 0.000 1681.210 4.000 ;
    END
  END auto_trace_source_out_insns_0_iaddr[32]
  PIN auto_trace_source_out_insns_0_iaddr[33]
    DIRECTION OUTPUT TRISTATE ;
    USE SIGNAL ;
    ANTENNADIFFAREA 0.340600 ;
    PORT
      LAYER met2 ;
        RECT 6971.390 2596.000 6971.670 2600.000 ;
    END
  END auto_trace_source_out_insns_0_iaddr[33]
  PIN auto_trace_source_out_insns_0_iaddr[34]
    DIRECTION OUTPUT TRISTATE ;
    USE SIGNAL ;
    ANTENNADIFFAREA 0.340600 ;
    PORT
      LAYER met2 ;
        RECT 5213.270 0.000 5213.550 4.000 ;
    END
  END auto_trace_source_out_insns_0_iaddr[34]
  PIN auto_trace_source_out_insns_0_iaddr[35]
    DIRECTION OUTPUT TRISTATE ;
    USE SIGNAL ;
    ANTENNADIFFAREA 0.340600 ;
    PORT
      LAYER met2 ;
        RECT 2914.190 2596.000 2914.470 2600.000 ;
    END
  END auto_trace_source_out_insns_0_iaddr[35]
  PIN auto_trace_source_out_insns_0_iaddr[36]
    DIRECTION OUTPUT TRISTATE ;
    USE SIGNAL ;
    ANTENNADIFFAREA 0.340600 ;
    PORT
      LAYER met3 ;
        RECT 0.000 377.440 4.000 378.040 ;
    END
  END auto_trace_source_out_insns_0_iaddr[36]
  PIN auto_trace_source_out_insns_0_iaddr[37]
    DIRECTION OUTPUT TRISTATE ;
    USE SIGNAL ;
    ANTENNADIFFAREA 0.340600 ;
    PORT
      LAYER met2 ;
        RECT 212.610 2596.000 212.890 2600.000 ;
    END
  END auto_trace_source_out_insns_0_iaddr[37]
  PIN auto_trace_source_out_insns_0_iaddr[38]
    DIRECTION OUTPUT TRISTATE ;
    USE SIGNAL ;
    ANTENNADIFFAREA 0.340600 ;
    PORT
      LAYER met2 ;
        RECT 5123.110 2596.000 5123.390 2600.000 ;
    END
  END auto_trace_source_out_insns_0_iaddr[38]
  PIN auto_trace_source_out_insns_0_iaddr[39]
    DIRECTION OUTPUT TRISTATE ;
    USE SIGNAL ;
    ANTENNADIFFAREA 0.340600 ;
    PORT
      LAYER met2 ;
        RECT 901.690 2596.000 901.970 2600.000 ;
    END
  END auto_trace_source_out_insns_0_iaddr[39]
  PIN auto_trace_source_out_insns_0_iaddr[3]
    DIRECTION OUTPUT TRISTATE ;
    USE SIGNAL ;
    ANTENNADIFFAREA 0.340600 ;
    PORT
      LAYER met2 ;
        RECT 5702.710 2596.000 5702.990 2600.000 ;
    END
  END auto_trace_source_out_insns_0_iaddr[3]
  PIN auto_trace_source_out_insns_0_iaddr[4]
    DIRECTION OUTPUT TRISTATE ;
    USE SIGNAL ;
    ANTENNADIFFAREA 0.340600 ;
    PORT
      LAYER met2 ;
        RECT 5950.650 2596.000 5950.930 2600.000 ;
    END
  END auto_trace_source_out_insns_0_iaddr[4]
  PIN auto_trace_source_out_insns_0_iaddr[5]
    DIRECTION OUTPUT TRISTATE ;
    USE SIGNAL ;
    ANTENNADIFFAREA 0.340600 ;
    PORT
      LAYER met3 ;
        RECT 0.000 1774.840 4.000 1775.440 ;
    END
  END auto_trace_source_out_insns_0_iaddr[5]
  PIN auto_trace_source_out_insns_0_iaddr[6]
    DIRECTION OUTPUT TRISTATE ;
    USE SIGNAL ;
    ANTENNADIFFAREA 0.340600 ;
    PORT
      LAYER met2 ;
        RECT 2949.610 0.000 2949.890 4.000 ;
    END
  END auto_trace_source_out_insns_0_iaddr[6]
  PIN auto_trace_source_out_insns_0_iaddr[7]
    DIRECTION OUTPUT TRISTATE ;
    USE SIGNAL ;
    ANTENNADIFFAREA 0.340600 ;
    PORT
      LAYER met2 ;
        RECT 4321.330 2596.000 4321.610 2600.000 ;
    END
  END auto_trace_source_out_insns_0_iaddr[7]
  PIN auto_trace_source_out_insns_0_iaddr[8]
    DIRECTION OUTPUT TRISTATE ;
    USE SIGNAL ;
    ANTENNADIFFAREA 0.340600 ;
    PORT
      LAYER met2 ;
        RECT 190.070 0.000 190.350 4.000 ;
    END
  END auto_trace_source_out_insns_0_iaddr[8]
  PIN auto_trace_source_out_insns_0_iaddr[9]
    DIRECTION OUTPUT TRISTATE ;
    USE SIGNAL ;
    ANTENNADIFFAREA 0.340600 ;
    PORT
      LAYER met2 ;
        RECT 54.830 0.000 55.110 4.000 ;
    END
  END auto_trace_source_out_insns_0_iaddr[9]
  PIN auto_trace_source_out_insns_0_insn[0]
    DIRECTION OUTPUT TRISTATE ;
    USE SIGNAL ;
    ANTENNADIFFAREA 0.340600 ;
    PORT
      LAYER met2 ;
        RECT 4385.730 0.000 4386.010 4.000 ;
    END
  END auto_trace_source_out_insns_0_insn[0]
  PIN auto_trace_source_out_insns_0_insn[10]
    DIRECTION OUTPUT TRISTATE ;
    USE SIGNAL ;
    ANTENNADIFFAREA 0.340600 ;
    PORT
      LAYER met2 ;
        RECT 267.350 2596.000 267.630 2600.000 ;
    END
  END auto_trace_source_out_insns_0_insn[10]
  PIN auto_trace_source_out_insns_0_insn[11]
    DIRECTION OUTPUT TRISTATE ;
    USE SIGNAL ;
    ANTENNADIFFAREA 0.340600 ;
    PORT
      LAYER met2 ;
        RECT 5931.330 0.000 5931.610 4.000 ;
    END
  END auto_trace_source_out_insns_0_insn[11]
  PIN auto_trace_source_out_insns_0_insn[12]
    DIRECTION OUTPUT TRISTATE ;
    USE SIGNAL ;
    ANTENNADIFFAREA 0.340600 ;
    PORT
      LAYER met2 ;
        RECT 4846.190 2596.000 4846.470 2600.000 ;
    END
  END auto_trace_source_out_insns_0_insn[12]
  PIN auto_trace_source_out_insns_0_insn[13]
    DIRECTION OUTPUT TRISTATE ;
    USE SIGNAL ;
    ANTENNADIFFAREA 0.340600 ;
    PORT
      LAYER met2 ;
        RECT 6372.470 0.000 6372.750 4.000 ;
    END
  END auto_trace_source_out_insns_0_insn[13]
  PIN auto_trace_source_out_insns_0_insn[14]
    DIRECTION OUTPUT TRISTATE ;
    USE SIGNAL ;
    ANTENNADIFFAREA 0.340600 ;
    PORT
      LAYER met2 ;
        RECT 1565.010 2596.000 1565.290 2600.000 ;
    END
  END auto_trace_source_out_insns_0_insn[14]
  PIN auto_trace_source_out_insns_0_insn[15]
    DIRECTION OUTPUT TRISTATE ;
    USE SIGNAL ;
    ANTENNADIFFAREA 0.340600 ;
    PORT
      LAYER met3 ;
        RECT 0.000 1628.640 4.000 1629.240 ;
    END
  END auto_trace_source_out_insns_0_insn[15]
  PIN auto_trace_source_out_insns_0_insn[16]
    DIRECTION OUTPUT TRISTATE ;
    USE SIGNAL ;
    ANTENNADIFFAREA 0.340600 ;
    PORT
      LAYER met2 ;
        RECT 1130.310 0.000 1130.590 4.000 ;
    END
  END auto_trace_source_out_insns_0_insn[16]
  PIN auto_trace_source_out_insns_0_insn[17]
    DIRECTION OUTPUT TRISTATE ;
    USE SIGNAL ;
    ANTENNADIFFAREA 0.340600 ;
    PORT
      LAYER met2 ;
        RECT 2508.470 0.000 2508.750 4.000 ;
    END
  END auto_trace_source_out_insns_0_insn[17]
  PIN auto_trace_source_out_insns_0_insn[18]
    DIRECTION OUTPUT TRISTATE ;
    USE SIGNAL ;
    ANTENNADIFFAREA 0.340600 ;
    PORT
      LAYER met2 ;
        RECT 4266.590 2596.000 4266.870 2600.000 ;
    END
  END auto_trace_source_out_insns_0_insn[18]
  PIN auto_trace_source_out_insns_0_insn[19]
    DIRECTION OUTPUT TRISTATE ;
    USE SIGNAL ;
    ANTENNADIFFAREA 0.340600 ;
    PORT
      LAYER met2 ;
        RECT 4495.210 0.000 4495.490 4.000 ;
    END
  END auto_trace_source_out_insns_0_insn[19]
  PIN auto_trace_source_out_insns_0_insn[1]
    DIRECTION OUTPUT TRISTATE ;
    USE SIGNAL ;
    ANTENNADIFFAREA 0.340600 ;
    PORT
      LAYER met2 ;
        RECT 2151.050 0.000 2151.330 4.000 ;
    END
  END auto_trace_source_out_insns_0_insn[1]
  PIN auto_trace_source_out_insns_0_insn[20]
    DIRECTION OUTPUT TRISTATE ;
    USE SIGNAL ;
    ANTENNADIFFAREA 0.340600 ;
    PORT
      LAYER met2 ;
        RECT 927.450 2596.000 927.730 2600.000 ;
    END
  END auto_trace_source_out_insns_0_insn[20]
  PIN auto_trace_source_out_insns_0_insn[21]
    DIRECTION OUTPUT TRISTATE ;
    USE SIGNAL ;
    ANTENNADIFFAREA 0.340600 ;
    PORT
      LAYER met3 ;
        RECT 0.000 289.040 4.000 289.640 ;
    END
  END auto_trace_source_out_insns_0_insn[21]
  PIN auto_trace_source_out_insns_0_insn[22]
    DIRECTION OUTPUT TRISTATE ;
    USE SIGNAL ;
    ANTENNADIFFAREA 0.340600 ;
    PORT
      LAYER met3 ;
        RECT 6996.000 2454.840 7000.000 2455.440 ;
    END
  END auto_trace_source_out_insns_0_insn[22]
  PIN auto_trace_source_out_insns_0_insn[23]
    DIRECTION OUTPUT TRISTATE ;
    USE SIGNAL ;
    ANTENNADIFFAREA 0.340600 ;
    PORT
      LAYER met2 ;
        RECT 4302.010 0.000 4302.290 4.000 ;
    END
  END auto_trace_source_out_insns_0_insn[23]
  PIN auto_trace_source_out_insns_0_insn[24]
    DIRECTION OUTPUT TRISTATE ;
    USE SIGNAL ;
    ANTENNADIFFAREA 0.340600 ;
    PORT
      LAYER met3 ;
        RECT 0.000 1747.640 4.000 1748.240 ;
    END
  END auto_trace_source_out_insns_0_insn[24]
  PIN auto_trace_source_out_insns_0_insn[25]
    DIRECTION OUTPUT TRISTATE ;
    USE SIGNAL ;
    ANTENNADIFFAREA 0.340600 ;
    PORT
      LAYER met2 ;
        RECT 5490.190 0.000 5490.470 4.000 ;
    END
  END auto_trace_source_out_insns_0_insn[25]
  PIN auto_trace_source_out_insns_0_insn[26]
    DIRECTION OUTPUT TRISTATE ;
    USE SIGNAL ;
    ANTENNADIFFAREA 0.340600 ;
    PORT
      LAYER met3 ;
        RECT 6996.000 2193.040 7000.000 2193.640 ;
    END
  END auto_trace_source_out_insns_0_insn[26]
  PIN auto_trace_source_out_insns_0_insn[27]
    DIRECTION OUTPUT TRISTATE ;
    USE SIGNAL ;
    ANTENNADIFFAREA 0.340600 ;
    PORT
      LAYER met2 ;
        RECT 3632.250 2596.000 3632.530 2600.000 ;
    END
  END auto_trace_source_out_insns_0_insn[27]
  PIN auto_trace_source_out_insns_0_insn[28]
    DIRECTION OUTPUT TRISTATE ;
    USE SIGNAL ;
    ANTENNADIFFAREA 0.340600 ;
    PORT
      LAYER met3 ;
        RECT 6996.000 1434.840 7000.000 1435.440 ;
    END
  END auto_trace_source_out_insns_0_insn[28]
  PIN auto_trace_source_out_insns_0_insn[29]
    DIRECTION OUTPUT TRISTATE ;
    USE SIGNAL ;
    ANTENNADIFFAREA 0.340600 ;
    PORT
      LAYER met2 ;
        RECT 4218.290 0.000 4218.570 4.000 ;
    END
  END auto_trace_source_out_insns_0_insn[29]
  PIN auto_trace_source_out_insns_0_insn[2]
    DIRECTION OUTPUT TRISTATE ;
    USE SIGNAL ;
    ANTENNADIFFAREA 0.340600 ;
    PORT
      LAYER met2 ;
        RECT 4820.430 2596.000 4820.710 2600.000 ;
    END
  END auto_trace_source_out_insns_0_insn[2]
  PIN auto_trace_source_out_insns_0_insn[30]
    DIRECTION OUTPUT TRISTATE ;
    USE SIGNAL ;
    ANTENNADIFFAREA 0.340600 ;
    PORT
      LAYER met2 ;
        RECT 6040.810 0.000 6041.090 4.000 ;
    END
  END auto_trace_source_out_insns_0_insn[30]
  PIN auto_trace_source_out_insns_0_insn[31]
    DIRECTION OUTPUT TRISTATE ;
    USE SIGNAL ;
    ANTENNADIFFAREA 0.340600 ;
    PORT
      LAYER met3 ;
        RECT 0.000 697.040 4.000 697.640 ;
    END
  END auto_trace_source_out_insns_0_insn[31]
  PIN auto_trace_source_out_insns_0_insn[3]
    DIRECTION OUTPUT TRISTATE ;
    USE SIGNAL ;
    ANTENNADIFFAREA 0.340600 ;
    PORT
      LAYER met2 ;
        RECT 5074.810 0.000 5075.090 4.000 ;
    END
  END auto_trace_source_out_insns_0_insn[3]
  PIN auto_trace_source_out_insns_0_insn[4]
    DIRECTION OUTPUT TRISTATE ;
    USE SIGNAL ;
    ANTENNADIFFAREA 0.340600 ;
    PORT
      LAYER met2 ;
        RECT 431.570 2596.000 431.850 2600.000 ;
    END
  END auto_trace_source_out_insns_0_insn[4]
  PIN auto_trace_source_out_insns_0_insn[5]
    DIRECTION OUTPUT TRISTATE ;
    USE SIGNAL ;
    ANTENNADIFFAREA 0.340600 ;
    PORT
      LAYER met2 ;
        RECT 689.170 0.000 689.450 4.000 ;
    END
  END auto_trace_source_out_insns_0_insn[5]
  PIN auto_trace_source_out_insns_0_insn[6]
    DIRECTION OUTPUT TRISTATE ;
    USE SIGNAL ;
    ANTENNADIFFAREA 0.340600 ;
    PORT
      LAYER met3 ;
        RECT 6996.000 1258.040 7000.000 1258.640 ;
    END
  END auto_trace_source_out_insns_0_insn[6]
  PIN auto_trace_source_out_insns_0_insn[7]
    DIRECTION OUTPUT TRISTATE ;
    USE SIGNAL ;
    ANTENNADIFFAREA 0.340600 ;
    PORT
      LAYER met2 ;
        RECT 3088.070 0.000 3088.350 4.000 ;
    END
  END auto_trace_source_out_insns_0_insn[7]
  PIN auto_trace_source_out_insns_0_insn[8]
    DIRECTION OUTPUT TRISTATE ;
    USE SIGNAL ;
    ANTENNADIFFAREA 0.340600 ;
    PORT
      LAYER met3 ;
        RECT 6996.000 2104.640 7000.000 2105.240 ;
    END
  END auto_trace_source_out_insns_0_insn[8]
  PIN auto_trace_source_out_insns_0_insn[9]
    DIRECTION OUTPUT TRISTATE ;
    USE SIGNAL ;
    ANTENNADIFFAREA 0.340600 ;
    PORT
      LAYER met2 ;
        RECT 1378.250 0.000 1378.530 4.000 ;
    END
  END auto_trace_source_out_insns_0_insn[9]
  PIN auto_trace_source_out_insns_0_interrupt
    DIRECTION OUTPUT TRISTATE ;
    USE SIGNAL ;
    ANTENNADIFFAREA 0.340600 ;
    PORT
      LAYER met3 ;
        RECT 0.000 2125.040 4.000 2125.640 ;
    END
  END auto_trace_source_out_insns_0_interrupt
  PIN auto_trace_source_out_insns_0_priv[0]
    DIRECTION OUTPUT TRISTATE ;
    USE SIGNAL ;
    ANTENNADIFFAREA 0.340600 ;
    PORT
      LAYER met3 ;
        RECT 0.000 173.440 4.000 174.040 ;
    END
  END auto_trace_source_out_insns_0_priv[0]
  PIN auto_trace_source_out_insns_0_priv[1]
    DIRECTION OUTPUT TRISTATE ;
    USE SIGNAL ;
    ANTENNADIFFAREA 0.340600 ;
    PORT
      LAYER met2 ;
        RECT 4900.930 2596.000 4901.210 2600.000 ;
    END
  END auto_trace_source_out_insns_0_priv[1]
  PIN auto_trace_source_out_insns_0_priv[2]
    DIRECTION OUTPUT TRISTATE ;
    USE SIGNAL ;
    ANTENNADIFFAREA 0.340600 ;
    PORT
      LAYER met2 ;
        RECT 6942.410 2596.000 6942.690 2600.000 ;
    END
  END auto_trace_source_out_insns_0_priv[2]
  PIN auto_trace_source_out_insns_0_tval[0]
    DIRECTION OUTPUT TRISTATE ;
    USE SIGNAL ;
    ANTENNADIFFAREA 0.340600 ;
    PORT
      LAYER met2 ;
        RECT 1674.490 2596.000 1674.770 2600.000 ;
    END
  END auto_trace_source_out_insns_0_tval[0]
  PIN auto_trace_source_out_insns_0_tval[10]
    DIRECTION OUTPUT TRISTATE ;
    USE SIGNAL ;
    ANTENNADIFFAREA 0.340600 ;
    PORT
      LAYER met2 ;
        RECT 2170.370 2596.000 2170.650 2600.000 ;
    END
  END auto_trace_source_out_insns_0_tval[10]
  PIN auto_trace_source_out_insns_0_tval[11]
    DIRECTION OUTPUT TRISTATE ;
    USE SIGNAL ;
    ANTENNADIFFAREA 0.340600 ;
    PORT
      LAYER met2 ;
        RECT 6317.730 0.000 6318.010 4.000 ;
    END
  END auto_trace_source_out_insns_0_tval[11]
  PIN auto_trace_source_out_insns_0_tval[12]
    DIRECTION OUTPUT TRISTATE ;
    USE SIGNAL ;
    ANTENNADIFFAREA 0.340600 ;
    PORT
      LAYER met2 ;
        RECT 1397.570 2596.000 1397.850 2600.000 ;
    END
  END auto_trace_source_out_insns_0_tval[12]
  PIN auto_trace_source_out_insns_0_tval[13]
    DIRECTION OUTPUT TRISTATE ;
    USE SIGNAL ;
    ANTENNADIFFAREA 0.340600 ;
    PORT
      LAYER met3 ;
        RECT 6996.000 238.040 7000.000 238.640 ;
    END
  END auto_trace_source_out_insns_0_tval[13]
  PIN auto_trace_source_out_insns_0_tval[14]
    DIRECTION OUTPUT TRISTATE ;
    USE SIGNAL ;
    ANTENNADIFFAREA 0.340600 ;
    PORT
      LAYER met2 ;
        RECT 3992.890 2596.000 3993.170 2600.000 ;
    END
  END auto_trace_source_out_insns_0_tval[14]
  PIN auto_trace_source_out_insns_0_tval[15]
    DIRECTION OUTPUT TRISTATE ;
    USE SIGNAL ;
    ANTENNADIFFAREA 0.340600 ;
    PORT
      LAYER met2 ;
        RECT 2888.430 2596.000 2888.710 2600.000 ;
    END
  END auto_trace_source_out_insns_0_tval[15]
  PIN auto_trace_source_out_insns_0_tval[16]
    DIRECTION OUTPUT TRISTATE ;
    USE SIGNAL ;
    ANTENNADIFFAREA 0.340600 ;
    PORT
      LAYER met2 ;
        RECT 792.210 2596.000 792.490 2600.000 ;
    END
  END auto_trace_source_out_insns_0_tval[16]
  PIN auto_trace_source_out_insns_0_tval[17]
    DIRECTION OUTPUT TRISTATE ;
    USE SIGNAL ;
    ANTENNADIFFAREA 0.340600 ;
    PORT
      LAYER met2 ;
        RECT 495.970 0.000 496.250 4.000 ;
    END
  END auto_trace_source_out_insns_0_tval[17]
  PIN auto_trace_source_out_insns_0_tval[18]
    DIRECTION OUTPUT TRISTATE ;
    USE SIGNAL ;
    ANTENNADIFFAREA 0.340600 ;
    PORT
      LAYER met3 ;
        RECT 0.000 2009.440 4.000 2010.040 ;
    END
  END auto_trace_source_out_insns_0_tval[18]
  PIN auto_trace_source_out_insns_0_tval[19]
    DIRECTION OUTPUT TRISTATE ;
    USE SIGNAL ;
    ANTENNADIFFAREA 0.340600 ;
    PORT
      LAYER met3 ;
        RECT 6996.000 2335.840 7000.000 2336.440 ;
    END
  END auto_trace_source_out_insns_0_tval[19]
  PIN auto_trace_source_out_insns_0_tval[1]
    DIRECTION OUTPUT TRISTATE ;
    USE SIGNAL ;
    ANTENNADIFFAREA 0.340600 ;
    PORT
      LAYER met3 ;
        RECT 6996.000 1989.040 7000.000 1989.640 ;
    END
  END auto_trace_source_out_insns_0_tval[1]
  PIN auto_trace_source_out_insns_0_tval[20]
    DIRECTION OUTPUT TRISTATE ;
    USE SIGNAL ;
    ANTENNADIFFAREA 0.340600 ;
    PORT
      LAYER met2 ;
        RECT 3364.990 0.000 3365.270 4.000 ;
    END
  END auto_trace_source_out_insns_0_tval[20]
  PIN auto_trace_source_out_insns_0_tval[21]
    DIRECTION OUTPUT TRISTATE ;
    USE SIGNAL ;
    ANTENNADIFFAREA 0.340600 ;
    PORT
      LAYER met3 ;
        RECT 6996.000 1550.440 7000.000 1551.040 ;
    END
  END auto_trace_source_out_insns_0_tval[21]
  PIN auto_trace_source_out_insns_0_tval[22]
    DIRECTION OUTPUT TRISTATE ;
    USE SIGNAL ;
    ANTENNADIFFAREA 0.340600 ;
    PORT
      LAYER met2 ;
        RECT 6952.070 0.000 6952.350 4.000 ;
    END
  END auto_trace_source_out_insns_0_tval[22]
  PIN auto_trace_source_out_insns_0_tval[23]
    DIRECTION OUTPUT TRISTATE ;
    USE SIGNAL ;
    ANTENNADIFFAREA 0.340600 ;
    PORT
      LAYER met2 ;
        RECT 5103.790 0.000 5104.070 4.000 ;
    END
  END auto_trace_source_out_insns_0_tval[23]
  PIN auto_trace_source_out_insns_0_tval[24]
    DIRECTION OUTPUT TRISTATE ;
    USE SIGNAL ;
    ANTENNADIFFAREA 0.340600 ;
    PORT
      LAYER met2 ;
        RECT 4073.390 2596.000 4073.670 2600.000 ;
    END
  END auto_trace_source_out_insns_0_tval[24]
  PIN auto_trace_source_out_insns_0_tval[25]
    DIRECTION OUTPUT TRISTATE ;
    USE SIGNAL ;
    ANTENNADIFFAREA 0.340600 ;
    PORT
      LAYER met2 ;
        RECT 5593.230 2596.000 5593.510 2600.000 ;
    END
  END auto_trace_source_out_insns_0_tval[25]
  PIN auto_trace_source_out_insns_0_tval[26]
    DIRECTION OUTPUT TRISTATE ;
    USE SIGNAL ;
    ANTENNADIFFAREA 0.340600 ;
    PORT
      LAYER met2 ;
        RECT 2978.590 0.000 2978.870 4.000 ;
    END
  END auto_trace_source_out_insns_0_tval[26]
  PIN auto_trace_source_out_insns_0_tval[27]
    DIRECTION OUTPUT TRISTATE ;
    USE SIGNAL ;
    ANTENNADIFFAREA 0.340600 ;
    PORT
      LAYER met2 ;
        RECT 4247.270 0.000 4247.550 4.000 ;
    END
  END auto_trace_source_out_insns_0_tval[27]
  PIN auto_trace_source_out_insns_0_tval[28]
    DIRECTION OUTPUT TRISTATE ;
    USE SIGNAL ;
    ANTENNADIFFAREA 0.340600 ;
    PORT
      LAYER met3 ;
        RECT 0.000 1366.840 4.000 1367.440 ;
    END
  END auto_trace_source_out_insns_0_tval[28]
  PIN auto_trace_source_out_insns_0_tval[29]
    DIRECTION OUTPUT TRISTATE ;
    USE SIGNAL ;
    ANTENNADIFFAREA 0.340600 ;
    PORT
      LAYER met3 ;
        RECT 0.000 57.840 4.000 58.440 ;
    END
  END auto_trace_source_out_insns_0_tval[29]
  PIN auto_trace_source_out_insns_0_tval[2]
    DIRECTION OUTPUT TRISTATE ;
    USE SIGNAL ;
    ANTENNADIFFAREA 0.340600 ;
    PORT
      LAYER met2 ;
        RECT 2869.110 0.000 2869.390 4.000 ;
    END
  END auto_trace_source_out_insns_0_tval[2]
  PIN auto_trace_source_out_insns_0_tval[30]
    DIRECTION OUTPUT TRISTATE ;
    USE SIGNAL ;
    ANTENNADIFFAREA 0.340600 ;
    PORT
      LAYER met2 ;
        RECT 550.710 0.000 550.990 4.000 ;
    END
  END auto_trace_source_out_insns_0_tval[30]
  PIN auto_trace_source_out_insns_0_tval[31]
    DIRECTION OUTPUT TRISTATE ;
    USE SIGNAL ;
    ANTENNADIFFAREA 0.340600 ;
    PORT
      LAYER met2 ;
        RECT 2611.510 2596.000 2611.790 2600.000 ;
    END
  END auto_trace_source_out_insns_0_tval[31]
  PIN auto_trace_source_out_insns_0_tval[32]
    DIRECTION OUTPUT TRISTATE ;
    USE SIGNAL ;
    ANTENNADIFFAREA 0.340600 ;
    PORT
      LAYER met3 ;
        RECT 6996.000 1315.840 7000.000 1316.440 ;
    END
  END auto_trace_source_out_insns_0_tval[32]
  PIN auto_trace_source_out_insns_0_tval[33]
    DIRECTION OUTPUT TRISTATE ;
    USE SIGNAL ;
    ANTENNADIFFAREA 0.340600 ;
    PORT
      LAYER met2 ;
        RECT 6282.310 2596.000 6282.590 2600.000 ;
    END
  END auto_trace_source_out_insns_0_tval[33]
  PIN auto_trace_source_out_insns_0_tval[34]
    DIRECTION OUTPUT TRISTATE ;
    USE SIGNAL ;
    ANTENNADIFFAREA 0.340600 ;
    PORT
      LAYER met2 ;
        RECT 2012.590 0.000 2012.870 4.000 ;
    END
  END auto_trace_source_out_insns_0_tval[34]
  PIN auto_trace_source_out_insns_0_tval[35]
    DIRECTION OUTPUT TRISTATE ;
    USE SIGNAL ;
    ANTENNADIFFAREA 0.340600 ;
    PORT
      LAYER met2 ;
        RECT 5039.390 2596.000 5039.670 2600.000 ;
    END
  END auto_trace_source_out_insns_0_tval[35]
  PIN auto_trace_source_out_insns_0_tval[36]
    DIRECTION OUTPUT TRISTATE ;
    USE SIGNAL ;
    ANTENNADIFFAREA 0.340600 ;
    PORT
      LAYER met3 ;
        RECT 6996.000 384.240 7000.000 384.840 ;
    END
  END auto_trace_source_out_insns_0_tval[36]
  PIN auto_trace_source_out_insns_0_tval[37]
    DIRECTION OUTPUT TRISTATE ;
    USE SIGNAL ;
    ANTENNADIFFAREA 0.340600 ;
    PORT
      LAYER met2 ;
        RECT 4028.310 0.000 4028.590 4.000 ;
    END
  END auto_trace_source_out_insns_0_tval[37]
  PIN auto_trace_source_out_insns_0_tval[38]
    DIRECTION OUTPUT TRISTATE ;
    USE SIGNAL ;
    ANTENNADIFFAREA 0.340600 ;
    PORT
      LAYER met2 ;
        RECT 4955.670 2596.000 4955.950 2600.000 ;
    END
  END auto_trace_source_out_insns_0_tval[38]
  PIN auto_trace_source_out_insns_0_tval[39]
    DIRECTION OUTPUT TRISTATE ;
    USE SIGNAL ;
    ANTENNADIFFAREA 0.340600 ;
    PORT
      LAYER met2 ;
        RECT 3889.850 0.000 3890.130 4.000 ;
    END
  END auto_trace_source_out_insns_0_tval[39]
  PIN auto_trace_source_out_insns_0_tval[3]
    DIRECTION OUTPUT TRISTATE ;
    USE SIGNAL ;
    ANTENNADIFFAREA 0.340600 ;
    PORT
      LAYER met2 ;
        RECT 1626.190 0.000 1626.470 4.000 ;
    END
  END auto_trace_source_out_insns_0_tval[3]
  PIN auto_trace_source_out_insns_0_tval[4]
    DIRECTION OUTPUT TRISTATE ;
    USE SIGNAL ;
    ANTENNADIFFAREA 0.340600 ;
    PORT
      LAYER met2 ;
        RECT 248.030 0.000 248.310 4.000 ;
    END
  END auto_trace_source_out_insns_0_tval[4]
  PIN auto_trace_source_out_insns_0_tval[5]
    DIRECTION OUTPUT TRISTATE ;
    USE SIGNAL ;
    ANTENNADIFFAREA 0.340600 ;
    PORT
      LAYER met3 ;
        RECT 0.000 1309.040 4.000 1309.640 ;
    END
  END auto_trace_source_out_insns_0_tval[5]
  PIN auto_trace_source_out_insns_0_tval[6]
    DIRECTION OUTPUT TRISTATE ;
    USE SIGNAL ;
    ANTENNADIFFAREA 0.340600 ;
    PORT
      LAYER met2 ;
        RECT 6536.690 0.000 6536.970 4.000 ;
    END
  END auto_trace_source_out_insns_0_tval[6]
  PIN auto_trace_source_out_insns_0_tval[7]
    DIRECTION OUTPUT TRISTATE ;
    USE SIGNAL ;
    ANTENNADIFFAREA 0.340600 ;
    PORT
      LAYER met2 ;
        RECT 2749.970 2596.000 2750.250 2600.000 ;
    END
  END auto_trace_source_out_insns_0_tval[7]
  PIN auto_trace_source_out_insns_0_tval[8]
    DIRECTION OUTPUT TRISTATE ;
    USE SIGNAL ;
    ANTENNADIFFAREA 0.340600 ;
    PORT
      LAYER met2 ;
        RECT 6887.670 2596.000 6887.950 2600.000 ;
    END
  END auto_trace_source_out_insns_0_tval[8]
  PIN auto_trace_source_out_insns_0_tval[9]
    DIRECTION OUTPUT TRISTATE ;
    USE SIGNAL ;
    ANTENNADIFFAREA 0.340600 ;
    PORT
      LAYER met2 ;
        RECT 19.410 2596.000 19.690 2600.000 ;
    END
  END auto_trace_source_out_insns_0_tval[9]
  PIN auto_trace_source_out_insns_0_valid
    DIRECTION OUTPUT TRISTATE ;
    USE SIGNAL ;
    ANTENNADIFFAREA 0.340600 ;
    PORT
      LAYER met2 ;
        RECT 376.830 2596.000 377.110 2600.000 ;
    END
  END auto_trace_source_out_insns_0_valid
  PIN auto_trace_source_out_time[0]
    DIRECTION OUTPUT TRISTATE ;
    USE SIGNAL ;
    ANTENNADIFFAREA 0.340600 ;
    PORT
      LAYER met2 ;
        RECT 238.370 2596.000 238.650 2600.000 ;
    END
  END auto_trace_source_out_time[0]
  PIN auto_trace_source_out_time[10]
    DIRECTION OUTPUT TRISTATE ;
    USE SIGNAL ;
    ANTENNADIFFAREA 0.340600 ;
    PORT
      LAYER met2 ;
        RECT 219.050 0.000 219.330 4.000 ;
    END
  END auto_trace_source_out_time[10]
  PIN auto_trace_source_out_time[11]
    DIRECTION OUTPUT TRISTATE ;
    USE SIGNAL ;
    ANTENNADIFFAREA 0.340600 ;
    PORT
      LAYER met2 ;
        RECT 1101.330 0.000 1101.610 4.000 ;
    END
  END auto_trace_source_out_time[11]
  PIN auto_trace_source_out_time[12]
    DIRECTION OUTPUT TRISTATE ;
    USE SIGNAL ;
    ANTENNADIFFAREA 0.340600 ;
    PORT
      LAYER met3 ;
        RECT 0.000 1077.840 4.000 1078.440 ;
    END
  END auto_trace_source_out_time[12]
  PIN auto_trace_source_out_time[13]
    DIRECTION OUTPUT TRISTATE ;
    USE SIGNAL ;
    ANTENNADIFFAREA 0.340600 ;
    PORT
      LAYER met2 ;
        RECT 2923.850 0.000 2924.130 4.000 ;
    END
  END auto_trace_source_out_time[13]
  PIN auto_trace_source_out_time[14]
    DIRECTION OUTPUT TRISTATE ;
    USE SIGNAL ;
    ANTENNADIFFAREA 0.340600 ;
    PORT
      LAYER met2 ;
        RECT 4736.710 2596.000 4736.990 2600.000 ;
    END
  END auto_trace_source_out_time[14]
  PIN auto_trace_source_out_time[15]
    DIRECTION OUTPUT TRISTATE ;
    USE SIGNAL ;
    ANTENNADIFFAREA 0.340600 ;
    PORT
      LAYER met2 ;
        RECT 5976.410 2596.000 5976.690 2600.000 ;
    END
  END auto_trace_source_out_time[15]
  PIN auto_trace_source_out_time[16]
    DIRECTION OUTPUT TRISTATE ;
    USE SIGNAL ;
    ANTENNADIFFAREA 0.340600 ;
    PORT
      LAYER met2 ;
        RECT 1590.770 2596.000 1591.050 2600.000 ;
    END
  END auto_trace_source_out_time[16]
  PIN auto_trace_source_out_time[17]
    DIRECTION OUTPUT TRISTATE ;
    USE SIGNAL ;
    ANTENNADIFFAREA 0.340600 ;
    PORT
      LAYER met2 ;
        RECT 798.650 0.000 798.930 4.000 ;
    END
  END auto_trace_source_out_time[17]
  PIN auto_trace_source_out_time[18]
    DIRECTION OUTPUT TRISTATE ;
    USE SIGNAL ;
    ANTENNADIFFAREA 0.340600 ;
    PORT
      LAYER met3 ;
        RECT 6996.000 1142.440 7000.000 1143.040 ;
    END
  END auto_trace_source_out_time[18]
  PIN auto_trace_source_out_time[19]
    DIRECTION OUTPUT TRISTATE ;
    USE SIGNAL ;
    ANTENNADIFFAREA 0.340600 ;
    PORT
      LAYER met2 ;
        RECT 6169.610 2596.000 6169.890 2600.000 ;
    END
  END auto_trace_source_out_time[19]
  PIN auto_trace_source_out_time[1]
    DIRECTION OUTPUT TRISTATE ;
    USE SIGNAL ;
    ANTENNADIFFAREA 0.340600 ;
    PORT
      LAYER met3 ;
        RECT 0.000 754.840 4.000 755.440 ;
    END
  END auto_trace_source_out_time[1]
  PIN auto_trace_source_out_time[20]
    DIRECTION OUTPUT TRISTATE ;
    USE SIGNAL ;
    ANTENNADIFFAREA 0.340600 ;
    PORT
      LAYER met3 ;
        RECT 6996.000 2046.840 7000.000 2047.440 ;
    END
  END auto_trace_source_out_time[20]
  PIN auto_trace_source_out_time[21]
    DIRECTION OUTPUT TRISTATE ;
    USE SIGNAL ;
    ANTENNADIFFAREA 0.340600 ;
    PORT
      LAYER met2 ;
        RECT 6675.150 0.000 6675.430 4.000 ;
    END
  END auto_trace_source_out_time[21]
  PIN auto_trace_source_out_time[22]
    DIRECTION OUTPUT TRISTATE ;
    USE SIGNAL ;
    ANTENNADIFFAREA 0.340600 ;
    PORT
      LAYER met2 ;
        RECT 3474.470 0.000 3474.750 4.000 ;
    END
  END auto_trace_source_out_time[22]
  PIN auto_trace_source_out_time[23]
    DIRECTION OUTPUT TRISTATE ;
    USE SIGNAL ;
    ANTENNADIFFAREA 0.340600 ;
    PORT
      LAYER met2 ;
        RECT 5647.970 2596.000 5648.250 2600.000 ;
    END
  END auto_trace_source_out_time[23]
  PIN auto_trace_source_out_time[24]
    DIRECTION OUTPUT TRISTATE ;
    USE SIGNAL ;
    ANTENNADIFFAREA 0.340600 ;
    PORT
      LAYER met3 ;
        RECT 0.000 142.840 4.000 143.440 ;
    END
  END auto_trace_source_out_time[24]
  PIN auto_trace_source_out_time[25]
    DIRECTION OUTPUT TRISTATE ;
    USE SIGNAL ;
    ANTENNADIFFAREA 0.340600 ;
    PORT
      LAYER met2 ;
        RECT 1571.450 0.000 1571.730 4.000 ;
    END
  END auto_trace_source_out_time[25]
  PIN auto_trace_source_out_time[26]
    DIRECTION OUTPUT TRISTATE ;
    USE SIGNAL ;
    ANTENNADIFFAREA 0.340600 ;
    PORT
      LAYER met3 ;
        RECT 6996.000 1054.040 7000.000 1054.640 ;
    END
  END auto_trace_source_out_time[26]
  PIN auto_trace_source_out_time[27]
    DIRECTION OUTPUT TRISTATE ;
    USE SIGNAL ;
    ANTENNADIFFAREA 0.340600 ;
    PORT
      LAYER met2 ;
        RECT 4083.050 0.000 4083.330 4.000 ;
    END
  END auto_trace_source_out_time[27]
  PIN auto_trace_source_out_time[28]
    DIRECTION OUTPUT TRISTATE ;
    USE SIGNAL ;
    ANTENNADIFFAREA 0.340600 ;
    PORT
      LAYER met2 ;
        RECT 6456.190 0.000 6456.470 4.000 ;
    END
  END auto_trace_source_out_time[28]
  PIN auto_trace_source_out_time[29]
    DIRECTION OUTPUT TRISTATE ;
    USE SIGNAL ;
    ANTENNADIFFAREA 0.340600 ;
    PORT
      LAYER met3 ;
        RECT 0.000 1805.440 4.000 1806.040 ;
    END
  END auto_trace_source_out_time[29]
  PIN auto_trace_source_out_time[2]
    DIRECTION OUTPUT TRISTATE ;
    USE SIGNAL ;
    ANTENNADIFFAREA 0.340600 ;
    PORT
      LAYER met2 ;
        RECT 5158.530 0.000 5158.810 4.000 ;
    END
  END auto_trace_source_out_time[2]
  PIN auto_trace_source_out_time[30]
    DIRECTION OUTPUT TRISTATE ;
    USE SIGNAL ;
    ANTENNADIFFAREA 0.340600 ;
    PORT
      LAYER met2 ;
        RECT 827.630 0.000 827.910 4.000 ;
    END
  END auto_trace_source_out_time[30]
  PIN auto_trace_source_out_time[31]
    DIRECTION OUTPUT TRISTATE ;
    USE SIGNAL ;
    ANTENNADIFFAREA 0.340600 ;
    PORT
      LAYER met2 ;
        RECT 2453.730 0.000 2454.010 4.000 ;
    END
  END auto_trace_source_out_time[31]
  PIN auto_trace_source_out_time[32]
    DIRECTION OUTPUT TRISTATE ;
    USE SIGNAL ;
    ANTENNADIFFAREA 0.340600 ;
    PORT
      LAYER met3 ;
        RECT 6996.000 95.240 7000.000 95.840 ;
    END
  END auto_trace_source_out_time[32]
  PIN auto_trace_source_out_time[33]
    DIRECTION OUTPUT TRISTATE ;
    USE SIGNAL ;
    ANTENNADIFFAREA 0.340600 ;
    PORT
      LAYER met2 ;
        RECT 5564.250 2596.000 5564.530 2600.000 ;
    END
  END auto_trace_source_out_time[33]
  PIN auto_trace_source_out_time[34]
    DIRECTION OUTPUT TRISTATE ;
    USE SIGNAL ;
    ANTENNADIFFAREA 0.340600 ;
    PORT
      LAYER met3 ;
        RECT 6996.000 2482.040 7000.000 2482.640 ;
    END
  END auto_trace_source_out_time[34]
  PIN auto_trace_source_out_time[35]
    DIRECTION OUTPUT TRISTATE ;
    USE SIGNAL ;
    ANTENNADIFFAREA 0.340600 ;
    PORT
      LAYER met2 ;
        RECT 5184.290 0.000 5184.570 4.000 ;
    END
  END auto_trace_source_out_time[35]
  PIN auto_trace_source_out_time[36]
    DIRECTION OUTPUT TRISTATE ;
    USE SIGNAL ;
    ANTENNADIFFAREA 0.340600 ;
    PORT
      LAYER met2 ;
        RECT 383.270 0.000 383.550 4.000 ;
    END
  END auto_trace_source_out_time[36]
  PIN auto_trace_source_out_time[37]
    DIRECTION OUTPUT TRISTATE ;
    USE SIGNAL ;
    ANTENNADIFFAREA 0.340600 ;
    PORT
      LAYER met3 ;
        RECT 6996.000 765.040 7000.000 765.640 ;
    END
  END auto_trace_source_out_time[37]
  PIN auto_trace_source_out_time[38]
    DIRECTION OUTPUT TRISTATE ;
    USE SIGNAL ;
    ANTENNADIFFAREA 0.340600 ;
    PORT
      LAYER met2 ;
        RECT 109.570 0.000 109.850 4.000 ;
    END
  END auto_trace_source_out_time[38]
  PIN auto_trace_source_out_time[39]
    DIRECTION OUTPUT TRISTATE ;
    USE SIGNAL ;
    ANTENNADIFFAREA 0.340600 ;
    PORT
      LAYER met3 ;
        RECT 6996.000 2570.440 7000.000 2571.040 ;
    END
  END auto_trace_source_out_time[39]
  PIN auto_trace_source_out_time[3]
    DIRECTION OUTPUT TRISTATE ;
    USE SIGNAL ;
    ANTENNADIFFAREA 0.340600 ;
    PORT
      LAYER met2 ;
        RECT 5454.770 2596.000 5455.050 2600.000 ;
    END
  END auto_trace_source_out_time[3]
  PIN auto_trace_source_out_time[40]
    DIRECTION OUTPUT TRISTATE ;
    USE SIGNAL ;
    ANTENNADIFFAREA 0.340600 ;
    PORT
      LAYER met2 ;
        RECT 5461.210 0.000 5461.490 4.000 ;
    END
  END auto_trace_source_out_time[40]
  PIN auto_trace_source_out_time[41]
    DIRECTION OUTPUT TRISTATE ;
    USE SIGNAL ;
    ANTENNADIFFAREA 0.340600 ;
    PORT
      LAYER met2 ;
        RECT 5316.310 2596.000 5316.590 2600.000 ;
    END
  END auto_trace_source_out_time[41]
  PIN auto_trace_source_out_time[42]
    DIRECTION OUTPUT TRISTATE ;
    USE SIGNAL ;
    ANTENNADIFFAREA 0.340600 ;
    PORT
      LAYER met2 ;
        RECT 3310.250 0.000 3310.530 4.000 ;
    END
  END auto_trace_source_out_time[42]
  PIN auto_trace_source_out_time[43]
    DIRECTION OUTPUT TRISTATE ;
    USE SIGNAL ;
    ANTENNADIFFAREA 0.340600 ;
    PORT
      LAYER met3 ;
        RECT 0.000 1016.640 4.000 1017.240 ;
    END
  END auto_trace_source_out_time[43]
  PIN auto_trace_source_out_time[44]
    DIRECTION OUTPUT TRISTATE ;
    USE SIGNAL ;
    ANTENNADIFFAREA 0.340600 ;
    PORT
      LAYER met2 ;
        RECT 3281.270 0.000 3281.550 4.000 ;
    END
  END auto_trace_source_out_time[44]
  PIN auto_trace_source_out_time[45]
    DIRECTION OUTPUT TRISTATE ;
    USE SIGNAL ;
    ANTENNADIFFAREA 0.340600 ;
    PORT
      LAYER met2 ;
        RECT 0.090 0.000 0.370 4.000 ;
    END
  END auto_trace_source_out_time[45]
  PIN auto_trace_source_out_time[46]
    DIRECTION OUTPUT TRISTATE ;
    USE SIGNAL ;
    ANTENNADIFFAREA 0.340600 ;
    PORT
      LAYER met2 ;
        RECT 3860.870 0.000 3861.150 4.000 ;
    END
  END auto_trace_source_out_time[46]
  PIN auto_trace_source_out_time[47]
    DIRECTION OUTPUT TRISTATE ;
    USE SIGNAL ;
    ANTENNADIFFAREA 0.340600 ;
    PORT
      LAYER met3 ;
        RECT 0.000 1921.040 4.000 1921.640 ;
    END
  END auto_trace_source_out_time[47]
  PIN auto_trace_source_out_time[48]
    DIRECTION OUTPUT TRISTATE ;
    USE SIGNAL ;
    ANTENNADIFFAREA 0.340600 ;
    PORT
      LAYER met2 ;
        RECT 1259.110 2596.000 1259.390 2600.000 ;
    END
  END auto_trace_source_out_time[48]
  PIN auto_trace_source_out_time[49]
    DIRECTION OUTPUT TRISTATE ;
    USE SIGNAL ;
    ANTENNADIFFAREA 0.340600 ;
    PORT
      LAYER met2 ;
        RECT 3274.830 2596.000 3275.110 2600.000 ;
    END
  END auto_trace_source_out_time[49]
  PIN auto_trace_source_out_time[4]
    DIRECTION OUTPUT TRISTATE ;
    USE SIGNAL ;
    ANTENNADIFFAREA 0.340600 ;
    PORT
      LAYER met3 ;
        RECT 0.000 1220.640 4.000 1221.240 ;
    END
  END auto_trace_source_out_time[4]
  PIN auto_trace_source_out_time[50]
    DIRECTION OUTPUT TRISTATE ;
    USE SIGNAL ;
    ANTENNADIFFAREA 0.340600 ;
    PORT
      LAYER met2 ;
        RECT 1020.830 0.000 1021.110 4.000 ;
    END
  END auto_trace_source_out_time[50]
  PIN auto_trace_source_out_time[51]
    DIRECTION OUTPUT TRISTATE ;
    USE SIGNAL ;
    ANTENNADIFFAREA 0.340600 ;
    PORT
      LAYER met2 ;
        RECT 357.510 0.000 357.790 4.000 ;
    END
  END auto_trace_source_out_time[51]
  PIN auto_trace_source_out_time[52]
    DIRECTION OUTPUT TRISTATE ;
    USE SIGNAL ;
    ANTENNADIFFAREA 0.340600 ;
    PORT
      LAYER met2 ;
        RECT 4488.770 2596.000 4489.050 2600.000 ;
    END
  END auto_trace_source_out_time[52]
  PIN auto_trace_source_out_time[53]
    DIRECTION OUTPUT TRISTATE ;
    USE SIGNAL ;
    ANTENNADIFFAREA 0.340600 ;
    PORT
      LAYER met2 ;
        RECT 3439.050 2596.000 3439.330 2600.000 ;
    END
  END auto_trace_source_out_time[53]
  PIN auto_trace_source_out_time[54]
    DIRECTION OUTPUT TRISTATE ;
    USE SIGNAL ;
    ANTENNADIFFAREA 0.340600 ;
    PORT
      LAYER met2 ;
        RECT 2621.170 0.000 2621.450 4.000 ;
    END
  END auto_trace_source_out_time[54]
  PIN auto_trace_source_out_time[55]
    DIRECTION OUTPUT TRISTATE ;
    USE SIGNAL ;
    ANTENNADIFFAREA 0.340600 ;
    PORT
      LAYER met2 ;
        RECT 5371.050 2596.000 5371.330 2600.000 ;
    END
  END auto_trace_source_out_time[55]
  PIN auto_trace_source_out_time[56]
    DIRECTION OUTPUT TRISTATE ;
    USE SIGNAL ;
    ANTENNADIFFAREA 0.340600 ;
    PORT
      LAYER met2 ;
        RECT 6150.290 0.000 6150.570 4.000 ;
    END
  END auto_trace_source_out_time[56]
  PIN auto_trace_source_out_time[57]
    DIRECTION OUTPUT TRISTATE ;
    USE SIGNAL ;
    ANTENNADIFFAREA 0.340600 ;
    PORT
      LAYER met2 ;
        RECT 405.810 2596.000 406.090 2600.000 ;
    END
  END auto_trace_source_out_time[57]
  PIN auto_trace_source_out_time[58]
    DIRECTION OUTPUT TRISTATE ;
    USE SIGNAL ;
    ANTENNADIFFAREA 0.340600 ;
    PORT
      LAYER met3 ;
        RECT 6996.000 1608.240 7000.000 1608.840 ;
    END
  END auto_trace_source_out_time[58]
  PIN auto_trace_source_out_time[59]
    DIRECTION OUTPUT TRISTATE ;
    USE SIGNAL ;
    ANTENNADIFFAREA 0.340600 ;
    PORT
      LAYER met2 ;
        RECT 1075.570 0.000 1075.850 4.000 ;
    END
  END auto_trace_source_out_time[59]
  PIN auto_trace_source_out_time[5]
    DIRECTION OUTPUT TRISTATE ;
    USE SIGNAL ;
    ANTENNADIFFAREA 0.340600 ;
    PORT
      LAYER met2 ;
        RECT 1848.370 0.000 1848.650 4.000 ;
    END
  END auto_trace_source_out_time[5]
  PIN auto_trace_source_out_time[60]
    DIRECTION OUTPUT TRISTATE ;
    USE SIGNAL ;
    ANTENNADIFFAREA 0.340600 ;
    PORT
      LAYER met3 ;
        RECT 0.000 261.840 4.000 262.440 ;
    END
  END auto_trace_source_out_time[60]
  PIN auto_trace_source_out_time[61]
    DIRECTION OUTPUT TRISTATE ;
    USE SIGNAL ;
    ANTENNADIFFAREA 0.340600 ;
    PORT
      LAYER met3 ;
        RECT 6996.000 1377.040 7000.000 1377.640 ;
    END
  END auto_trace_source_out_time[61]
  PIN auto_trace_source_out_time[62]
    DIRECTION OUTPUT TRISTATE ;
    USE SIGNAL ;
    ANTENNADIFFAREA 0.340600 ;
    PORT
      LAYER met2 ;
        RECT 2894.870 0.000 2895.150 4.000 ;
    END
  END auto_trace_source_out_time[62]
  PIN auto_trace_source_out_time[63]
    DIRECTION OUTPUT TRISTATE ;
    USE SIGNAL ;
    ANTENNADIFFAREA 0.340600 ;
    PORT
      LAYER met2 ;
        RECT 5287.330 2596.000 5287.610 2600.000 ;
    END
  END auto_trace_source_out_time[63]
  PIN auto_trace_source_out_time[6]
    DIRECTION OUTPUT TRISTATE ;
    USE SIGNAL ;
    ANTENNADIFFAREA 0.340600 ;
    PORT
      LAYER met2 ;
        RECT 5232.590 2596.000 5232.870 2600.000 ;
    END
  END auto_trace_source_out_time[6]
  PIN auto_trace_source_out_time[7]
    DIRECTION OUTPUT TRISTATE ;
    USE SIGNAL ;
    ANTENNADIFFAREA 0.340600 ;
    PORT
      LAYER met2 ;
        RECT 1838.710 2596.000 1838.990 2600.000 ;
    END
  END auto_trace_source_out_time[7]
  PIN auto_trace_source_out_time[8]
    DIRECTION OUTPUT TRISTATE ;
    USE SIGNAL ;
    ANTENNADIFFAREA 0.340600 ;
    PORT
      LAYER met2 ;
        RECT 2695.230 2596.000 2695.510 2600.000 ;
    END
  END auto_trace_source_out_time[8]
  PIN auto_trace_source_out_time[9]
    DIRECTION OUTPUT TRISTATE ;
    USE SIGNAL ;
    ANTENNADIFFAREA 0.340600 ;
    PORT
      LAYER met2 ;
        RECT 3448.710 0.000 3448.990 4.000 ;
    END
  END auto_trace_source_out_time[9]
  PIN auto_wfi_out_0
    DIRECTION OUTPUT TRISTATE ;
    USE SIGNAL ;
    ANTENNADIFFAREA 0.340600 ;
    PORT
      LAYER met3 ;
        RECT 0.000 1047.240 4.000 1047.840 ;
    END
  END auto_wfi_out_0
  PIN clock
    DIRECTION INPUT ;
    USE SIGNAL ;
    ANTENNAGATEAREA 5.199000 ;
    ANTENNADIFFAREA 4.347000 ;
    PORT
      LAYER met2 ;
        RECT 1426.550 2596.000 1426.830 2600.000 ;
    END
  END clock
  PIN reset
    DIRECTION INPUT ;
    USE SIGNAL ;
    ANTENNAGATEAREA 0.852000 ;
    PORT
      LAYER met3 ;
        RECT 6996.000 64.640 7000.000 65.240 ;
    END
  END reset
  OBS
      LAYER li1 ;
        RECT 20.240 21.675 6979.580 2578.645 ;
      LAYER met1 ;
        RECT 0.070 13.980 6993.310 2580.560 ;
      LAYER met2 ;
        RECT 0.100 2595.720 19.130 2596.650 ;
        RECT 19.970 2595.720 44.890 2596.650 ;
        RECT 45.730 2595.720 73.870 2596.650 ;
        RECT 74.710 2595.720 99.630 2596.650 ;
        RECT 100.470 2595.720 128.610 2596.650 ;
        RECT 129.450 2595.720 157.590 2596.650 ;
        RECT 158.430 2595.720 183.350 2596.650 ;
        RECT 184.190 2595.720 212.330 2596.650 ;
        RECT 213.170 2595.720 238.090 2596.650 ;
        RECT 238.930 2595.720 267.070 2596.650 ;
        RECT 267.910 2595.720 292.830 2596.650 ;
        RECT 293.670 2595.720 321.810 2596.650 ;
        RECT 322.650 2595.720 347.570 2596.650 ;
        RECT 348.410 2595.720 376.550 2596.650 ;
        RECT 377.390 2595.720 405.530 2596.650 ;
        RECT 406.370 2595.720 431.290 2596.650 ;
        RECT 432.130 2595.720 460.270 2596.650 ;
        RECT 461.110 2595.720 486.030 2596.650 ;
        RECT 486.870 2595.720 515.010 2596.650 ;
        RECT 515.850 2595.720 540.770 2596.650 ;
        RECT 541.610 2595.720 569.750 2596.650 ;
        RECT 570.590 2595.720 598.730 2596.650 ;
        RECT 599.570 2595.720 624.490 2596.650 ;
        RECT 625.330 2595.720 653.470 2596.650 ;
        RECT 654.310 2595.720 679.230 2596.650 ;
        RECT 680.070 2595.720 708.210 2596.650 ;
        RECT 709.050 2595.720 733.970 2596.650 ;
        RECT 734.810 2595.720 762.950 2596.650 ;
        RECT 763.790 2595.720 791.930 2596.650 ;
        RECT 792.770 2595.720 817.690 2596.650 ;
        RECT 818.530 2595.720 846.670 2596.650 ;
        RECT 847.510 2595.720 872.430 2596.650 ;
        RECT 873.270 2595.720 901.410 2596.650 ;
        RECT 902.250 2595.720 927.170 2596.650 ;
        RECT 928.010 2595.720 956.150 2596.650 ;
        RECT 956.990 2595.720 985.130 2596.650 ;
        RECT 985.970 2595.720 1010.890 2596.650 ;
        RECT 1011.730 2595.720 1039.870 2596.650 ;
        RECT 1040.710 2595.720 1065.630 2596.650 ;
        RECT 1066.470 2595.720 1094.610 2596.650 ;
        RECT 1095.450 2595.720 1120.370 2596.650 ;
        RECT 1121.210 2595.720 1149.350 2596.650 ;
        RECT 1150.190 2595.720 1178.330 2596.650 ;
        RECT 1179.170 2595.720 1204.090 2596.650 ;
        RECT 1204.930 2595.720 1233.070 2596.650 ;
        RECT 1233.910 2595.720 1258.830 2596.650 ;
        RECT 1259.670 2595.720 1287.810 2596.650 ;
        RECT 1288.650 2595.720 1313.570 2596.650 ;
        RECT 1314.410 2595.720 1342.550 2596.650 ;
        RECT 1343.390 2595.720 1371.530 2596.650 ;
        RECT 1372.370 2595.720 1397.290 2596.650 ;
        RECT 1398.130 2595.720 1426.270 2596.650 ;
        RECT 1427.110 2595.720 1452.030 2596.650 ;
        RECT 1452.870 2595.720 1481.010 2596.650 ;
        RECT 1481.850 2595.720 1506.770 2596.650 ;
        RECT 1507.610 2595.720 1535.750 2596.650 ;
        RECT 1536.590 2595.720 1564.730 2596.650 ;
        RECT 1565.570 2595.720 1590.490 2596.650 ;
        RECT 1591.330 2595.720 1619.470 2596.650 ;
        RECT 1620.310 2595.720 1645.230 2596.650 ;
        RECT 1646.070 2595.720 1674.210 2596.650 ;
        RECT 1675.050 2595.720 1699.970 2596.650 ;
        RECT 1700.810 2595.720 1728.950 2596.650 ;
        RECT 1729.790 2595.720 1754.710 2596.650 ;
        RECT 1755.550 2595.720 1783.690 2596.650 ;
        RECT 1784.530 2595.720 1812.670 2596.650 ;
        RECT 1813.510 2595.720 1838.430 2596.650 ;
        RECT 1839.270 2595.720 1867.410 2596.650 ;
        RECT 1868.250 2595.720 1893.170 2596.650 ;
        RECT 1894.010 2595.720 1922.150 2596.650 ;
        RECT 1922.990 2595.720 1947.910 2596.650 ;
        RECT 1948.750 2595.720 1976.890 2596.650 ;
        RECT 1977.730 2595.720 2005.870 2596.650 ;
        RECT 2006.710 2595.720 2031.630 2596.650 ;
        RECT 2032.470 2595.720 2060.610 2596.650 ;
        RECT 2061.450 2595.720 2086.370 2596.650 ;
        RECT 2087.210 2595.720 2115.350 2596.650 ;
        RECT 2116.190 2595.720 2141.110 2596.650 ;
        RECT 2141.950 2595.720 2170.090 2596.650 ;
        RECT 2170.930 2595.720 2199.070 2596.650 ;
        RECT 2199.910 2595.720 2224.830 2596.650 ;
        RECT 2225.670 2595.720 2253.810 2596.650 ;
        RECT 2254.650 2595.720 2279.570 2596.650 ;
        RECT 2280.410 2595.720 2308.550 2596.650 ;
        RECT 2309.390 2595.720 2334.310 2596.650 ;
        RECT 2335.150 2595.720 2363.290 2596.650 ;
        RECT 2364.130 2595.720 2392.270 2596.650 ;
        RECT 2393.110 2595.720 2418.030 2596.650 ;
        RECT 2418.870 2595.720 2447.010 2596.650 ;
        RECT 2447.850 2595.720 2472.770 2596.650 ;
        RECT 2473.610 2595.720 2501.750 2596.650 ;
        RECT 2502.590 2595.720 2527.510 2596.650 ;
        RECT 2528.350 2595.720 2556.490 2596.650 ;
        RECT 2557.330 2595.720 2585.470 2596.650 ;
        RECT 2586.310 2595.720 2611.230 2596.650 ;
        RECT 2612.070 2595.720 2640.210 2596.650 ;
        RECT 2641.050 2595.720 2665.970 2596.650 ;
        RECT 2666.810 2595.720 2694.950 2596.650 ;
        RECT 2695.790 2595.720 2720.710 2596.650 ;
        RECT 2721.550 2595.720 2749.690 2596.650 ;
        RECT 2750.530 2595.720 2778.670 2596.650 ;
        RECT 2779.510 2595.720 2804.430 2596.650 ;
        RECT 2805.270 2595.720 2833.410 2596.650 ;
        RECT 2834.250 2595.720 2859.170 2596.650 ;
        RECT 2860.010 2595.720 2888.150 2596.650 ;
        RECT 2888.990 2595.720 2913.910 2596.650 ;
        RECT 2914.750 2595.720 2942.890 2596.650 ;
        RECT 2943.730 2595.720 2968.650 2596.650 ;
        RECT 2969.490 2595.720 2997.630 2596.650 ;
        RECT 2998.470 2595.720 3026.610 2596.650 ;
        RECT 3027.450 2595.720 3052.370 2596.650 ;
        RECT 3053.210 2595.720 3081.350 2596.650 ;
        RECT 3082.190 2595.720 3107.110 2596.650 ;
        RECT 3107.950 2595.720 3136.090 2596.650 ;
        RECT 3136.930 2595.720 3161.850 2596.650 ;
        RECT 3162.690 2595.720 3190.830 2596.650 ;
        RECT 3191.670 2595.720 3219.810 2596.650 ;
        RECT 3220.650 2595.720 3245.570 2596.650 ;
        RECT 3246.410 2595.720 3274.550 2596.650 ;
        RECT 3275.390 2595.720 3300.310 2596.650 ;
        RECT 3301.150 2595.720 3329.290 2596.650 ;
        RECT 3330.130 2595.720 3355.050 2596.650 ;
        RECT 3355.890 2595.720 3384.030 2596.650 ;
        RECT 3384.870 2595.720 3413.010 2596.650 ;
        RECT 3413.850 2595.720 3438.770 2596.650 ;
        RECT 3439.610 2595.720 3467.750 2596.650 ;
        RECT 3468.590 2595.720 3493.510 2596.650 ;
        RECT 3494.350 2595.720 3522.490 2596.650 ;
        RECT 3523.330 2595.720 3548.250 2596.650 ;
        RECT 3549.090 2595.720 3577.230 2596.650 ;
        RECT 3578.070 2595.720 3606.210 2596.650 ;
        RECT 3607.050 2595.720 3631.970 2596.650 ;
        RECT 3632.810 2595.720 3660.950 2596.650 ;
        RECT 3661.790 2595.720 3686.710 2596.650 ;
        RECT 3687.550 2595.720 3715.690 2596.650 ;
        RECT 3716.530 2595.720 3741.450 2596.650 ;
        RECT 3742.290 2595.720 3770.430 2596.650 ;
        RECT 3771.270 2595.720 3799.410 2596.650 ;
        RECT 3800.250 2595.720 3825.170 2596.650 ;
        RECT 3826.010 2595.720 3854.150 2596.650 ;
        RECT 3854.990 2595.720 3879.910 2596.650 ;
        RECT 3880.750 2595.720 3908.890 2596.650 ;
        RECT 3909.730 2595.720 3934.650 2596.650 ;
        RECT 3935.490 2595.720 3963.630 2596.650 ;
        RECT 3964.470 2595.720 3992.610 2596.650 ;
        RECT 3993.450 2595.720 4018.370 2596.650 ;
        RECT 4019.210 2595.720 4047.350 2596.650 ;
        RECT 4048.190 2595.720 4073.110 2596.650 ;
        RECT 4073.950 2595.720 4102.090 2596.650 ;
        RECT 4102.930 2595.720 4127.850 2596.650 ;
        RECT 4128.690 2595.720 4156.830 2596.650 ;
        RECT 4157.670 2595.720 4185.810 2596.650 ;
        RECT 4186.650 2595.720 4211.570 2596.650 ;
        RECT 4212.410 2595.720 4240.550 2596.650 ;
        RECT 4241.390 2595.720 4266.310 2596.650 ;
        RECT 4267.150 2595.720 4295.290 2596.650 ;
        RECT 4296.130 2595.720 4321.050 2596.650 ;
        RECT 4321.890 2595.720 4350.030 2596.650 ;
        RECT 4350.870 2595.720 4375.790 2596.650 ;
        RECT 4376.630 2595.720 4404.770 2596.650 ;
        RECT 4405.610 2595.720 4433.750 2596.650 ;
        RECT 4434.590 2595.720 4459.510 2596.650 ;
        RECT 4460.350 2595.720 4488.490 2596.650 ;
        RECT 4489.330 2595.720 4514.250 2596.650 ;
        RECT 4515.090 2595.720 4543.230 2596.650 ;
        RECT 4544.070 2595.720 4568.990 2596.650 ;
        RECT 4569.830 2595.720 4597.970 2596.650 ;
        RECT 4598.810 2595.720 4626.950 2596.650 ;
        RECT 4627.790 2595.720 4652.710 2596.650 ;
        RECT 4653.550 2595.720 4681.690 2596.650 ;
        RECT 4682.530 2595.720 4707.450 2596.650 ;
        RECT 4708.290 2595.720 4736.430 2596.650 ;
        RECT 4737.270 2595.720 4762.190 2596.650 ;
        RECT 4763.030 2595.720 4791.170 2596.650 ;
        RECT 4792.010 2595.720 4820.150 2596.650 ;
        RECT 4820.990 2595.720 4845.910 2596.650 ;
        RECT 4846.750 2595.720 4874.890 2596.650 ;
        RECT 4875.730 2595.720 4900.650 2596.650 ;
        RECT 4901.490 2595.720 4929.630 2596.650 ;
        RECT 4930.470 2595.720 4955.390 2596.650 ;
        RECT 4956.230 2595.720 4984.370 2596.650 ;
        RECT 4985.210 2595.720 5013.350 2596.650 ;
        RECT 5014.190 2595.720 5039.110 2596.650 ;
        RECT 5039.950 2595.720 5068.090 2596.650 ;
        RECT 5068.930 2595.720 5093.850 2596.650 ;
        RECT 5094.690 2595.720 5122.830 2596.650 ;
        RECT 5123.670 2595.720 5148.590 2596.650 ;
        RECT 5149.430 2595.720 5177.570 2596.650 ;
        RECT 5178.410 2595.720 5206.550 2596.650 ;
        RECT 5207.390 2595.720 5232.310 2596.650 ;
        RECT 5233.150 2595.720 5261.290 2596.650 ;
        RECT 5262.130 2595.720 5287.050 2596.650 ;
        RECT 5287.890 2595.720 5316.030 2596.650 ;
        RECT 5316.870 2595.720 5341.790 2596.650 ;
        RECT 5342.630 2595.720 5370.770 2596.650 ;
        RECT 5371.610 2595.720 5399.750 2596.650 ;
        RECT 5400.590 2595.720 5425.510 2596.650 ;
        RECT 5426.350 2595.720 5454.490 2596.650 ;
        RECT 5455.330 2595.720 5480.250 2596.650 ;
        RECT 5481.090 2595.720 5509.230 2596.650 ;
        RECT 5510.070 2595.720 5534.990 2596.650 ;
        RECT 5535.830 2595.720 5563.970 2596.650 ;
        RECT 5564.810 2595.720 5592.950 2596.650 ;
        RECT 5593.790 2595.720 5618.710 2596.650 ;
        RECT 5619.550 2595.720 5647.690 2596.650 ;
        RECT 5648.530 2595.720 5673.450 2596.650 ;
        RECT 5674.290 2595.720 5702.430 2596.650 ;
        RECT 5703.270 2595.720 5728.190 2596.650 ;
        RECT 5729.030 2595.720 5757.170 2596.650 ;
        RECT 5758.010 2595.720 5782.930 2596.650 ;
        RECT 5783.770 2595.720 5811.910 2596.650 ;
        RECT 5812.750 2595.720 5840.890 2596.650 ;
        RECT 5841.730 2595.720 5866.650 2596.650 ;
        RECT 5867.490 2595.720 5895.630 2596.650 ;
        RECT 5896.470 2595.720 5921.390 2596.650 ;
        RECT 5922.230 2595.720 5950.370 2596.650 ;
        RECT 5951.210 2595.720 5976.130 2596.650 ;
        RECT 5976.970 2595.720 6005.110 2596.650 ;
        RECT 6005.950 2595.720 6034.090 2596.650 ;
        RECT 6034.930 2595.720 6059.850 2596.650 ;
        RECT 6060.690 2595.720 6088.830 2596.650 ;
        RECT 6089.670 2595.720 6114.590 2596.650 ;
        RECT 6115.430 2595.720 6143.570 2596.650 ;
        RECT 6144.410 2595.720 6169.330 2596.650 ;
        RECT 6170.170 2595.720 6198.310 2596.650 ;
        RECT 6199.150 2595.720 6227.290 2596.650 ;
        RECT 6228.130 2595.720 6253.050 2596.650 ;
        RECT 6253.890 2595.720 6282.030 2596.650 ;
        RECT 6282.870 2595.720 6307.790 2596.650 ;
        RECT 6308.630 2595.720 6336.770 2596.650 ;
        RECT 6337.610 2595.720 6362.530 2596.650 ;
        RECT 6363.370 2595.720 6391.510 2596.650 ;
        RECT 6392.350 2595.720 6420.490 2596.650 ;
        RECT 6421.330 2595.720 6446.250 2596.650 ;
        RECT 6447.090 2595.720 6475.230 2596.650 ;
        RECT 6476.070 2595.720 6500.990 2596.650 ;
        RECT 6501.830 2595.720 6529.970 2596.650 ;
        RECT 6530.810 2595.720 6555.730 2596.650 ;
        RECT 6556.570 2595.720 6584.710 2596.650 ;
        RECT 6585.550 2595.720 6613.690 2596.650 ;
        RECT 6614.530 2595.720 6639.450 2596.650 ;
        RECT 6640.290 2595.720 6668.430 2596.650 ;
        RECT 6669.270 2595.720 6694.190 2596.650 ;
        RECT 6695.030 2595.720 6723.170 2596.650 ;
        RECT 6724.010 2595.720 6748.930 2596.650 ;
        RECT 6749.770 2595.720 6777.910 2596.650 ;
        RECT 6778.750 2595.720 6806.890 2596.650 ;
        RECT 6807.730 2595.720 6832.650 2596.650 ;
        RECT 6833.490 2595.720 6861.630 2596.650 ;
        RECT 6862.470 2595.720 6887.390 2596.650 ;
        RECT 6888.230 2595.720 6916.370 2596.650 ;
        RECT 6917.210 2595.720 6942.130 2596.650 ;
        RECT 6942.970 2595.720 6971.110 2596.650 ;
        RECT 6971.950 2595.720 6993.290 2596.650 ;
        RECT 0.100 4.280 6993.290 2595.720 ;
        RECT 0.650 3.670 25.570 4.280 ;
        RECT 26.410 3.670 54.550 4.280 ;
        RECT 55.390 3.670 80.310 4.280 ;
        RECT 81.150 3.670 109.290 4.280 ;
        RECT 110.130 3.670 135.050 4.280 ;
        RECT 135.890 3.670 164.030 4.280 ;
        RECT 164.870 3.670 189.790 4.280 ;
        RECT 190.630 3.670 218.770 4.280 ;
        RECT 219.610 3.670 247.750 4.280 ;
        RECT 248.590 3.670 273.510 4.280 ;
        RECT 274.350 3.670 302.490 4.280 ;
        RECT 303.330 3.670 328.250 4.280 ;
        RECT 329.090 3.670 357.230 4.280 ;
        RECT 358.070 3.670 382.990 4.280 ;
        RECT 383.830 3.670 411.970 4.280 ;
        RECT 412.810 3.670 440.950 4.280 ;
        RECT 441.790 3.670 466.710 4.280 ;
        RECT 467.550 3.670 495.690 4.280 ;
        RECT 496.530 3.670 521.450 4.280 ;
        RECT 522.290 3.670 550.430 4.280 ;
        RECT 551.270 3.670 576.190 4.280 ;
        RECT 577.030 3.670 605.170 4.280 ;
        RECT 606.010 3.670 634.150 4.280 ;
        RECT 634.990 3.670 659.910 4.280 ;
        RECT 660.750 3.670 688.890 4.280 ;
        RECT 689.730 3.670 714.650 4.280 ;
        RECT 715.490 3.670 743.630 4.280 ;
        RECT 744.470 3.670 769.390 4.280 ;
        RECT 770.230 3.670 798.370 4.280 ;
        RECT 799.210 3.670 827.350 4.280 ;
        RECT 828.190 3.670 853.110 4.280 ;
        RECT 853.950 3.670 882.090 4.280 ;
        RECT 882.930 3.670 907.850 4.280 ;
        RECT 908.690 3.670 936.830 4.280 ;
        RECT 937.670 3.670 962.590 4.280 ;
        RECT 963.430 3.670 991.570 4.280 ;
        RECT 992.410 3.670 1020.550 4.280 ;
        RECT 1021.390 3.670 1046.310 4.280 ;
        RECT 1047.150 3.670 1075.290 4.280 ;
        RECT 1076.130 3.670 1101.050 4.280 ;
        RECT 1101.890 3.670 1130.030 4.280 ;
        RECT 1130.870 3.670 1155.790 4.280 ;
        RECT 1156.630 3.670 1184.770 4.280 ;
        RECT 1185.610 3.670 1213.750 4.280 ;
        RECT 1214.590 3.670 1239.510 4.280 ;
        RECT 1240.350 3.670 1268.490 4.280 ;
        RECT 1269.330 3.670 1294.250 4.280 ;
        RECT 1295.090 3.670 1323.230 4.280 ;
        RECT 1324.070 3.670 1348.990 4.280 ;
        RECT 1349.830 3.670 1377.970 4.280 ;
        RECT 1378.810 3.670 1403.730 4.280 ;
        RECT 1404.570 3.670 1432.710 4.280 ;
        RECT 1433.550 3.670 1461.690 4.280 ;
        RECT 1462.530 3.670 1487.450 4.280 ;
        RECT 1488.290 3.670 1516.430 4.280 ;
        RECT 1517.270 3.670 1542.190 4.280 ;
        RECT 1543.030 3.670 1571.170 4.280 ;
        RECT 1572.010 3.670 1596.930 4.280 ;
        RECT 1597.770 3.670 1625.910 4.280 ;
        RECT 1626.750 3.670 1654.890 4.280 ;
        RECT 1655.730 3.670 1680.650 4.280 ;
        RECT 1681.490 3.670 1709.630 4.280 ;
        RECT 1710.470 3.670 1735.390 4.280 ;
        RECT 1736.230 3.670 1764.370 4.280 ;
        RECT 1765.210 3.670 1790.130 4.280 ;
        RECT 1790.970 3.670 1819.110 4.280 ;
        RECT 1819.950 3.670 1848.090 4.280 ;
        RECT 1848.930 3.670 1873.850 4.280 ;
        RECT 1874.690 3.670 1902.830 4.280 ;
        RECT 1903.670 3.670 1928.590 4.280 ;
        RECT 1929.430 3.670 1957.570 4.280 ;
        RECT 1958.410 3.670 1983.330 4.280 ;
        RECT 1984.170 3.670 2012.310 4.280 ;
        RECT 2013.150 3.670 2041.290 4.280 ;
        RECT 2042.130 3.670 2067.050 4.280 ;
        RECT 2067.890 3.670 2096.030 4.280 ;
        RECT 2096.870 3.670 2121.790 4.280 ;
        RECT 2122.630 3.670 2150.770 4.280 ;
        RECT 2151.610 3.670 2176.530 4.280 ;
        RECT 2177.370 3.670 2205.510 4.280 ;
        RECT 2206.350 3.670 2234.490 4.280 ;
        RECT 2235.330 3.670 2260.250 4.280 ;
        RECT 2261.090 3.670 2289.230 4.280 ;
        RECT 2290.070 3.670 2314.990 4.280 ;
        RECT 2315.830 3.670 2343.970 4.280 ;
        RECT 2344.810 3.670 2369.730 4.280 ;
        RECT 2370.570 3.670 2398.710 4.280 ;
        RECT 2399.550 3.670 2427.690 4.280 ;
        RECT 2428.530 3.670 2453.450 4.280 ;
        RECT 2454.290 3.670 2482.430 4.280 ;
        RECT 2483.270 3.670 2508.190 4.280 ;
        RECT 2509.030 3.670 2537.170 4.280 ;
        RECT 2538.010 3.670 2562.930 4.280 ;
        RECT 2563.770 3.670 2591.910 4.280 ;
        RECT 2592.750 3.670 2620.890 4.280 ;
        RECT 2621.730 3.670 2646.650 4.280 ;
        RECT 2647.490 3.670 2675.630 4.280 ;
        RECT 2676.470 3.670 2701.390 4.280 ;
        RECT 2702.230 3.670 2730.370 4.280 ;
        RECT 2731.210 3.670 2756.130 4.280 ;
        RECT 2756.970 3.670 2785.110 4.280 ;
        RECT 2785.950 3.670 2810.870 4.280 ;
        RECT 2811.710 3.670 2839.850 4.280 ;
        RECT 2840.690 3.670 2868.830 4.280 ;
        RECT 2869.670 3.670 2894.590 4.280 ;
        RECT 2895.430 3.670 2923.570 4.280 ;
        RECT 2924.410 3.670 2949.330 4.280 ;
        RECT 2950.170 3.670 2978.310 4.280 ;
        RECT 2979.150 3.670 3004.070 4.280 ;
        RECT 3004.910 3.670 3033.050 4.280 ;
        RECT 3033.890 3.670 3062.030 4.280 ;
        RECT 3062.870 3.670 3087.790 4.280 ;
        RECT 3088.630 3.670 3116.770 4.280 ;
        RECT 3117.610 3.670 3142.530 4.280 ;
        RECT 3143.370 3.670 3171.510 4.280 ;
        RECT 3172.350 3.670 3197.270 4.280 ;
        RECT 3198.110 3.670 3226.250 4.280 ;
        RECT 3227.090 3.670 3255.230 4.280 ;
        RECT 3256.070 3.670 3280.990 4.280 ;
        RECT 3281.830 3.670 3309.970 4.280 ;
        RECT 3310.810 3.670 3335.730 4.280 ;
        RECT 3336.570 3.670 3364.710 4.280 ;
        RECT 3365.550 3.670 3390.470 4.280 ;
        RECT 3391.310 3.670 3419.450 4.280 ;
        RECT 3420.290 3.670 3448.430 4.280 ;
        RECT 3449.270 3.670 3474.190 4.280 ;
        RECT 3475.030 3.670 3503.170 4.280 ;
        RECT 3504.010 3.670 3528.930 4.280 ;
        RECT 3529.770 3.670 3557.910 4.280 ;
        RECT 3558.750 3.670 3583.670 4.280 ;
        RECT 3584.510 3.670 3612.650 4.280 ;
        RECT 3613.490 3.670 3641.630 4.280 ;
        RECT 3642.470 3.670 3667.390 4.280 ;
        RECT 3668.230 3.670 3696.370 4.280 ;
        RECT 3697.210 3.670 3722.130 4.280 ;
        RECT 3722.970 3.670 3751.110 4.280 ;
        RECT 3751.950 3.670 3776.870 4.280 ;
        RECT 3777.710 3.670 3805.850 4.280 ;
        RECT 3806.690 3.670 3834.830 4.280 ;
        RECT 3835.670 3.670 3860.590 4.280 ;
        RECT 3861.430 3.670 3889.570 4.280 ;
        RECT 3890.410 3.670 3915.330 4.280 ;
        RECT 3916.170 3.670 3944.310 4.280 ;
        RECT 3945.150 3.670 3970.070 4.280 ;
        RECT 3970.910 3.670 3999.050 4.280 ;
        RECT 3999.890 3.670 4028.030 4.280 ;
        RECT 4028.870 3.670 4053.790 4.280 ;
        RECT 4054.630 3.670 4082.770 4.280 ;
        RECT 4083.610 3.670 4108.530 4.280 ;
        RECT 4109.370 3.670 4137.510 4.280 ;
        RECT 4138.350 3.670 4163.270 4.280 ;
        RECT 4164.110 3.670 4192.250 4.280 ;
        RECT 4193.090 3.670 4218.010 4.280 ;
        RECT 4218.850 3.670 4246.990 4.280 ;
        RECT 4247.830 3.670 4275.970 4.280 ;
        RECT 4276.810 3.670 4301.730 4.280 ;
        RECT 4302.570 3.670 4330.710 4.280 ;
        RECT 4331.550 3.670 4356.470 4.280 ;
        RECT 4357.310 3.670 4385.450 4.280 ;
        RECT 4386.290 3.670 4411.210 4.280 ;
        RECT 4412.050 3.670 4440.190 4.280 ;
        RECT 4441.030 3.670 4469.170 4.280 ;
        RECT 4470.010 3.670 4494.930 4.280 ;
        RECT 4495.770 3.670 4523.910 4.280 ;
        RECT 4524.750 3.670 4549.670 4.280 ;
        RECT 4550.510 3.670 4578.650 4.280 ;
        RECT 4579.490 3.670 4604.410 4.280 ;
        RECT 4605.250 3.670 4633.390 4.280 ;
        RECT 4634.230 3.670 4662.370 4.280 ;
        RECT 4663.210 3.670 4688.130 4.280 ;
        RECT 4688.970 3.670 4717.110 4.280 ;
        RECT 4717.950 3.670 4742.870 4.280 ;
        RECT 4743.710 3.670 4771.850 4.280 ;
        RECT 4772.690 3.670 4797.610 4.280 ;
        RECT 4798.450 3.670 4826.590 4.280 ;
        RECT 4827.430 3.670 4855.570 4.280 ;
        RECT 4856.410 3.670 4881.330 4.280 ;
        RECT 4882.170 3.670 4910.310 4.280 ;
        RECT 4911.150 3.670 4936.070 4.280 ;
        RECT 4936.910 3.670 4965.050 4.280 ;
        RECT 4965.890 3.670 4990.810 4.280 ;
        RECT 4991.650 3.670 5019.790 4.280 ;
        RECT 5020.630 3.670 5048.770 4.280 ;
        RECT 5049.610 3.670 5074.530 4.280 ;
        RECT 5075.370 3.670 5103.510 4.280 ;
        RECT 5104.350 3.670 5129.270 4.280 ;
        RECT 5130.110 3.670 5158.250 4.280 ;
        RECT 5159.090 3.670 5184.010 4.280 ;
        RECT 5184.850 3.670 5212.990 4.280 ;
        RECT 5213.830 3.670 5241.970 4.280 ;
        RECT 5242.810 3.670 5267.730 4.280 ;
        RECT 5268.570 3.670 5296.710 4.280 ;
        RECT 5297.550 3.670 5322.470 4.280 ;
        RECT 5323.310 3.670 5351.450 4.280 ;
        RECT 5352.290 3.670 5377.210 4.280 ;
        RECT 5378.050 3.670 5406.190 4.280 ;
        RECT 5407.030 3.670 5431.950 4.280 ;
        RECT 5432.790 3.670 5460.930 4.280 ;
        RECT 5461.770 3.670 5489.910 4.280 ;
        RECT 5490.750 3.670 5515.670 4.280 ;
        RECT 5516.510 3.670 5544.650 4.280 ;
        RECT 5545.490 3.670 5570.410 4.280 ;
        RECT 5571.250 3.670 5599.390 4.280 ;
        RECT 5600.230 3.670 5625.150 4.280 ;
        RECT 5625.990 3.670 5654.130 4.280 ;
        RECT 5654.970 3.670 5683.110 4.280 ;
        RECT 5683.950 3.670 5708.870 4.280 ;
        RECT 5709.710 3.670 5737.850 4.280 ;
        RECT 5738.690 3.670 5763.610 4.280 ;
        RECT 5764.450 3.670 5792.590 4.280 ;
        RECT 5793.430 3.670 5818.350 4.280 ;
        RECT 5819.190 3.670 5847.330 4.280 ;
        RECT 5848.170 3.670 5876.310 4.280 ;
        RECT 5877.150 3.670 5902.070 4.280 ;
        RECT 5902.910 3.670 5931.050 4.280 ;
        RECT 5931.890 3.670 5956.810 4.280 ;
        RECT 5957.650 3.670 5985.790 4.280 ;
        RECT 5986.630 3.670 6011.550 4.280 ;
        RECT 6012.390 3.670 6040.530 4.280 ;
        RECT 6041.370 3.670 6069.510 4.280 ;
        RECT 6070.350 3.670 6095.270 4.280 ;
        RECT 6096.110 3.670 6124.250 4.280 ;
        RECT 6125.090 3.670 6150.010 4.280 ;
        RECT 6150.850 3.670 6178.990 4.280 ;
        RECT 6179.830 3.670 6204.750 4.280 ;
        RECT 6205.590 3.670 6233.730 4.280 ;
        RECT 6234.570 3.670 6262.710 4.280 ;
        RECT 6263.550 3.670 6288.470 4.280 ;
        RECT 6289.310 3.670 6317.450 4.280 ;
        RECT 6318.290 3.670 6343.210 4.280 ;
        RECT 6344.050 3.670 6372.190 4.280 ;
        RECT 6373.030 3.670 6397.950 4.280 ;
        RECT 6398.790 3.670 6426.930 4.280 ;
        RECT 6427.770 3.670 6455.910 4.280 ;
        RECT 6456.750 3.670 6481.670 4.280 ;
        RECT 6482.510 3.670 6510.650 4.280 ;
        RECT 6511.490 3.670 6536.410 4.280 ;
        RECT 6537.250 3.670 6565.390 4.280 ;
        RECT 6566.230 3.670 6591.150 4.280 ;
        RECT 6591.990 3.670 6620.130 4.280 ;
        RECT 6620.970 3.670 6649.110 4.280 ;
        RECT 6649.950 3.670 6674.870 4.280 ;
        RECT 6675.710 3.670 6703.850 4.280 ;
        RECT 6704.690 3.670 6729.610 4.280 ;
        RECT 6730.450 3.670 6758.590 4.280 ;
        RECT 6759.430 3.670 6784.350 4.280 ;
        RECT 6785.190 3.670 6813.330 4.280 ;
        RECT 6814.170 3.670 6839.090 4.280 ;
        RECT 6839.930 3.670 6868.070 4.280 ;
        RECT 6868.910 3.670 6897.050 4.280 ;
        RECT 6897.890 3.670 6922.810 4.280 ;
        RECT 6923.650 3.670 6951.790 4.280 ;
        RECT 6952.630 3.670 6977.550 4.280 ;
        RECT 6978.390 3.670 6993.290 4.280 ;
      LAYER met3 ;
        RECT 4.000 2571.440 6996.000 2581.100 ;
        RECT 4.000 2570.040 6995.600 2571.440 ;
        RECT 4.000 2564.640 6996.000 2570.040 ;
        RECT 4.400 2563.240 6996.000 2564.640 ;
        RECT 4.000 2540.840 6996.000 2563.240 ;
        RECT 4.000 2539.440 6995.600 2540.840 ;
        RECT 4.000 2534.040 6996.000 2539.440 ;
        RECT 4.400 2532.640 6996.000 2534.040 ;
        RECT 4.000 2513.640 6996.000 2532.640 ;
        RECT 4.000 2512.240 6995.600 2513.640 ;
        RECT 4.000 2503.440 6996.000 2512.240 ;
        RECT 4.400 2502.040 6996.000 2503.440 ;
        RECT 4.000 2483.040 6996.000 2502.040 ;
        RECT 4.000 2481.640 6995.600 2483.040 ;
        RECT 4.000 2476.240 6996.000 2481.640 ;
        RECT 4.400 2474.840 6996.000 2476.240 ;
        RECT 4.000 2455.840 6996.000 2474.840 ;
        RECT 4.000 2454.440 6995.600 2455.840 ;
        RECT 4.000 2445.640 6996.000 2454.440 ;
        RECT 4.400 2444.240 6996.000 2445.640 ;
        RECT 4.000 2425.240 6996.000 2444.240 ;
        RECT 4.000 2423.840 6995.600 2425.240 ;
        RECT 4.000 2418.440 6996.000 2423.840 ;
        RECT 4.400 2417.040 6996.000 2418.440 ;
        RECT 4.000 2398.040 6996.000 2417.040 ;
        RECT 4.000 2396.640 6995.600 2398.040 ;
        RECT 4.000 2387.840 6996.000 2396.640 ;
        RECT 4.400 2386.440 6996.000 2387.840 ;
        RECT 4.000 2367.440 6996.000 2386.440 ;
        RECT 4.000 2366.040 6995.600 2367.440 ;
        RECT 4.000 2360.640 6996.000 2366.040 ;
        RECT 4.400 2359.240 6996.000 2360.640 ;
        RECT 4.000 2336.840 6996.000 2359.240 ;
        RECT 4.000 2335.440 6995.600 2336.840 ;
        RECT 4.000 2330.040 6996.000 2335.440 ;
        RECT 4.400 2328.640 6996.000 2330.040 ;
        RECT 4.000 2309.640 6996.000 2328.640 ;
        RECT 4.000 2308.240 6995.600 2309.640 ;
        RECT 4.000 2299.440 6996.000 2308.240 ;
        RECT 4.400 2298.040 6996.000 2299.440 ;
        RECT 4.000 2279.040 6996.000 2298.040 ;
        RECT 4.000 2277.640 6995.600 2279.040 ;
        RECT 4.000 2272.240 6996.000 2277.640 ;
        RECT 4.400 2270.840 6996.000 2272.240 ;
        RECT 4.000 2251.840 6996.000 2270.840 ;
        RECT 4.000 2250.440 6995.600 2251.840 ;
        RECT 4.000 2241.640 6996.000 2250.440 ;
        RECT 4.400 2240.240 6996.000 2241.640 ;
        RECT 4.000 2221.240 6996.000 2240.240 ;
        RECT 4.000 2219.840 6995.600 2221.240 ;
        RECT 4.000 2214.440 6996.000 2219.840 ;
        RECT 4.400 2213.040 6996.000 2214.440 ;
        RECT 4.000 2194.040 6996.000 2213.040 ;
        RECT 4.000 2192.640 6995.600 2194.040 ;
        RECT 4.000 2183.840 6996.000 2192.640 ;
        RECT 4.400 2182.440 6996.000 2183.840 ;
        RECT 4.000 2163.440 6996.000 2182.440 ;
        RECT 4.000 2162.040 6995.600 2163.440 ;
        RECT 4.000 2156.640 6996.000 2162.040 ;
        RECT 4.400 2155.240 6996.000 2156.640 ;
        RECT 4.000 2132.840 6996.000 2155.240 ;
        RECT 4.000 2131.440 6995.600 2132.840 ;
        RECT 4.000 2126.040 6996.000 2131.440 ;
        RECT 4.400 2124.640 6996.000 2126.040 ;
        RECT 4.000 2105.640 6996.000 2124.640 ;
        RECT 4.000 2104.240 6995.600 2105.640 ;
        RECT 4.000 2095.440 6996.000 2104.240 ;
        RECT 4.400 2094.040 6996.000 2095.440 ;
        RECT 4.000 2075.040 6996.000 2094.040 ;
        RECT 4.000 2073.640 6995.600 2075.040 ;
        RECT 4.000 2068.240 6996.000 2073.640 ;
        RECT 4.400 2066.840 6996.000 2068.240 ;
        RECT 4.000 2047.840 6996.000 2066.840 ;
        RECT 4.000 2046.440 6995.600 2047.840 ;
        RECT 4.000 2037.640 6996.000 2046.440 ;
        RECT 4.400 2036.240 6996.000 2037.640 ;
        RECT 4.000 2017.240 6996.000 2036.240 ;
        RECT 4.000 2015.840 6995.600 2017.240 ;
        RECT 4.000 2010.440 6996.000 2015.840 ;
        RECT 4.400 2009.040 6996.000 2010.440 ;
        RECT 4.000 1990.040 6996.000 2009.040 ;
        RECT 4.000 1988.640 6995.600 1990.040 ;
        RECT 4.000 1979.840 6996.000 1988.640 ;
        RECT 4.400 1978.440 6996.000 1979.840 ;
        RECT 4.000 1959.440 6996.000 1978.440 ;
        RECT 4.000 1958.040 6995.600 1959.440 ;
        RECT 4.000 1952.640 6996.000 1958.040 ;
        RECT 4.400 1951.240 6996.000 1952.640 ;
        RECT 4.000 1928.840 6996.000 1951.240 ;
        RECT 4.000 1927.440 6995.600 1928.840 ;
        RECT 4.000 1922.040 6996.000 1927.440 ;
        RECT 4.400 1920.640 6996.000 1922.040 ;
        RECT 4.000 1901.640 6996.000 1920.640 ;
        RECT 4.000 1900.240 6995.600 1901.640 ;
        RECT 4.000 1891.440 6996.000 1900.240 ;
        RECT 4.400 1890.040 6996.000 1891.440 ;
        RECT 4.000 1871.040 6996.000 1890.040 ;
        RECT 4.000 1869.640 6995.600 1871.040 ;
        RECT 4.000 1864.240 6996.000 1869.640 ;
        RECT 4.400 1862.840 6996.000 1864.240 ;
        RECT 4.000 1843.840 6996.000 1862.840 ;
        RECT 4.000 1842.440 6995.600 1843.840 ;
        RECT 4.000 1833.640 6996.000 1842.440 ;
        RECT 4.400 1832.240 6996.000 1833.640 ;
        RECT 4.000 1813.240 6996.000 1832.240 ;
        RECT 4.000 1811.840 6995.600 1813.240 ;
        RECT 4.000 1806.440 6996.000 1811.840 ;
        RECT 4.400 1805.040 6996.000 1806.440 ;
        RECT 4.000 1786.040 6996.000 1805.040 ;
        RECT 4.000 1784.640 6995.600 1786.040 ;
        RECT 4.000 1775.840 6996.000 1784.640 ;
        RECT 4.400 1774.440 6996.000 1775.840 ;
        RECT 4.000 1755.440 6996.000 1774.440 ;
        RECT 4.000 1754.040 6995.600 1755.440 ;
        RECT 4.000 1748.640 6996.000 1754.040 ;
        RECT 4.400 1747.240 6996.000 1748.640 ;
        RECT 4.000 1724.840 6996.000 1747.240 ;
        RECT 4.000 1723.440 6995.600 1724.840 ;
        RECT 4.000 1718.040 6996.000 1723.440 ;
        RECT 4.400 1716.640 6996.000 1718.040 ;
        RECT 4.000 1697.640 6996.000 1716.640 ;
        RECT 4.000 1696.240 6995.600 1697.640 ;
        RECT 4.000 1687.440 6996.000 1696.240 ;
        RECT 4.400 1686.040 6996.000 1687.440 ;
        RECT 4.000 1667.040 6996.000 1686.040 ;
        RECT 4.000 1665.640 6995.600 1667.040 ;
        RECT 4.000 1660.240 6996.000 1665.640 ;
        RECT 4.400 1658.840 6996.000 1660.240 ;
        RECT 4.000 1639.840 6996.000 1658.840 ;
        RECT 4.000 1638.440 6995.600 1639.840 ;
        RECT 4.000 1629.640 6996.000 1638.440 ;
        RECT 4.400 1628.240 6996.000 1629.640 ;
        RECT 4.000 1609.240 6996.000 1628.240 ;
        RECT 4.000 1607.840 6995.600 1609.240 ;
        RECT 4.000 1602.440 6996.000 1607.840 ;
        RECT 4.400 1601.040 6996.000 1602.440 ;
        RECT 4.000 1582.040 6996.000 1601.040 ;
        RECT 4.000 1580.640 6995.600 1582.040 ;
        RECT 4.000 1571.840 6996.000 1580.640 ;
        RECT 4.400 1570.440 6996.000 1571.840 ;
        RECT 4.000 1551.440 6996.000 1570.440 ;
        RECT 4.000 1550.040 6995.600 1551.440 ;
        RECT 4.000 1544.640 6996.000 1550.040 ;
        RECT 4.400 1543.240 6996.000 1544.640 ;
        RECT 4.000 1520.840 6996.000 1543.240 ;
        RECT 4.000 1519.440 6995.600 1520.840 ;
        RECT 4.000 1514.040 6996.000 1519.440 ;
        RECT 4.400 1512.640 6996.000 1514.040 ;
        RECT 4.000 1493.640 6996.000 1512.640 ;
        RECT 4.000 1492.240 6995.600 1493.640 ;
        RECT 4.000 1483.440 6996.000 1492.240 ;
        RECT 4.400 1482.040 6996.000 1483.440 ;
        RECT 4.000 1463.040 6996.000 1482.040 ;
        RECT 4.000 1461.640 6995.600 1463.040 ;
        RECT 4.000 1456.240 6996.000 1461.640 ;
        RECT 4.400 1454.840 6996.000 1456.240 ;
        RECT 4.000 1435.840 6996.000 1454.840 ;
        RECT 4.000 1434.440 6995.600 1435.840 ;
        RECT 4.000 1425.640 6996.000 1434.440 ;
        RECT 4.400 1424.240 6996.000 1425.640 ;
        RECT 4.000 1405.240 6996.000 1424.240 ;
        RECT 4.000 1403.840 6995.600 1405.240 ;
        RECT 4.000 1398.440 6996.000 1403.840 ;
        RECT 4.400 1397.040 6996.000 1398.440 ;
        RECT 4.000 1378.040 6996.000 1397.040 ;
        RECT 4.000 1376.640 6995.600 1378.040 ;
        RECT 4.000 1367.840 6996.000 1376.640 ;
        RECT 4.400 1366.440 6996.000 1367.840 ;
        RECT 4.000 1347.440 6996.000 1366.440 ;
        RECT 4.000 1346.040 6995.600 1347.440 ;
        RECT 4.000 1340.640 6996.000 1346.040 ;
        RECT 4.400 1339.240 6996.000 1340.640 ;
        RECT 4.000 1316.840 6996.000 1339.240 ;
        RECT 4.000 1315.440 6995.600 1316.840 ;
        RECT 4.000 1310.040 6996.000 1315.440 ;
        RECT 4.400 1308.640 6996.000 1310.040 ;
        RECT 4.000 1289.640 6996.000 1308.640 ;
        RECT 4.000 1288.240 6995.600 1289.640 ;
        RECT 4.000 1282.840 6996.000 1288.240 ;
        RECT 4.400 1281.440 6996.000 1282.840 ;
        RECT 4.000 1259.040 6996.000 1281.440 ;
        RECT 4.000 1257.640 6995.600 1259.040 ;
        RECT 4.000 1252.240 6996.000 1257.640 ;
        RECT 4.400 1250.840 6996.000 1252.240 ;
        RECT 4.000 1231.840 6996.000 1250.840 ;
        RECT 4.000 1230.440 6995.600 1231.840 ;
        RECT 4.000 1221.640 6996.000 1230.440 ;
        RECT 4.400 1220.240 6996.000 1221.640 ;
        RECT 4.000 1201.240 6996.000 1220.240 ;
        RECT 4.000 1199.840 6995.600 1201.240 ;
        RECT 4.000 1194.440 6996.000 1199.840 ;
        RECT 4.400 1193.040 6996.000 1194.440 ;
        RECT 4.000 1174.040 6996.000 1193.040 ;
        RECT 4.000 1172.640 6995.600 1174.040 ;
        RECT 4.000 1163.840 6996.000 1172.640 ;
        RECT 4.400 1162.440 6996.000 1163.840 ;
        RECT 4.000 1143.440 6996.000 1162.440 ;
        RECT 4.000 1142.040 6995.600 1143.440 ;
        RECT 4.000 1136.640 6996.000 1142.040 ;
        RECT 4.400 1135.240 6996.000 1136.640 ;
        RECT 4.000 1116.240 6996.000 1135.240 ;
        RECT 4.000 1114.840 6995.600 1116.240 ;
        RECT 4.000 1106.040 6996.000 1114.840 ;
        RECT 4.400 1104.640 6996.000 1106.040 ;
        RECT 4.000 1085.640 6996.000 1104.640 ;
        RECT 4.000 1084.240 6995.600 1085.640 ;
        RECT 4.000 1078.840 6996.000 1084.240 ;
        RECT 4.400 1077.440 6996.000 1078.840 ;
        RECT 4.000 1055.040 6996.000 1077.440 ;
        RECT 4.000 1053.640 6995.600 1055.040 ;
        RECT 4.000 1048.240 6996.000 1053.640 ;
        RECT 4.400 1046.840 6996.000 1048.240 ;
        RECT 4.000 1027.840 6996.000 1046.840 ;
        RECT 4.000 1026.440 6995.600 1027.840 ;
        RECT 4.000 1017.640 6996.000 1026.440 ;
        RECT 4.400 1016.240 6996.000 1017.640 ;
        RECT 4.000 997.240 6996.000 1016.240 ;
        RECT 4.000 995.840 6995.600 997.240 ;
        RECT 4.000 990.440 6996.000 995.840 ;
        RECT 4.400 989.040 6996.000 990.440 ;
        RECT 4.000 970.040 6996.000 989.040 ;
        RECT 4.000 968.640 6995.600 970.040 ;
        RECT 4.000 959.840 6996.000 968.640 ;
        RECT 4.400 958.440 6996.000 959.840 ;
        RECT 4.000 939.440 6996.000 958.440 ;
        RECT 4.000 938.040 6995.600 939.440 ;
        RECT 4.000 932.640 6996.000 938.040 ;
        RECT 4.400 931.240 6996.000 932.640 ;
        RECT 4.000 912.240 6996.000 931.240 ;
        RECT 4.000 910.840 6995.600 912.240 ;
        RECT 4.000 902.040 6996.000 910.840 ;
        RECT 4.400 900.640 6996.000 902.040 ;
        RECT 4.000 881.640 6996.000 900.640 ;
        RECT 4.000 880.240 6995.600 881.640 ;
        RECT 4.000 874.840 6996.000 880.240 ;
        RECT 4.400 873.440 6996.000 874.840 ;
        RECT 4.000 851.040 6996.000 873.440 ;
        RECT 4.000 849.640 6995.600 851.040 ;
        RECT 4.000 844.240 6996.000 849.640 ;
        RECT 4.400 842.840 6996.000 844.240 ;
        RECT 4.000 823.840 6996.000 842.840 ;
        RECT 4.000 822.440 6995.600 823.840 ;
        RECT 4.000 813.640 6996.000 822.440 ;
        RECT 4.400 812.240 6996.000 813.640 ;
        RECT 4.000 793.240 6996.000 812.240 ;
        RECT 4.000 791.840 6995.600 793.240 ;
        RECT 4.000 786.440 6996.000 791.840 ;
        RECT 4.400 785.040 6996.000 786.440 ;
        RECT 4.000 766.040 6996.000 785.040 ;
        RECT 4.000 764.640 6995.600 766.040 ;
        RECT 4.000 755.840 6996.000 764.640 ;
        RECT 4.400 754.440 6996.000 755.840 ;
        RECT 4.000 735.440 6996.000 754.440 ;
        RECT 4.000 734.040 6995.600 735.440 ;
        RECT 4.000 728.640 6996.000 734.040 ;
        RECT 4.400 727.240 6996.000 728.640 ;
        RECT 4.000 708.240 6996.000 727.240 ;
        RECT 4.000 706.840 6995.600 708.240 ;
        RECT 4.000 698.040 6996.000 706.840 ;
        RECT 4.400 696.640 6996.000 698.040 ;
        RECT 4.000 677.640 6996.000 696.640 ;
        RECT 4.000 676.240 6995.600 677.640 ;
        RECT 4.000 670.840 6996.000 676.240 ;
        RECT 4.400 669.440 6996.000 670.840 ;
        RECT 4.000 647.040 6996.000 669.440 ;
        RECT 4.000 645.640 6995.600 647.040 ;
        RECT 4.000 640.240 6996.000 645.640 ;
        RECT 4.400 638.840 6996.000 640.240 ;
        RECT 4.000 619.840 6996.000 638.840 ;
        RECT 4.000 618.440 6995.600 619.840 ;
        RECT 4.000 609.640 6996.000 618.440 ;
        RECT 4.400 608.240 6996.000 609.640 ;
        RECT 4.000 589.240 6996.000 608.240 ;
        RECT 4.000 587.840 6995.600 589.240 ;
        RECT 4.000 582.440 6996.000 587.840 ;
        RECT 4.400 581.040 6996.000 582.440 ;
        RECT 4.000 562.040 6996.000 581.040 ;
        RECT 4.000 560.640 6995.600 562.040 ;
        RECT 4.000 551.840 6996.000 560.640 ;
        RECT 4.400 550.440 6996.000 551.840 ;
        RECT 4.000 531.440 6996.000 550.440 ;
        RECT 4.000 530.040 6995.600 531.440 ;
        RECT 4.000 524.640 6996.000 530.040 ;
        RECT 4.400 523.240 6996.000 524.640 ;
        RECT 4.000 504.240 6996.000 523.240 ;
        RECT 4.000 502.840 6995.600 504.240 ;
        RECT 4.000 494.040 6996.000 502.840 ;
        RECT 4.400 492.640 6996.000 494.040 ;
        RECT 4.000 473.640 6996.000 492.640 ;
        RECT 4.000 472.240 6995.600 473.640 ;
        RECT 4.000 466.840 6996.000 472.240 ;
        RECT 4.400 465.440 6996.000 466.840 ;
        RECT 4.000 443.040 6996.000 465.440 ;
        RECT 4.000 441.640 6995.600 443.040 ;
        RECT 4.000 436.240 6996.000 441.640 ;
        RECT 4.400 434.840 6996.000 436.240 ;
        RECT 4.000 415.840 6996.000 434.840 ;
        RECT 4.000 414.440 6995.600 415.840 ;
        RECT 4.000 405.640 6996.000 414.440 ;
        RECT 4.400 404.240 6996.000 405.640 ;
        RECT 4.000 385.240 6996.000 404.240 ;
        RECT 4.000 383.840 6995.600 385.240 ;
        RECT 4.000 378.440 6996.000 383.840 ;
        RECT 4.400 377.040 6996.000 378.440 ;
        RECT 4.000 358.040 6996.000 377.040 ;
        RECT 4.000 356.640 6995.600 358.040 ;
        RECT 4.000 347.840 6996.000 356.640 ;
        RECT 4.400 346.440 6996.000 347.840 ;
        RECT 4.000 327.440 6996.000 346.440 ;
        RECT 4.000 326.040 6995.600 327.440 ;
        RECT 4.000 320.640 6996.000 326.040 ;
        RECT 4.400 319.240 6996.000 320.640 ;
        RECT 4.000 300.240 6996.000 319.240 ;
        RECT 4.000 298.840 6995.600 300.240 ;
        RECT 4.000 290.040 6996.000 298.840 ;
        RECT 4.400 288.640 6996.000 290.040 ;
        RECT 4.000 269.640 6996.000 288.640 ;
        RECT 4.000 268.240 6995.600 269.640 ;
        RECT 4.000 262.840 6996.000 268.240 ;
        RECT 4.400 261.440 6996.000 262.840 ;
        RECT 4.000 239.040 6996.000 261.440 ;
        RECT 4.000 237.640 6995.600 239.040 ;
        RECT 4.000 232.240 6996.000 237.640 ;
        RECT 4.400 230.840 6996.000 232.240 ;
        RECT 4.000 211.840 6996.000 230.840 ;
        RECT 4.000 210.440 6995.600 211.840 ;
        RECT 4.000 201.640 6996.000 210.440 ;
        RECT 4.400 200.240 6996.000 201.640 ;
        RECT 4.000 181.240 6996.000 200.240 ;
        RECT 4.000 179.840 6995.600 181.240 ;
        RECT 4.000 174.440 6996.000 179.840 ;
        RECT 4.400 173.040 6996.000 174.440 ;
        RECT 4.000 154.040 6996.000 173.040 ;
        RECT 4.000 152.640 6995.600 154.040 ;
        RECT 4.000 143.840 6996.000 152.640 ;
        RECT 4.400 142.440 6996.000 143.840 ;
        RECT 4.000 123.440 6996.000 142.440 ;
        RECT 4.000 122.040 6995.600 123.440 ;
        RECT 4.000 116.640 6996.000 122.040 ;
        RECT 4.400 115.240 6996.000 116.640 ;
        RECT 4.000 96.240 6996.000 115.240 ;
        RECT 4.000 94.840 6995.600 96.240 ;
        RECT 4.000 86.040 6996.000 94.840 ;
        RECT 4.400 84.640 6996.000 86.040 ;
        RECT 4.000 65.640 6996.000 84.640 ;
        RECT 4.000 64.240 6995.600 65.640 ;
        RECT 4.000 58.840 6996.000 64.240 ;
        RECT 4.400 57.440 6996.000 58.840 ;
        RECT 4.000 35.040 6996.000 57.440 ;
        RECT 4.000 33.640 6995.600 35.040 ;
        RECT 4.000 28.240 6996.000 33.640 ;
        RECT 4.400 26.840 6996.000 28.240 ;
        RECT 4.000 7.840 6996.000 26.840 ;
        RECT 4.000 6.975 6995.600 7.840 ;
      LAYER met4 ;
        RECT 26.550 2579.200 6969.130 2581.105 ;
        RECT 26.550 22.615 35.360 2579.200 ;
        RECT 37.760 22.615 38.660 2579.200 ;
        RECT 41.060 2509.120 215.360 2579.200 ;
        RECT 217.760 2509.120 218.660 2579.200 ;
        RECT 221.060 2509.120 395.360 2579.200 ;
        RECT 397.760 2509.120 398.660 2579.200 ;
        RECT 401.060 2509.120 575.360 2579.200 ;
        RECT 577.760 2509.740 578.660 2579.200 ;
        RECT 581.060 2509.740 755.360 2579.200 ;
        RECT 577.760 2509.120 755.360 2509.740 ;
        RECT 757.760 2509.120 758.660 2579.200 ;
        RECT 761.060 2513.920 935.360 2579.200 ;
        RECT 761.060 2509.120 864.980 2513.920 ;
        RECT 41.060 2073.420 864.980 2509.120 ;
        RECT 41.060 2072.800 398.660 2073.420 ;
        RECT 41.060 526.740 215.360 2072.800 ;
        RECT 217.760 526.740 218.660 2072.800 ;
        RECT 221.060 526.740 395.360 2072.800 ;
        RECT 397.760 526.740 398.660 2072.800 ;
        RECT 41.060 526.120 398.660 526.740 ;
        RECT 401.060 526.120 575.360 2073.420 ;
        RECT 577.760 2072.800 755.360 2073.420 ;
        RECT 577.760 526.740 578.660 2072.800 ;
        RECT 581.060 526.740 755.360 2072.800 ;
        RECT 577.760 526.120 755.360 526.740 ;
        RECT 757.760 526.120 758.660 2073.420 ;
        RECT 761.060 2072.000 864.980 2073.420 ;
        RECT 867.380 2072.000 935.360 2513.920 ;
        RECT 761.060 528.320 935.360 2072.000 ;
        RECT 761.060 526.120 864.980 528.320 ;
        RECT 41.060 90.420 864.980 526.120 ;
        RECT 41.060 22.615 215.360 90.420 ;
        RECT 217.760 22.615 218.660 90.420 ;
        RECT 221.060 22.615 395.360 90.420 ;
        RECT 397.760 22.615 398.660 90.420 ;
        RECT 401.060 22.615 575.360 90.420 ;
        RECT 577.760 89.800 755.360 90.420 ;
        RECT 577.760 22.615 578.660 89.800 ;
        RECT 581.060 22.615 755.360 89.800 ;
        RECT 757.760 22.615 758.660 90.420 ;
        RECT 761.060 86.400 864.980 90.420 ;
        RECT 867.380 86.400 935.360 528.320 ;
        RECT 761.060 22.615 935.360 86.400 ;
        RECT 937.760 2509.120 938.660 2579.200 ;
        RECT 941.060 2509.740 1115.360 2579.200 ;
        RECT 1117.760 2509.740 1118.660 2579.200 ;
        RECT 941.060 2509.120 1118.660 2509.740 ;
        RECT 1121.060 2509.120 1295.360 2579.200 ;
        RECT 1297.760 2509.120 1298.660 2579.200 ;
        RECT 1301.060 2509.120 1475.360 2579.200 ;
        RECT 1477.760 2509.740 1478.660 2579.200 ;
        RECT 1481.060 2509.740 1655.360 2579.200 ;
        RECT 1477.760 2509.120 1655.360 2509.740 ;
        RECT 937.760 2073.420 1655.360 2509.120 ;
        RECT 937.760 526.120 938.660 2073.420 ;
        RECT 941.060 2072.800 1118.660 2073.420 ;
        RECT 941.060 526.740 1115.360 2072.800 ;
        RECT 1117.760 526.740 1118.660 2072.800 ;
        RECT 941.060 526.120 1118.660 526.740 ;
        RECT 1121.060 526.120 1295.360 2073.420 ;
        RECT 1297.760 526.120 1298.660 2073.420 ;
        RECT 1301.060 526.120 1475.360 2073.420 ;
        RECT 1477.760 2072.800 1655.360 2073.420 ;
        RECT 1477.760 526.740 1478.660 2072.800 ;
        RECT 1481.060 526.740 1655.360 2072.800 ;
        RECT 1477.760 526.120 1655.360 526.740 ;
        RECT 937.760 90.420 1655.360 526.120 ;
        RECT 937.760 22.615 938.660 90.420 ;
        RECT 941.060 89.800 1118.660 90.420 ;
        RECT 941.060 22.615 1115.360 89.800 ;
        RECT 1117.760 22.615 1118.660 89.800 ;
        RECT 1121.060 22.615 1295.360 90.420 ;
        RECT 1297.760 22.615 1298.660 90.420 ;
        RECT 1301.060 22.615 1475.360 90.420 ;
        RECT 1477.760 89.800 1655.360 90.420 ;
        RECT 1477.760 22.615 1478.660 89.800 ;
        RECT 1481.060 22.615 1655.360 89.800 ;
        RECT 1657.760 22.615 1658.660 2579.200 ;
        RECT 1661.060 2509.120 1835.360 2579.200 ;
        RECT 1837.760 2509.120 1838.660 2579.200 ;
        RECT 1841.060 2509.740 2015.360 2579.200 ;
        RECT 2017.760 2509.740 2018.660 2579.200 ;
        RECT 1841.060 2509.120 2018.660 2509.740 ;
        RECT 2021.060 2509.120 2195.360 2579.200 ;
        RECT 2197.760 2509.120 2198.660 2579.200 ;
        RECT 2201.060 2509.120 2375.360 2579.200 ;
        RECT 2377.760 2509.120 2378.660 2579.200 ;
        RECT 2381.060 2509.120 2555.360 2579.200 ;
        RECT 1661.060 2073.420 2555.360 2509.120 ;
        RECT 1661.060 526.120 1835.360 2073.420 ;
        RECT 1837.760 526.120 1838.660 2073.420 ;
        RECT 1841.060 2072.800 2195.360 2073.420 ;
        RECT 1841.060 526.740 2015.360 2072.800 ;
        RECT 2017.760 526.740 2018.660 2072.800 ;
        RECT 2021.060 526.740 2195.360 2072.800 ;
        RECT 1841.060 526.120 2195.360 526.740 ;
        RECT 2197.760 526.120 2198.660 2073.420 ;
        RECT 2201.060 526.120 2375.360 2073.420 ;
        RECT 2377.760 526.120 2378.660 2073.420 ;
        RECT 2381.060 526.120 2555.360 2073.420 ;
        RECT 1661.060 90.420 2555.360 526.120 ;
        RECT 1661.060 22.615 1835.360 90.420 ;
        RECT 1837.760 22.615 1838.660 90.420 ;
        RECT 1841.060 89.800 2018.660 90.420 ;
        RECT 1841.060 22.615 2015.360 89.800 ;
        RECT 2017.760 22.615 2018.660 89.800 ;
        RECT 2021.060 22.615 2195.360 90.420 ;
        RECT 2197.760 22.615 2198.660 90.420 ;
        RECT 2201.060 22.615 2375.360 90.420 ;
        RECT 2377.760 22.615 2378.660 90.420 ;
        RECT 2381.060 22.615 2555.360 90.420 ;
        RECT 2557.760 22.615 2558.660 2579.200 ;
        RECT 2561.060 2509.120 2735.360 2579.200 ;
        RECT 2737.760 2509.120 2738.660 2579.200 ;
        RECT 2741.060 2509.740 2915.360 2579.200 ;
        RECT 2917.760 2509.740 2918.660 2579.200 ;
        RECT 2741.060 2509.120 2918.660 2509.740 ;
        RECT 2921.060 2509.120 3095.360 2579.200 ;
        RECT 3097.760 2509.120 3098.660 2579.200 ;
        RECT 3101.060 2509.120 3275.360 2579.200 ;
        RECT 3277.760 2509.120 3278.660 2579.200 ;
        RECT 3281.060 2509.120 3455.360 2579.200 ;
        RECT 2561.060 2073.420 3455.360 2509.120 ;
        RECT 2561.060 2072.800 2918.660 2073.420 ;
        RECT 2561.060 526.740 2735.360 2072.800 ;
        RECT 2737.760 526.740 2738.660 2072.800 ;
        RECT 2741.060 526.740 2915.360 2072.800 ;
        RECT 2917.760 526.740 2918.660 2072.800 ;
        RECT 2561.060 526.120 2918.660 526.740 ;
        RECT 2921.060 526.120 3095.360 2073.420 ;
        RECT 3097.760 526.120 3098.660 2073.420 ;
        RECT 3101.060 526.120 3275.360 2073.420 ;
        RECT 3277.760 526.120 3278.660 2073.420 ;
        RECT 3281.060 526.120 3455.360 2073.420 ;
        RECT 2561.060 90.420 3455.360 526.120 ;
        RECT 2561.060 22.615 2735.360 90.420 ;
        RECT 2737.760 22.615 2738.660 90.420 ;
        RECT 2741.060 89.800 2918.660 90.420 ;
        RECT 2741.060 22.615 2915.360 89.800 ;
        RECT 2917.760 22.615 2918.660 89.800 ;
        RECT 2921.060 22.615 3095.360 90.420 ;
        RECT 3097.760 22.615 3098.660 90.420 ;
        RECT 3101.060 22.615 3275.360 90.420 ;
        RECT 3277.760 22.615 3278.660 90.420 ;
        RECT 3281.060 22.615 3455.360 90.420 ;
        RECT 3457.760 22.615 3458.660 2579.200 ;
        RECT 3461.060 2509.120 3635.360 2579.200 ;
        RECT 3637.760 2509.120 3638.660 2579.200 ;
        RECT 3641.060 2509.120 3815.360 2579.200 ;
        RECT 3817.760 2509.740 3818.660 2579.200 ;
        RECT 3821.060 2509.740 3995.360 2579.200 ;
        RECT 3817.760 2509.120 3995.360 2509.740 ;
        RECT 3997.760 2509.120 3998.660 2579.200 ;
        RECT 4001.060 2509.120 4175.360 2579.200 ;
        RECT 4177.760 2509.120 4178.660 2579.200 ;
        RECT 4181.060 2513.920 4355.360 2579.200 ;
        RECT 4181.060 2509.120 4263.460 2513.920 ;
        RECT 3461.060 2073.420 4263.460 2509.120 ;
        RECT 3461.060 526.120 3635.360 2073.420 ;
        RECT 3637.760 526.120 3638.660 2073.420 ;
        RECT 3641.060 2072.800 3818.660 2073.420 ;
        RECT 3641.060 526.740 3815.360 2072.800 ;
        RECT 3817.760 526.740 3818.660 2072.800 ;
        RECT 3641.060 526.120 3818.660 526.740 ;
        RECT 3821.060 526.120 3995.360 2073.420 ;
        RECT 3997.760 526.120 3998.660 2073.420 ;
        RECT 4001.060 526.120 4175.360 2073.420 ;
        RECT 4177.760 526.120 4178.660 2073.420 ;
        RECT 4181.060 2069.280 4263.460 2073.420 ;
        RECT 4265.860 2069.280 4267.140 2513.920 ;
        RECT 4269.540 2509.120 4355.360 2513.920 ;
        RECT 4357.760 2509.120 4358.660 2579.200 ;
        RECT 4361.060 2509.120 4535.360 2579.200 ;
        RECT 4537.760 2509.120 4538.660 2579.200 ;
        RECT 4541.060 2509.740 4715.360 2579.200 ;
        RECT 4717.760 2509.740 4718.660 2579.200 ;
        RECT 4541.060 2509.120 4718.660 2509.740 ;
        RECT 4721.060 2509.120 4895.360 2579.200 ;
        RECT 4897.760 2509.120 4898.660 2579.200 ;
        RECT 4901.060 2509.120 5075.360 2579.200 ;
        RECT 4269.540 2073.420 5075.360 2509.120 ;
        RECT 4269.540 2069.280 4355.360 2073.420 ;
        RECT 4181.060 531.040 4355.360 2069.280 ;
        RECT 4181.060 526.120 4263.460 531.040 ;
        RECT 3461.060 90.420 4263.460 526.120 ;
        RECT 3461.060 22.615 3635.360 90.420 ;
        RECT 3637.760 22.615 3638.660 90.420 ;
        RECT 3641.060 22.615 3815.360 90.420 ;
        RECT 3817.760 89.800 3995.360 90.420 ;
        RECT 3817.760 22.615 3818.660 89.800 ;
        RECT 3821.060 22.615 3995.360 89.800 ;
        RECT 3997.760 22.615 3998.660 90.420 ;
        RECT 4001.060 22.615 4175.360 90.420 ;
        RECT 4177.760 22.615 4178.660 90.420 ;
        RECT 4181.060 86.400 4263.460 90.420 ;
        RECT 4265.860 86.400 4267.140 531.040 ;
        RECT 4269.540 526.120 4355.360 531.040 ;
        RECT 4357.760 526.120 4358.660 2073.420 ;
        RECT 4361.060 2072.800 4718.660 2073.420 ;
        RECT 4361.060 526.740 4535.360 2072.800 ;
        RECT 4537.760 526.740 4538.660 2072.800 ;
        RECT 4541.060 526.740 4715.360 2072.800 ;
        RECT 4717.760 526.740 4718.660 2072.800 ;
        RECT 4361.060 526.120 4718.660 526.740 ;
        RECT 4721.060 526.120 4895.360 2073.420 ;
        RECT 4897.760 526.120 4898.660 2073.420 ;
        RECT 4901.060 526.120 5075.360 2073.420 ;
        RECT 4269.540 90.420 5075.360 526.120 ;
        RECT 4269.540 86.400 4355.360 90.420 ;
        RECT 4181.060 22.615 4355.360 86.400 ;
        RECT 4357.760 22.615 4358.660 90.420 ;
        RECT 4361.060 22.615 4535.360 90.420 ;
        RECT 4537.760 22.615 4538.660 90.420 ;
        RECT 4541.060 89.800 4718.660 90.420 ;
        RECT 4541.060 22.615 4715.360 89.800 ;
        RECT 4717.760 22.615 4718.660 89.800 ;
        RECT 4721.060 22.615 4895.360 90.420 ;
        RECT 4897.760 22.615 4898.660 90.420 ;
        RECT 4901.060 22.615 5075.360 90.420 ;
        RECT 5077.760 22.615 5078.660 2579.200 ;
        RECT 5081.060 2509.120 5255.360 2579.200 ;
        RECT 5257.760 2509.120 5258.660 2579.200 ;
        RECT 5261.060 2509.120 5435.360 2579.200 ;
        RECT 5437.760 2509.120 5438.660 2579.200 ;
        RECT 5441.060 2509.740 5615.360 2579.200 ;
        RECT 5617.760 2509.740 5618.660 2579.200 ;
        RECT 5441.060 2509.120 5618.660 2509.740 ;
        RECT 5621.060 2509.120 5795.360 2579.200 ;
        RECT 5797.760 2509.740 5798.660 2579.200 ;
        RECT 5801.060 2509.740 5975.360 2579.200 ;
        RECT 5797.760 2509.120 5975.360 2509.740 ;
        RECT 5081.060 2073.420 5975.360 2509.120 ;
        RECT 5081.060 526.120 5255.360 2073.420 ;
        RECT 5257.760 526.120 5258.660 2073.420 ;
        RECT 5261.060 526.120 5435.360 2073.420 ;
        RECT 5437.760 526.120 5438.660 2073.420 ;
        RECT 5441.060 2072.800 5618.660 2073.420 ;
        RECT 5441.060 526.740 5615.360 2072.800 ;
        RECT 5617.760 526.740 5618.660 2072.800 ;
        RECT 5441.060 526.120 5618.660 526.740 ;
        RECT 5621.060 526.120 5795.360 2073.420 ;
        RECT 5797.760 526.120 5798.660 2073.420 ;
        RECT 5801.060 526.120 5975.360 2073.420 ;
        RECT 5081.060 90.420 5975.360 526.120 ;
        RECT 5081.060 22.615 5255.360 90.420 ;
        RECT 5257.760 22.615 5258.660 90.420 ;
        RECT 5261.060 22.615 5435.360 90.420 ;
        RECT 5437.760 22.615 5438.660 90.420 ;
        RECT 5441.060 89.800 5618.660 90.420 ;
        RECT 5441.060 22.615 5615.360 89.800 ;
        RECT 5617.760 22.615 5618.660 89.800 ;
        RECT 5621.060 22.615 5795.360 90.420 ;
        RECT 5797.760 89.800 5975.360 90.420 ;
        RECT 5797.760 22.615 5798.660 89.800 ;
        RECT 5801.060 22.615 5975.360 89.800 ;
        RECT 5977.760 22.615 5978.660 2579.200 ;
        RECT 5981.060 2509.120 6155.360 2579.200 ;
        RECT 6157.760 2509.120 6158.660 2579.200 ;
        RECT 6161.060 2509.120 6335.360 2579.200 ;
        RECT 6337.760 2509.120 6338.660 2579.200 ;
        RECT 6341.060 2509.740 6515.360 2579.200 ;
        RECT 6517.760 2509.740 6518.660 2579.200 ;
        RECT 6341.060 2509.120 6518.660 2509.740 ;
        RECT 6521.060 2509.120 6695.360 2579.200 ;
        RECT 6697.760 2509.120 6698.660 2579.200 ;
        RECT 6701.060 2509.120 6875.360 2579.200 ;
        RECT 5981.060 2073.420 6875.360 2509.120 ;
        RECT 5981.060 526.120 6155.360 2073.420 ;
        RECT 6157.760 2072.800 6518.660 2073.420 ;
        RECT 6157.760 526.740 6158.660 2072.800 ;
        RECT 6161.060 526.740 6335.360 2072.800 ;
        RECT 6337.760 526.740 6338.660 2072.800 ;
        RECT 6341.060 526.740 6515.360 2072.800 ;
        RECT 6517.760 526.740 6518.660 2072.800 ;
        RECT 6157.760 526.120 6518.660 526.740 ;
        RECT 6521.060 526.120 6695.360 2073.420 ;
        RECT 6697.760 526.120 6698.660 2073.420 ;
        RECT 6701.060 526.120 6875.360 2073.420 ;
        RECT 5981.060 90.420 6875.360 526.120 ;
        RECT 5981.060 22.615 6155.360 90.420 ;
        RECT 6157.760 22.615 6158.660 90.420 ;
        RECT 6161.060 22.615 6335.360 90.420 ;
        RECT 6337.760 22.615 6338.660 90.420 ;
        RECT 6341.060 89.800 6518.660 90.420 ;
        RECT 6341.060 22.615 6515.360 89.800 ;
        RECT 6517.760 22.615 6518.660 89.800 ;
        RECT 6521.060 22.615 6695.360 90.420 ;
        RECT 6697.760 22.615 6698.660 90.420 ;
        RECT 6701.060 22.615 6875.360 90.420 ;
        RECT 6877.760 22.615 6878.660 2579.200 ;
        RECT 6881.060 22.615 6969.130 2579.200 ;
      LAYER met5 ;
        RECT 26.340 2204.110 6969.340 2324.700 ;
        RECT 26.340 2024.110 6969.340 2196.010 ;
        RECT 26.340 1844.110 6969.340 2016.010 ;
        RECT 26.340 1664.110 6969.340 1836.010 ;
        RECT 26.340 1484.110 6969.340 1656.010 ;
        RECT 26.340 1304.110 6969.340 1476.010 ;
        RECT 26.340 1124.110 6969.340 1296.010 ;
        RECT 26.340 944.110 6969.340 1116.010 ;
        RECT 26.340 764.110 6969.340 936.010 ;
        RECT 26.340 584.110 6969.340 756.010 ;
        RECT 26.340 404.110 6969.340 576.010 ;
        RECT 26.340 224.110 6969.340 396.010 ;
        RECT 26.340 58.700 6969.340 216.010 ;
  END
END RocketTile
END LIBRARY

